VERSION 5.8 ;
BUSBITCHARS "[]" ;
DIVIDERCHAR "/" ;
UNITS
    DATABASE MICRONS 1000 ;
END UNITS

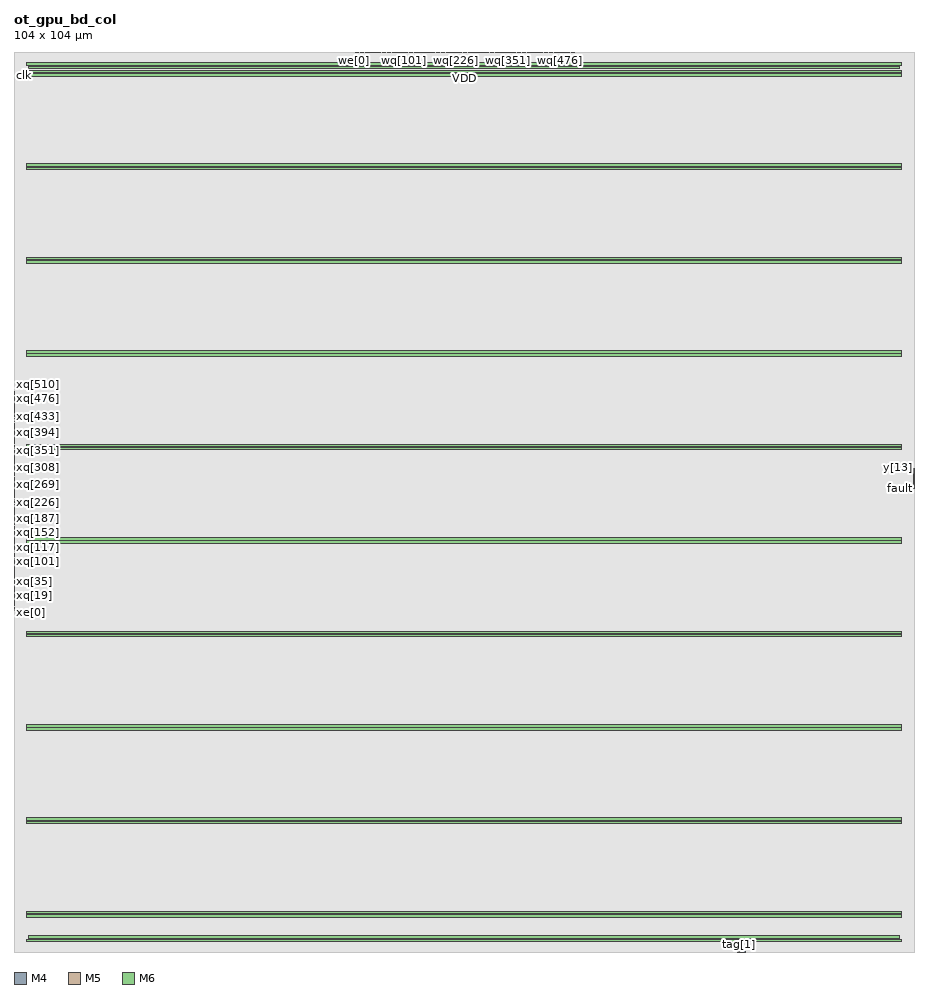
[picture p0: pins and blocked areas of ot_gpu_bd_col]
MACRO ot_gpu_bd_col
  FOREIGN ot_gpu_bd_col 0 0 ;
  CLASS BLOCK ;
  SIZE 104 BY 104 ;
  PIN clk
    DIRECTION INPUT ;
    USE SIGNAL ;
    PORT
      LAYER M4 ;
        RECT  0 101.232 0.084 101.256 ;
    END
  END clk
  PIN fault
    DIRECTION OUTPUT ;
    USE SIGNAL ;
    PORT
      LAYER M4 ;
        RECT  103.916 53.52 104 53.544 ;
    END
  END fault
  PIN first
    DIRECTION INPUT ;
    USE SIGNAL ;
    PORT
      LAYER M5 ;
        RECT  83.568 0 83.592 0.084 ;
    END
  END first
  PIN fp4
    DIRECTION INPUT ;
    USE SIGNAL ;
    PORT
      LAYER M5 ;
        RECT  83.616 0 83.64 0.084 ;
    END
  END fp4
  PIN last
    DIRECTION INPUT ;
    USE SIGNAL ;
    PORT
      LAYER M5 ;
        RECT  83.664 0 83.688 0.084 ;
    END
  END last
  PIN otag[0]
    DIRECTION OUTPUT ;
    USE SIGNAL ;
    PORT
      LAYER M4 ;
        RECT  103.916 53.568 104 53.592 ;
    END
  END otag[0]
  PIN otag[10]
    DIRECTION OUTPUT ;
    USE SIGNAL ;
    PORT
      LAYER M4 ;
        RECT  103.916 54.048 104 54.072 ;
    END
  END otag[10]
  PIN otag[11]
    DIRECTION OUTPUT ;
    USE SIGNAL ;
    PORT
      LAYER M4 ;
        RECT  103.916 54.096 104 54.12 ;
    END
  END otag[11]
  PIN otag[12]
    DIRECTION OUTPUT ;
    USE SIGNAL ;
    PORT
      LAYER M4 ;
        RECT  103.916 54.144 104 54.168 ;
    END
  END otag[12]
  PIN otag[13]
    DIRECTION OUTPUT ;
    USE SIGNAL ;
    PORT
      LAYER M4 ;
        RECT  103.916 54.192 104 54.216 ;
    END
  END otag[13]
  PIN otag[14]
    DIRECTION OUTPUT ;
    USE SIGNAL ;
    PORT
      LAYER M4 ;
        RECT  103.916 54.24 104 54.264 ;
    END
  END otag[14]
  PIN otag[15]
    DIRECTION OUTPUT ;
    USE SIGNAL ;
    PORT
      LAYER M4 ;
        RECT  103.916 54.288 104 54.312 ;
    END
  END otag[15]
  PIN otag[1]
    DIRECTION OUTPUT ;
    USE SIGNAL ;
    PORT
      LAYER M4 ;
        RECT  103.916 53.616 104 53.64 ;
    END
  END otag[1]
  PIN otag[2]
    DIRECTION OUTPUT ;
    USE SIGNAL ;
    PORT
      LAYER M4 ;
        RECT  103.916 53.664 104 53.688 ;
    END
  END otag[2]
  PIN otag[3]
    DIRECTION OUTPUT ;
    USE SIGNAL ;
    PORT
      LAYER M4 ;
        RECT  103.916 53.712 104 53.736 ;
    END
  END otag[3]
  PIN otag[4]
    DIRECTION OUTPUT ;
    USE SIGNAL ;
    PORT
      LAYER M4 ;
        RECT  103.916 53.76 104 53.784 ;
    END
  END otag[4]
  PIN otag[5]
    DIRECTION OUTPUT ;
    USE SIGNAL ;
    PORT
      LAYER M4 ;
        RECT  103.916 53.808 104 53.832 ;
    END
  END otag[5]
  PIN otag[6]
    DIRECTION OUTPUT ;
    USE SIGNAL ;
    PORT
      LAYER M4 ;
        RECT  103.916 53.856 104 53.88 ;
    END
  END otag[6]
  PIN otag[7]
    DIRECTION OUTPUT ;
    USE SIGNAL ;
    PORT
      LAYER M4 ;
        RECT  103.916 53.904 104 53.928 ;
    END
  END otag[7]
  PIN otag[8]
    DIRECTION OUTPUT ;
    USE SIGNAL ;
    PORT
      LAYER M4 ;
        RECT  103.916 53.952 104 53.976 ;
    END
  END otag[8]
  PIN otag[9]
    DIRECTION OUTPUT ;
    USE SIGNAL ;
    PORT
      LAYER M4 ;
        RECT  103.916 54 104 54.024 ;
    END
  END otag[9]
  PIN ov
    DIRECTION OUTPUT ;
    USE SIGNAL ;
    PORT
      LAYER M4 ;
        RECT  103.916 54.336 104 54.36 ;
    END
  END ov
  PIN rst_n
    DIRECTION INPUT ;
    USE SIGNAL ;
    PORT
      LAYER M5 ;
        RECT  83.712 0 83.736 0.084 ;
    END
  END rst_n
  PIN tag[0]
    DIRECTION INPUT ;
    USE SIGNAL ;
    PORT
      LAYER M5 ;
        RECT  83.76 0 83.784 0.084 ;
    END
  END tag[0]
  PIN tag[10]
    DIRECTION INPUT ;
    USE SIGNAL ;
    PORT
      LAYER M5 ;
        RECT  84.24 0 84.264 0.084 ;
    END
  END tag[10]
  PIN tag[11]
    DIRECTION INPUT ;
    USE SIGNAL ;
    PORT
      LAYER M5 ;
        RECT  84.288 0 84.312 0.084 ;
    END
  END tag[11]
  PIN tag[12]
    DIRECTION INPUT ;
    USE SIGNAL ;
    PORT
      LAYER M5 ;
        RECT  84.336 0 84.36 0.084 ;
    END
  END tag[12]
  PIN tag[13]
    DIRECTION INPUT ;
    USE SIGNAL ;
    PORT
      LAYER M5 ;
        RECT  84.384 0 84.408 0.084 ;
    END
  END tag[13]
  PIN tag[14]
    DIRECTION INPUT ;
    USE SIGNAL ;
    PORT
      LAYER M5 ;
        RECT  84.432 0 84.456 0.084 ;
    END
  END tag[14]
  PIN tag[15]
    DIRECTION INPUT ;
    USE SIGNAL ;
    PORT
      LAYER M5 ;
        RECT  84.48 0 84.504 0.084 ;
    END
  END tag[15]
  PIN tag[1]
    DIRECTION INPUT ;
    USE SIGNAL ;
    PORT
      LAYER M5 ;
        RECT  83.808 0 83.832 0.084 ;
    END
  END tag[1]
  PIN tag[2]
    DIRECTION INPUT ;
    USE SIGNAL ;
    PORT
      LAYER M5 ;
        RECT  83.856 0 83.88 0.084 ;
    END
  END tag[2]
  PIN tag[3]
    DIRECTION INPUT ;
    USE SIGNAL ;
    PORT
      LAYER M5 ;
        RECT  83.904 0 83.928 0.084 ;
    END
  END tag[3]
  PIN tag[4]
    DIRECTION INPUT ;
    USE SIGNAL ;
    PORT
      LAYER M5 ;
        RECT  83.952 0 83.976 0.084 ;
    END
  END tag[4]
  PIN tag[5]
    DIRECTION INPUT ;
    USE SIGNAL ;
    PORT
      LAYER M5 ;
        RECT  84 0 84.024 0.084 ;
    END
  END tag[5]
  PIN tag[6]
    DIRECTION INPUT ;
    USE SIGNAL ;
    PORT
      LAYER M5 ;
        RECT  84.048 0 84.072 0.084 ;
    END
  END tag[6]
  PIN tag[7]
    DIRECTION INPUT ;
    USE SIGNAL ;
    PORT
      LAYER M5 ;
        RECT  84.096 0 84.12 0.084 ;
    END
  END tag[7]
  PIN tag[8]
    DIRECTION INPUT ;
    USE SIGNAL ;
    PORT
      LAYER M5 ;
        RECT  84.144 0 84.168 0.084 ;
    END
  END tag[8]
  PIN tag[9]
    DIRECTION INPUT ;
    USE SIGNAL ;
    PORT
      LAYER M5 ;
        RECT  84.192 0 84.216 0.084 ;
    END
  END tag[9]
  PIN v
    DIRECTION INPUT ;
    USE SIGNAL ;
    PORT
      LAYER M5 ;
        RECT  84.528 0 84.552 0.084 ;
    END
  END v
  PIN we[0]
    DIRECTION INPUT ;
    USE SIGNAL ;
    PORT
      LAYER M5 ;
        RECT  39.264 103.916 39.288 104 ;
    END
  END we[0]
  PIN we[10]
    DIRECTION INPUT ;
    USE SIGNAL ;
    PORT
      LAYER M5 ;
        RECT  39.744 103.916 39.768 104 ;
    END
  END we[10]
  PIN we[11]
    DIRECTION INPUT ;
    USE SIGNAL ;
    PORT
      LAYER M5 ;
        RECT  39.792 103.916 39.816 104 ;
    END
  END we[11]
  PIN we[12]
    DIRECTION INPUT ;
    USE SIGNAL ;
    PORT
      LAYER M5 ;
        RECT  39.84 103.916 39.864 104 ;
    END
  END we[12]
  PIN we[13]
    DIRECTION INPUT ;
    USE SIGNAL ;
    PORT
      LAYER M5 ;
        RECT  39.888 103.916 39.912 104 ;
    END
  END we[13]
  PIN we[14]
    DIRECTION INPUT ;
    USE SIGNAL ;
    PORT
      LAYER M5 ;
        RECT  39.936 103.916 39.96 104 ;
    END
  END we[14]
  PIN we[15]
    DIRECTION INPUT ;
    USE SIGNAL ;
    PORT
      LAYER M5 ;
        RECT  39.984 103.916 40.008 104 ;
    END
  END we[15]
  PIN we[16]
    DIRECTION INPUT ;
    USE SIGNAL ;
    PORT
      LAYER M5 ;
        RECT  40.032 103.916 40.056 104 ;
    END
  END we[16]
  PIN we[17]
    DIRECTION INPUT ;
    USE SIGNAL ;
    PORT
      LAYER M5 ;
        RECT  40.08 103.916 40.104 104 ;
    END
  END we[17]
  PIN we[18]
    DIRECTION INPUT ;
    USE SIGNAL ;
    PORT
      LAYER M5 ;
        RECT  40.128 103.916 40.152 104 ;
    END
  END we[18]
  PIN we[19]
    DIRECTION INPUT ;
    USE SIGNAL ;
    PORT
      LAYER M5 ;
        RECT  40.176 103.916 40.2 104 ;
    END
  END we[19]
  PIN we[1]
    DIRECTION INPUT ;
    USE SIGNAL ;
    PORT
      LAYER M5 ;
        RECT  39.312 103.916 39.336 104 ;
    END
  END we[1]
  PIN we[2]
    DIRECTION INPUT ;
    USE SIGNAL ;
    PORT
      LAYER M5 ;
        RECT  39.36 103.916 39.384 104 ;
    END
  END we[2]
  PIN we[3]
    DIRECTION INPUT ;
    USE SIGNAL ;
    PORT
      LAYER M5 ;
        RECT  39.408 103.916 39.432 104 ;
    END
  END we[3]
  PIN we[4]
    DIRECTION INPUT ;
    USE SIGNAL ;
    PORT
      LAYER M5 ;
        RECT  39.456 103.916 39.48 104 ;
    END
  END we[4]
  PIN we[5]
    DIRECTION INPUT ;
    USE SIGNAL ;
    PORT
      LAYER M5 ;
        RECT  39.504 103.916 39.528 104 ;
    END
  END we[5]
  PIN we[6]
    DIRECTION INPUT ;
    USE SIGNAL ;
    PORT
      LAYER M5 ;
        RECT  39.552 103.916 39.576 104 ;
    END
  END we[6]
  PIN we[7]
    DIRECTION INPUT ;
    USE SIGNAL ;
    PORT
      LAYER M5 ;
        RECT  39.6 103.916 39.624 104 ;
    END
  END we[7]
  PIN we[8]
    DIRECTION INPUT ;
    USE SIGNAL ;
    PORT
      LAYER M5 ;
        RECT  39.648 103.916 39.672 104 ;
    END
  END we[8]
  PIN we[9]
    DIRECTION INPUT ;
    USE SIGNAL ;
    PORT
      LAYER M5 ;
        RECT  39.696 103.916 39.72 104 ;
    END
  END we[9]
  PIN wq[0]
    DIRECTION INPUT ;
    USE SIGNAL ;
    PORT
      LAYER M5 ;
        RECT  40.224 103.916 40.248 104 ;
    END
  END wq[0]
  PIN wq[100]
    DIRECTION INPUT ;
    USE SIGNAL ;
    PORT
      LAYER M5 ;
        RECT  45.024 103.916 45.048 104 ;
    END
  END wq[100]
  PIN wq[101]
    DIRECTION INPUT ;
    USE SIGNAL ;
    PORT
      LAYER M5 ;
        RECT  45.072 103.916 45.096 104 ;
    END
  END wq[101]
  PIN wq[102]
    DIRECTION INPUT ;
    USE SIGNAL ;
    PORT
      LAYER M5 ;
        RECT  45.12 103.916 45.144 104 ;
    END
  END wq[102]
  PIN wq[103]
    DIRECTION INPUT ;
    USE SIGNAL ;
    PORT
      LAYER M5 ;
        RECT  45.168 103.916 45.192 104 ;
    END
  END wq[103]
  PIN wq[104]
    DIRECTION INPUT ;
    USE SIGNAL ;
    PORT
      LAYER M5 ;
        RECT  45.216 103.916 45.24 104 ;
    END
  END wq[104]
  PIN wq[105]
    DIRECTION INPUT ;
    USE SIGNAL ;
    PORT
      LAYER M5 ;
        RECT  45.264 103.916 45.288 104 ;
    END
  END wq[105]
  PIN wq[106]
    DIRECTION INPUT ;
    USE SIGNAL ;
    PORT
      LAYER M5 ;
        RECT  45.312 103.916 45.336 104 ;
    END
  END wq[106]
  PIN wq[107]
    DIRECTION INPUT ;
    USE SIGNAL ;
    PORT
      LAYER M5 ;
        RECT  45.36 103.916 45.384 104 ;
    END
  END wq[107]
  PIN wq[108]
    DIRECTION INPUT ;
    USE SIGNAL ;
    PORT
      LAYER M5 ;
        RECT  45.408 103.916 45.432 104 ;
    END
  END wq[108]
  PIN wq[109]
    DIRECTION INPUT ;
    USE SIGNAL ;
    PORT
      LAYER M5 ;
        RECT  45.456 103.916 45.48 104 ;
    END
  END wq[109]
  PIN wq[10]
    DIRECTION INPUT ;
    USE SIGNAL ;
    PORT
      LAYER M5 ;
        RECT  40.704 103.916 40.728 104 ;
    END
  END wq[10]
  PIN wq[110]
    DIRECTION INPUT ;
    USE SIGNAL ;
    PORT
      LAYER M5 ;
        RECT  45.504 103.916 45.528 104 ;
    END
  END wq[110]
  PIN wq[111]
    DIRECTION INPUT ;
    USE SIGNAL ;
    PORT
      LAYER M5 ;
        RECT  45.552 103.916 45.576 104 ;
    END
  END wq[111]
  PIN wq[112]
    DIRECTION INPUT ;
    USE SIGNAL ;
    PORT
      LAYER M5 ;
        RECT  45.6 103.916 45.624 104 ;
    END
  END wq[112]
  PIN wq[113]
    DIRECTION INPUT ;
    USE SIGNAL ;
    PORT
      LAYER M5 ;
        RECT  45.648 103.916 45.672 104 ;
    END
  END wq[113]
  PIN wq[114]
    DIRECTION INPUT ;
    USE SIGNAL ;
    PORT
      LAYER M5 ;
        RECT  45.696 103.916 45.72 104 ;
    END
  END wq[114]
  PIN wq[115]
    DIRECTION INPUT ;
    USE SIGNAL ;
    PORT
      LAYER M5 ;
        RECT  45.744 103.916 45.768 104 ;
    END
  END wq[115]
  PIN wq[116]
    DIRECTION INPUT ;
    USE SIGNAL ;
    PORT
      LAYER M5 ;
        RECT  45.792 103.916 45.816 104 ;
    END
  END wq[116]
  PIN wq[117]
    DIRECTION INPUT ;
    USE SIGNAL ;
    PORT
      LAYER M5 ;
        RECT  45.84 103.916 45.864 104 ;
    END
  END wq[117]
  PIN wq[118]
    DIRECTION INPUT ;
    USE SIGNAL ;
    PORT
      LAYER M5 ;
        RECT  45.888 103.916 45.912 104 ;
    END
  END wq[118]
  PIN wq[119]
    DIRECTION INPUT ;
    USE SIGNAL ;
    PORT
      LAYER M5 ;
        RECT  45.936 103.916 45.96 104 ;
    END
  END wq[119]
  PIN wq[11]
    DIRECTION INPUT ;
    USE SIGNAL ;
    PORT
      LAYER M5 ;
        RECT  40.752 103.916 40.776 104 ;
    END
  END wq[11]
  PIN wq[120]
    DIRECTION INPUT ;
    USE SIGNAL ;
    PORT
      LAYER M5 ;
        RECT  45.984 103.916 46.008 104 ;
    END
  END wq[120]
  PIN wq[121]
    DIRECTION INPUT ;
    USE SIGNAL ;
    PORT
      LAYER M5 ;
        RECT  46.032 103.916 46.056 104 ;
    END
  END wq[121]
  PIN wq[122]
    DIRECTION INPUT ;
    USE SIGNAL ;
    PORT
      LAYER M5 ;
        RECT  46.08 103.916 46.104 104 ;
    END
  END wq[122]
  PIN wq[123]
    DIRECTION INPUT ;
    USE SIGNAL ;
    PORT
      LAYER M5 ;
        RECT  46.128 103.916 46.152 104 ;
    END
  END wq[123]
  PIN wq[124]
    DIRECTION INPUT ;
    USE SIGNAL ;
    PORT
      LAYER M5 ;
        RECT  46.176 103.916 46.2 104 ;
    END
  END wq[124]
  PIN wq[125]
    DIRECTION INPUT ;
    USE SIGNAL ;
    PORT
      LAYER M5 ;
        RECT  46.224 103.916 46.248 104 ;
    END
  END wq[125]
  PIN wq[126]
    DIRECTION INPUT ;
    USE SIGNAL ;
    PORT
      LAYER M5 ;
        RECT  46.272 103.916 46.296 104 ;
    END
  END wq[126]
  PIN wq[127]
    DIRECTION INPUT ;
    USE SIGNAL ;
    PORT
      LAYER M5 ;
        RECT  46.32 103.916 46.344 104 ;
    END
  END wq[127]
  PIN wq[128]
    DIRECTION INPUT ;
    USE SIGNAL ;
    PORT
      LAYER M5 ;
        RECT  46.368 103.916 46.392 104 ;
    END
  END wq[128]
  PIN wq[129]
    DIRECTION INPUT ;
    USE SIGNAL ;
    PORT
      LAYER M5 ;
        RECT  46.416 103.916 46.44 104 ;
    END
  END wq[129]
  PIN wq[12]
    DIRECTION INPUT ;
    USE SIGNAL ;
    PORT
      LAYER M5 ;
        RECT  40.8 103.916 40.824 104 ;
    END
  END wq[12]
  PIN wq[130]
    DIRECTION INPUT ;
    USE SIGNAL ;
    PORT
      LAYER M5 ;
        RECT  46.464 103.916 46.488 104 ;
    END
  END wq[130]
  PIN wq[131]
    DIRECTION INPUT ;
    USE SIGNAL ;
    PORT
      LAYER M5 ;
        RECT  46.512 103.916 46.536 104 ;
    END
  END wq[131]
  PIN wq[132]
    DIRECTION INPUT ;
    USE SIGNAL ;
    PORT
      LAYER M5 ;
        RECT  46.56 103.916 46.584 104 ;
    END
  END wq[132]
  PIN wq[133]
    DIRECTION INPUT ;
    USE SIGNAL ;
    PORT
      LAYER M5 ;
        RECT  46.608 103.916 46.632 104 ;
    END
  END wq[133]
  PIN wq[134]
    DIRECTION INPUT ;
    USE SIGNAL ;
    PORT
      LAYER M5 ;
        RECT  46.656 103.916 46.68 104 ;
    END
  END wq[134]
  PIN wq[135]
    DIRECTION INPUT ;
    USE SIGNAL ;
    PORT
      LAYER M5 ;
        RECT  46.704 103.916 46.728 104 ;
    END
  END wq[135]
  PIN wq[136]
    DIRECTION INPUT ;
    USE SIGNAL ;
    PORT
      LAYER M5 ;
        RECT  46.752 103.916 46.776 104 ;
    END
  END wq[136]
  PIN wq[137]
    DIRECTION INPUT ;
    USE SIGNAL ;
    PORT
      LAYER M5 ;
        RECT  46.8 103.916 46.824 104 ;
    END
  END wq[137]
  PIN wq[138]
    DIRECTION INPUT ;
    USE SIGNAL ;
    PORT
      LAYER M5 ;
        RECT  46.848 103.916 46.872 104 ;
    END
  END wq[138]
  PIN wq[139]
    DIRECTION INPUT ;
    USE SIGNAL ;
    PORT
      LAYER M5 ;
        RECT  46.896 103.916 46.92 104 ;
    END
  END wq[139]
  PIN wq[13]
    DIRECTION INPUT ;
    USE SIGNAL ;
    PORT
      LAYER M5 ;
        RECT  40.848 103.916 40.872 104 ;
    END
  END wq[13]
  PIN wq[140]
    DIRECTION INPUT ;
    USE SIGNAL ;
    PORT
      LAYER M5 ;
        RECT  46.944 103.916 46.968 104 ;
    END
  END wq[140]
  PIN wq[141]
    DIRECTION INPUT ;
    USE SIGNAL ;
    PORT
      LAYER M5 ;
        RECT  46.992 103.916 47.016 104 ;
    END
  END wq[141]
  PIN wq[142]
    DIRECTION INPUT ;
    USE SIGNAL ;
    PORT
      LAYER M5 ;
        RECT  47.04 103.916 47.064 104 ;
    END
  END wq[142]
  PIN wq[143]
    DIRECTION INPUT ;
    USE SIGNAL ;
    PORT
      LAYER M5 ;
        RECT  47.088 103.916 47.112 104 ;
    END
  END wq[143]
  PIN wq[144]
    DIRECTION INPUT ;
    USE SIGNAL ;
    PORT
      LAYER M5 ;
        RECT  47.136 103.916 47.16 104 ;
    END
  END wq[144]
  PIN wq[145]
    DIRECTION INPUT ;
    USE SIGNAL ;
    PORT
      LAYER M5 ;
        RECT  47.184 103.916 47.208 104 ;
    END
  END wq[145]
  PIN wq[146]
    DIRECTION INPUT ;
    USE SIGNAL ;
    PORT
      LAYER M5 ;
        RECT  47.232 103.916 47.256 104 ;
    END
  END wq[146]
  PIN wq[147]
    DIRECTION INPUT ;
    USE SIGNAL ;
    PORT
      LAYER M5 ;
        RECT  47.28 103.916 47.304 104 ;
    END
  END wq[147]
  PIN wq[148]
    DIRECTION INPUT ;
    USE SIGNAL ;
    PORT
      LAYER M5 ;
        RECT  47.328 103.916 47.352 104 ;
    END
  END wq[148]
  PIN wq[149]
    DIRECTION INPUT ;
    USE SIGNAL ;
    PORT
      LAYER M5 ;
        RECT  47.376 103.916 47.4 104 ;
    END
  END wq[149]
  PIN wq[14]
    DIRECTION INPUT ;
    USE SIGNAL ;
    PORT
      LAYER M5 ;
        RECT  40.896 103.916 40.92 104 ;
    END
  END wq[14]
  PIN wq[150]
    DIRECTION INPUT ;
    USE SIGNAL ;
    PORT
      LAYER M5 ;
        RECT  47.424 103.916 47.448 104 ;
    END
  END wq[150]
  PIN wq[151]
    DIRECTION INPUT ;
    USE SIGNAL ;
    PORT
      LAYER M5 ;
        RECT  47.472 103.916 47.496 104 ;
    END
  END wq[151]
  PIN wq[152]
    DIRECTION INPUT ;
    USE SIGNAL ;
    PORT
      LAYER M5 ;
        RECT  47.52 103.916 47.544 104 ;
    END
  END wq[152]
  PIN wq[153]
    DIRECTION INPUT ;
    USE SIGNAL ;
    PORT
      LAYER M5 ;
        RECT  47.568 103.916 47.592 104 ;
    END
  END wq[153]
  PIN wq[154]
    DIRECTION INPUT ;
    USE SIGNAL ;
    PORT
      LAYER M5 ;
        RECT  47.616 103.916 47.64 104 ;
    END
  END wq[154]
  PIN wq[155]
    DIRECTION INPUT ;
    USE SIGNAL ;
    PORT
      LAYER M5 ;
        RECT  47.664 103.916 47.688 104 ;
    END
  END wq[155]
  PIN wq[156]
    DIRECTION INPUT ;
    USE SIGNAL ;
    PORT
      LAYER M5 ;
        RECT  47.712 103.916 47.736 104 ;
    END
  END wq[156]
  PIN wq[157]
    DIRECTION INPUT ;
    USE SIGNAL ;
    PORT
      LAYER M5 ;
        RECT  47.76 103.916 47.784 104 ;
    END
  END wq[157]
  PIN wq[158]
    DIRECTION INPUT ;
    USE SIGNAL ;
    PORT
      LAYER M5 ;
        RECT  47.808 103.916 47.832 104 ;
    END
  END wq[158]
  PIN wq[159]
    DIRECTION INPUT ;
    USE SIGNAL ;
    PORT
      LAYER M5 ;
        RECT  47.856 103.916 47.88 104 ;
    END
  END wq[159]
  PIN wq[15]
    DIRECTION INPUT ;
    USE SIGNAL ;
    PORT
      LAYER M5 ;
        RECT  40.944 103.916 40.968 104 ;
    END
  END wq[15]
  PIN wq[160]
    DIRECTION INPUT ;
    USE SIGNAL ;
    PORT
      LAYER M5 ;
        RECT  47.904 103.916 47.928 104 ;
    END
  END wq[160]
  PIN wq[161]
    DIRECTION INPUT ;
    USE SIGNAL ;
    PORT
      LAYER M5 ;
        RECT  47.952 103.916 47.976 104 ;
    END
  END wq[161]
  PIN wq[162]
    DIRECTION INPUT ;
    USE SIGNAL ;
    PORT
      LAYER M5 ;
        RECT  48 103.916 48.024 104 ;
    END
  END wq[162]
  PIN wq[163]
    DIRECTION INPUT ;
    USE SIGNAL ;
    PORT
      LAYER M5 ;
        RECT  48.048 103.916 48.072 104 ;
    END
  END wq[163]
  PIN wq[164]
    DIRECTION INPUT ;
    USE SIGNAL ;
    PORT
      LAYER M5 ;
        RECT  48.096 103.916 48.12 104 ;
    END
  END wq[164]
  PIN wq[165]
    DIRECTION INPUT ;
    USE SIGNAL ;
    PORT
      LAYER M5 ;
        RECT  48.144 103.916 48.168 104 ;
    END
  END wq[165]
  PIN wq[166]
    DIRECTION INPUT ;
    USE SIGNAL ;
    PORT
      LAYER M5 ;
        RECT  48.192 103.916 48.216 104 ;
    END
  END wq[166]
  PIN wq[167]
    DIRECTION INPUT ;
    USE SIGNAL ;
    PORT
      LAYER M5 ;
        RECT  48.24 103.916 48.264 104 ;
    END
  END wq[167]
  PIN wq[168]
    DIRECTION INPUT ;
    USE SIGNAL ;
    PORT
      LAYER M5 ;
        RECT  48.288 103.916 48.312 104 ;
    END
  END wq[168]
  PIN wq[169]
    DIRECTION INPUT ;
    USE SIGNAL ;
    PORT
      LAYER M5 ;
        RECT  48.336 103.916 48.36 104 ;
    END
  END wq[169]
  PIN wq[16]
    DIRECTION INPUT ;
    USE SIGNAL ;
    PORT
      LAYER M5 ;
        RECT  40.992 103.916 41.016 104 ;
    END
  END wq[16]
  PIN wq[170]
    DIRECTION INPUT ;
    USE SIGNAL ;
    PORT
      LAYER M5 ;
        RECT  48.384 103.916 48.408 104 ;
    END
  END wq[170]
  PIN wq[171]
    DIRECTION INPUT ;
    USE SIGNAL ;
    PORT
      LAYER M5 ;
        RECT  48.432 103.916 48.456 104 ;
    END
  END wq[171]
  PIN wq[172]
    DIRECTION INPUT ;
    USE SIGNAL ;
    PORT
      LAYER M5 ;
        RECT  48.48 103.916 48.504 104 ;
    END
  END wq[172]
  PIN wq[173]
    DIRECTION INPUT ;
    USE SIGNAL ;
    PORT
      LAYER M5 ;
        RECT  48.528 103.916 48.552 104 ;
    END
  END wq[173]
  PIN wq[174]
    DIRECTION INPUT ;
    USE SIGNAL ;
    PORT
      LAYER M5 ;
        RECT  48.576 103.916 48.6 104 ;
    END
  END wq[174]
  PIN wq[175]
    DIRECTION INPUT ;
    USE SIGNAL ;
    PORT
      LAYER M5 ;
        RECT  48.624 103.916 48.648 104 ;
    END
  END wq[175]
  PIN wq[176]
    DIRECTION INPUT ;
    USE SIGNAL ;
    PORT
      LAYER M5 ;
        RECT  48.672 103.916 48.696 104 ;
    END
  END wq[176]
  PIN wq[177]
    DIRECTION INPUT ;
    USE SIGNAL ;
    PORT
      LAYER M5 ;
        RECT  48.72 103.916 48.744 104 ;
    END
  END wq[177]
  PIN wq[178]
    DIRECTION INPUT ;
    USE SIGNAL ;
    PORT
      LAYER M5 ;
        RECT  48.768 103.916 48.792 104 ;
    END
  END wq[178]
  PIN wq[179]
    DIRECTION INPUT ;
    USE SIGNAL ;
    PORT
      LAYER M5 ;
        RECT  48.816 103.916 48.84 104 ;
    END
  END wq[179]
  PIN wq[17]
    DIRECTION INPUT ;
    USE SIGNAL ;
    PORT
      LAYER M5 ;
        RECT  41.04 103.916 41.064 104 ;
    END
  END wq[17]
  PIN wq[180]
    DIRECTION INPUT ;
    USE SIGNAL ;
    PORT
      LAYER M5 ;
        RECT  48.864 103.916 48.888 104 ;
    END
  END wq[180]
  PIN wq[181]
    DIRECTION INPUT ;
    USE SIGNAL ;
    PORT
      LAYER M5 ;
        RECT  48.912 103.916 48.936 104 ;
    END
  END wq[181]
  PIN wq[182]
    DIRECTION INPUT ;
    USE SIGNAL ;
    PORT
      LAYER M5 ;
        RECT  48.96 103.916 48.984 104 ;
    END
  END wq[182]
  PIN wq[183]
    DIRECTION INPUT ;
    USE SIGNAL ;
    PORT
      LAYER M5 ;
        RECT  49.008 103.916 49.032 104 ;
    END
  END wq[183]
  PIN wq[184]
    DIRECTION INPUT ;
    USE SIGNAL ;
    PORT
      LAYER M5 ;
        RECT  49.056 103.916 49.08 104 ;
    END
  END wq[184]
  PIN wq[185]
    DIRECTION INPUT ;
    USE SIGNAL ;
    PORT
      LAYER M5 ;
        RECT  49.104 103.916 49.128 104 ;
    END
  END wq[185]
  PIN wq[186]
    DIRECTION INPUT ;
    USE SIGNAL ;
    PORT
      LAYER M5 ;
        RECT  49.152 103.916 49.176 104 ;
    END
  END wq[186]
  PIN wq[187]
    DIRECTION INPUT ;
    USE SIGNAL ;
    PORT
      LAYER M5 ;
        RECT  49.2 103.916 49.224 104 ;
    END
  END wq[187]
  PIN wq[188]
    DIRECTION INPUT ;
    USE SIGNAL ;
    PORT
      LAYER M5 ;
        RECT  49.248 103.916 49.272 104 ;
    END
  END wq[188]
  PIN wq[189]
    DIRECTION INPUT ;
    USE SIGNAL ;
    PORT
      LAYER M5 ;
        RECT  49.296 103.916 49.32 104 ;
    END
  END wq[189]
  PIN wq[18]
    DIRECTION INPUT ;
    USE SIGNAL ;
    PORT
      LAYER M5 ;
        RECT  41.088 103.916 41.112 104 ;
    END
  END wq[18]
  PIN wq[190]
    DIRECTION INPUT ;
    USE SIGNAL ;
    PORT
      LAYER M5 ;
        RECT  49.344 103.916 49.368 104 ;
    END
  END wq[190]
  PIN wq[191]
    DIRECTION INPUT ;
    USE SIGNAL ;
    PORT
      LAYER M5 ;
        RECT  49.392 103.916 49.416 104 ;
    END
  END wq[191]
  PIN wq[192]
    DIRECTION INPUT ;
    USE SIGNAL ;
    PORT
      LAYER M5 ;
        RECT  49.44 103.916 49.464 104 ;
    END
  END wq[192]
  PIN wq[193]
    DIRECTION INPUT ;
    USE SIGNAL ;
    PORT
      LAYER M5 ;
        RECT  49.488 103.916 49.512 104 ;
    END
  END wq[193]
  PIN wq[194]
    DIRECTION INPUT ;
    USE SIGNAL ;
    PORT
      LAYER M5 ;
        RECT  49.536 103.916 49.56 104 ;
    END
  END wq[194]
  PIN wq[195]
    DIRECTION INPUT ;
    USE SIGNAL ;
    PORT
      LAYER M5 ;
        RECT  49.584 103.916 49.608 104 ;
    END
  END wq[195]
  PIN wq[196]
    DIRECTION INPUT ;
    USE SIGNAL ;
    PORT
      LAYER M5 ;
        RECT  49.632 103.916 49.656 104 ;
    END
  END wq[196]
  PIN wq[197]
    DIRECTION INPUT ;
    USE SIGNAL ;
    PORT
      LAYER M5 ;
        RECT  49.68 103.916 49.704 104 ;
    END
  END wq[197]
  PIN wq[198]
    DIRECTION INPUT ;
    USE SIGNAL ;
    PORT
      LAYER M5 ;
        RECT  49.728 103.916 49.752 104 ;
    END
  END wq[198]
  PIN wq[199]
    DIRECTION INPUT ;
    USE SIGNAL ;
    PORT
      LAYER M5 ;
        RECT  49.776 103.916 49.8 104 ;
    END
  END wq[199]
  PIN wq[19]
    DIRECTION INPUT ;
    USE SIGNAL ;
    PORT
      LAYER M5 ;
        RECT  41.136 103.916 41.16 104 ;
    END
  END wq[19]
  PIN wq[1]
    DIRECTION INPUT ;
    USE SIGNAL ;
    PORT
      LAYER M5 ;
        RECT  40.272 103.916 40.296 104 ;
    END
  END wq[1]
  PIN wq[200]
    DIRECTION INPUT ;
    USE SIGNAL ;
    PORT
      LAYER M5 ;
        RECT  49.824 103.916 49.848 104 ;
    END
  END wq[200]
  PIN wq[201]
    DIRECTION INPUT ;
    USE SIGNAL ;
    PORT
      LAYER M5 ;
        RECT  49.872 103.916 49.896 104 ;
    END
  END wq[201]
  PIN wq[202]
    DIRECTION INPUT ;
    USE SIGNAL ;
    PORT
      LAYER M5 ;
        RECT  49.92 103.916 49.944 104 ;
    END
  END wq[202]
  PIN wq[203]
    DIRECTION INPUT ;
    USE SIGNAL ;
    PORT
      LAYER M5 ;
        RECT  49.968 103.916 49.992 104 ;
    END
  END wq[203]
  PIN wq[204]
    DIRECTION INPUT ;
    USE SIGNAL ;
    PORT
      LAYER M5 ;
        RECT  50.016 103.916 50.04 104 ;
    END
  END wq[204]
  PIN wq[205]
    DIRECTION INPUT ;
    USE SIGNAL ;
    PORT
      LAYER M5 ;
        RECT  50.064 103.916 50.088 104 ;
    END
  END wq[205]
  PIN wq[206]
    DIRECTION INPUT ;
    USE SIGNAL ;
    PORT
      LAYER M5 ;
        RECT  50.112 103.916 50.136 104 ;
    END
  END wq[206]
  PIN wq[207]
    DIRECTION INPUT ;
    USE SIGNAL ;
    PORT
      LAYER M5 ;
        RECT  50.16 103.916 50.184 104 ;
    END
  END wq[207]
  PIN wq[208]
    DIRECTION INPUT ;
    USE SIGNAL ;
    PORT
      LAYER M5 ;
        RECT  50.208 103.916 50.232 104 ;
    END
  END wq[208]
  PIN wq[209]
    DIRECTION INPUT ;
    USE SIGNAL ;
    PORT
      LAYER M5 ;
        RECT  50.256 103.916 50.28 104 ;
    END
  END wq[209]
  PIN wq[20]
    DIRECTION INPUT ;
    USE SIGNAL ;
    PORT
      LAYER M5 ;
        RECT  41.184 103.916 41.208 104 ;
    END
  END wq[20]
  PIN wq[210]
    DIRECTION INPUT ;
    USE SIGNAL ;
    PORT
      LAYER M5 ;
        RECT  50.304 103.916 50.328 104 ;
    END
  END wq[210]
  PIN wq[211]
    DIRECTION INPUT ;
    USE SIGNAL ;
    PORT
      LAYER M5 ;
        RECT  50.352 103.916 50.376 104 ;
    END
  END wq[211]
  PIN wq[212]
    DIRECTION INPUT ;
    USE SIGNAL ;
    PORT
      LAYER M5 ;
        RECT  50.4 103.916 50.424 104 ;
    END
  END wq[212]
  PIN wq[213]
    DIRECTION INPUT ;
    USE SIGNAL ;
    PORT
      LAYER M5 ;
        RECT  50.448 103.916 50.472 104 ;
    END
  END wq[213]
  PIN wq[214]
    DIRECTION INPUT ;
    USE SIGNAL ;
    PORT
      LAYER M5 ;
        RECT  50.496 103.916 50.52 104 ;
    END
  END wq[214]
  PIN wq[215]
    DIRECTION INPUT ;
    USE SIGNAL ;
    PORT
      LAYER M5 ;
        RECT  50.544 103.916 50.568 104 ;
    END
  END wq[215]
  PIN wq[216]
    DIRECTION INPUT ;
    USE SIGNAL ;
    PORT
      LAYER M5 ;
        RECT  50.592 103.916 50.616 104 ;
    END
  END wq[216]
  PIN wq[217]
    DIRECTION INPUT ;
    USE SIGNAL ;
    PORT
      LAYER M5 ;
        RECT  50.64 103.916 50.664 104 ;
    END
  END wq[217]
  PIN wq[218]
    DIRECTION INPUT ;
    USE SIGNAL ;
    PORT
      LAYER M5 ;
        RECT  50.688 103.916 50.712 104 ;
    END
  END wq[218]
  PIN wq[219]
    DIRECTION INPUT ;
    USE SIGNAL ;
    PORT
      LAYER M5 ;
        RECT  50.736 103.916 50.76 104 ;
    END
  END wq[219]
  PIN wq[21]
    DIRECTION INPUT ;
    USE SIGNAL ;
    PORT
      LAYER M5 ;
        RECT  41.232 103.916 41.256 104 ;
    END
  END wq[21]
  PIN wq[220]
    DIRECTION INPUT ;
    USE SIGNAL ;
    PORT
      LAYER M5 ;
        RECT  50.784 103.916 50.808 104 ;
    END
  END wq[220]
  PIN wq[221]
    DIRECTION INPUT ;
    USE SIGNAL ;
    PORT
      LAYER M5 ;
        RECT  50.832 103.916 50.856 104 ;
    END
  END wq[221]
  PIN wq[222]
    DIRECTION INPUT ;
    USE SIGNAL ;
    PORT
      LAYER M5 ;
        RECT  50.88 103.916 50.904 104 ;
    END
  END wq[222]
  PIN wq[223]
    DIRECTION INPUT ;
    USE SIGNAL ;
    PORT
      LAYER M5 ;
        RECT  50.928 103.916 50.952 104 ;
    END
  END wq[223]
  PIN wq[224]
    DIRECTION INPUT ;
    USE SIGNAL ;
    PORT
      LAYER M5 ;
        RECT  50.976 103.916 51 104 ;
    END
  END wq[224]
  PIN wq[225]
    DIRECTION INPUT ;
    USE SIGNAL ;
    PORT
      LAYER M5 ;
        RECT  51.024 103.916 51.048 104 ;
    END
  END wq[225]
  PIN wq[226]
    DIRECTION INPUT ;
    USE SIGNAL ;
    PORT
      LAYER M5 ;
        RECT  51.072 103.916 51.096 104 ;
    END
  END wq[226]
  PIN wq[227]
    DIRECTION INPUT ;
    USE SIGNAL ;
    PORT
      LAYER M5 ;
        RECT  51.12 103.916 51.144 104 ;
    END
  END wq[227]
  PIN wq[228]
    DIRECTION INPUT ;
    USE SIGNAL ;
    PORT
      LAYER M5 ;
        RECT  51.168 103.916 51.192 104 ;
    END
  END wq[228]
  PIN wq[229]
    DIRECTION INPUT ;
    USE SIGNAL ;
    PORT
      LAYER M5 ;
        RECT  51.216 103.916 51.24 104 ;
    END
  END wq[229]
  PIN wq[22]
    DIRECTION INPUT ;
    USE SIGNAL ;
    PORT
      LAYER M5 ;
        RECT  41.28 103.916 41.304 104 ;
    END
  END wq[22]
  PIN wq[230]
    DIRECTION INPUT ;
    USE SIGNAL ;
    PORT
      LAYER M5 ;
        RECT  51.264 103.916 51.288 104 ;
    END
  END wq[230]
  PIN wq[231]
    DIRECTION INPUT ;
    USE SIGNAL ;
    PORT
      LAYER M5 ;
        RECT  51.312 103.916 51.336 104 ;
    END
  END wq[231]
  PIN wq[232]
    DIRECTION INPUT ;
    USE SIGNAL ;
    PORT
      LAYER M5 ;
        RECT  51.36 103.916 51.384 104 ;
    END
  END wq[232]
  PIN wq[233]
    DIRECTION INPUT ;
    USE SIGNAL ;
    PORT
      LAYER M5 ;
        RECT  51.408 103.916 51.432 104 ;
    END
  END wq[233]
  PIN wq[234]
    DIRECTION INPUT ;
    USE SIGNAL ;
    PORT
      LAYER M5 ;
        RECT  51.456 103.916 51.48 104 ;
    END
  END wq[234]
  PIN wq[235]
    DIRECTION INPUT ;
    USE SIGNAL ;
    PORT
      LAYER M5 ;
        RECT  51.504 103.916 51.528 104 ;
    END
  END wq[235]
  PIN wq[236]
    DIRECTION INPUT ;
    USE SIGNAL ;
    PORT
      LAYER M5 ;
        RECT  51.552 103.916 51.576 104 ;
    END
  END wq[236]
  PIN wq[237]
    DIRECTION INPUT ;
    USE SIGNAL ;
    PORT
      LAYER M5 ;
        RECT  51.6 103.916 51.624 104 ;
    END
  END wq[237]
  PIN wq[238]
    DIRECTION INPUT ;
    USE SIGNAL ;
    PORT
      LAYER M5 ;
        RECT  51.648 103.916 51.672 104 ;
    END
  END wq[238]
  PIN wq[239]
    DIRECTION INPUT ;
    USE SIGNAL ;
    PORT
      LAYER M5 ;
        RECT  51.696 103.916 51.72 104 ;
    END
  END wq[239]
  PIN wq[23]
    DIRECTION INPUT ;
    USE SIGNAL ;
    PORT
      LAYER M5 ;
        RECT  41.328 103.916 41.352 104 ;
    END
  END wq[23]
  PIN wq[240]
    DIRECTION INPUT ;
    USE SIGNAL ;
    PORT
      LAYER M5 ;
        RECT  51.744 103.916 51.768 104 ;
    END
  END wq[240]
  PIN wq[241]
    DIRECTION INPUT ;
    USE SIGNAL ;
    PORT
      LAYER M5 ;
        RECT  51.792 103.916 51.816 104 ;
    END
  END wq[241]
  PIN wq[242]
    DIRECTION INPUT ;
    USE SIGNAL ;
    PORT
      LAYER M5 ;
        RECT  51.84 103.916 51.864 104 ;
    END
  END wq[242]
  PIN wq[243]
    DIRECTION INPUT ;
    USE SIGNAL ;
    PORT
      LAYER M5 ;
        RECT  51.888 103.916 51.912 104 ;
    END
  END wq[243]
  PIN wq[244]
    DIRECTION INPUT ;
    USE SIGNAL ;
    PORT
      LAYER M5 ;
        RECT  51.936 103.916 51.96 104 ;
    END
  END wq[244]
  PIN wq[245]
    DIRECTION INPUT ;
    USE SIGNAL ;
    PORT
      LAYER M5 ;
        RECT  51.984 103.916 52.008 104 ;
    END
  END wq[245]
  PIN wq[246]
    DIRECTION INPUT ;
    USE SIGNAL ;
    PORT
      LAYER M5 ;
        RECT  52.032 103.916 52.056 104 ;
    END
  END wq[246]
  PIN wq[247]
    DIRECTION INPUT ;
    USE SIGNAL ;
    PORT
      LAYER M5 ;
        RECT  52.08 103.916 52.104 104 ;
    END
  END wq[247]
  PIN wq[248]
    DIRECTION INPUT ;
    USE SIGNAL ;
    PORT
      LAYER M5 ;
        RECT  52.128 103.916 52.152 104 ;
    END
  END wq[248]
  PIN wq[249]
    DIRECTION INPUT ;
    USE SIGNAL ;
    PORT
      LAYER M5 ;
        RECT  52.176 103.916 52.2 104 ;
    END
  END wq[249]
  PIN wq[24]
    DIRECTION INPUT ;
    USE SIGNAL ;
    PORT
      LAYER M5 ;
        RECT  41.376 103.916 41.4 104 ;
    END
  END wq[24]
  PIN wq[250]
    DIRECTION INPUT ;
    USE SIGNAL ;
    PORT
      LAYER M5 ;
        RECT  52.224 103.916 52.248 104 ;
    END
  END wq[250]
  PIN wq[251]
    DIRECTION INPUT ;
    USE SIGNAL ;
    PORT
      LAYER M5 ;
        RECT  52.272 103.916 52.296 104 ;
    END
  END wq[251]
  PIN wq[252]
    DIRECTION INPUT ;
    USE SIGNAL ;
    PORT
      LAYER M5 ;
        RECT  52.32 103.916 52.344 104 ;
    END
  END wq[252]
  PIN wq[253]
    DIRECTION INPUT ;
    USE SIGNAL ;
    PORT
      LAYER M5 ;
        RECT  52.368 103.916 52.392 104 ;
    END
  END wq[253]
  PIN wq[254]
    DIRECTION INPUT ;
    USE SIGNAL ;
    PORT
      LAYER M5 ;
        RECT  52.416 103.916 52.44 104 ;
    END
  END wq[254]
  PIN wq[255]
    DIRECTION INPUT ;
    USE SIGNAL ;
    PORT
      LAYER M5 ;
        RECT  52.464 103.916 52.488 104 ;
    END
  END wq[255]
  PIN wq[256]
    DIRECTION INPUT ;
    USE SIGNAL ;
    PORT
      LAYER M5 ;
        RECT  52.512 103.916 52.536 104 ;
    END
  END wq[256]
  PIN wq[257]
    DIRECTION INPUT ;
    USE SIGNAL ;
    PORT
      LAYER M5 ;
        RECT  52.56 103.916 52.584 104 ;
    END
  END wq[257]
  PIN wq[258]
    DIRECTION INPUT ;
    USE SIGNAL ;
    PORT
      LAYER M5 ;
        RECT  52.608 103.916 52.632 104 ;
    END
  END wq[258]
  PIN wq[259]
    DIRECTION INPUT ;
    USE SIGNAL ;
    PORT
      LAYER M5 ;
        RECT  52.656 103.916 52.68 104 ;
    END
  END wq[259]
  PIN wq[25]
    DIRECTION INPUT ;
    USE SIGNAL ;
    PORT
      LAYER M5 ;
        RECT  41.424 103.916 41.448 104 ;
    END
  END wq[25]
  PIN wq[260]
    DIRECTION INPUT ;
    USE SIGNAL ;
    PORT
      LAYER M5 ;
        RECT  52.704 103.916 52.728 104 ;
    END
  END wq[260]
  PIN wq[261]
    DIRECTION INPUT ;
    USE SIGNAL ;
    PORT
      LAYER M5 ;
        RECT  52.752 103.916 52.776 104 ;
    END
  END wq[261]
  PIN wq[262]
    DIRECTION INPUT ;
    USE SIGNAL ;
    PORT
      LAYER M5 ;
        RECT  52.8 103.916 52.824 104 ;
    END
  END wq[262]
  PIN wq[263]
    DIRECTION INPUT ;
    USE SIGNAL ;
    PORT
      LAYER M5 ;
        RECT  52.848 103.916 52.872 104 ;
    END
  END wq[263]
  PIN wq[264]
    DIRECTION INPUT ;
    USE SIGNAL ;
    PORT
      LAYER M5 ;
        RECT  52.896 103.916 52.92 104 ;
    END
  END wq[264]
  PIN wq[265]
    DIRECTION INPUT ;
    USE SIGNAL ;
    PORT
      LAYER M5 ;
        RECT  52.944 103.916 52.968 104 ;
    END
  END wq[265]
  PIN wq[266]
    DIRECTION INPUT ;
    USE SIGNAL ;
    PORT
      LAYER M5 ;
        RECT  52.992 103.916 53.016 104 ;
    END
  END wq[266]
  PIN wq[267]
    DIRECTION INPUT ;
    USE SIGNAL ;
    PORT
      LAYER M5 ;
        RECT  53.04 103.916 53.064 104 ;
    END
  END wq[267]
  PIN wq[268]
    DIRECTION INPUT ;
    USE SIGNAL ;
    PORT
      LAYER M5 ;
        RECT  53.088 103.916 53.112 104 ;
    END
  END wq[268]
  PIN wq[269]
    DIRECTION INPUT ;
    USE SIGNAL ;
    PORT
      LAYER M5 ;
        RECT  53.136 103.916 53.16 104 ;
    END
  END wq[269]
  PIN wq[26]
    DIRECTION INPUT ;
    USE SIGNAL ;
    PORT
      LAYER M5 ;
        RECT  41.472 103.916 41.496 104 ;
    END
  END wq[26]
  PIN wq[270]
    DIRECTION INPUT ;
    USE SIGNAL ;
    PORT
      LAYER M5 ;
        RECT  53.184 103.916 53.208 104 ;
    END
  END wq[270]
  PIN wq[271]
    DIRECTION INPUT ;
    USE SIGNAL ;
    PORT
      LAYER M5 ;
        RECT  53.232 103.916 53.256 104 ;
    END
  END wq[271]
  PIN wq[272]
    DIRECTION INPUT ;
    USE SIGNAL ;
    PORT
      LAYER M5 ;
        RECT  53.28 103.916 53.304 104 ;
    END
  END wq[272]
  PIN wq[273]
    DIRECTION INPUT ;
    USE SIGNAL ;
    PORT
      LAYER M5 ;
        RECT  53.328 103.916 53.352 104 ;
    END
  END wq[273]
  PIN wq[274]
    DIRECTION INPUT ;
    USE SIGNAL ;
    PORT
      LAYER M5 ;
        RECT  53.376 103.916 53.4 104 ;
    END
  END wq[274]
  PIN wq[275]
    DIRECTION INPUT ;
    USE SIGNAL ;
    PORT
      LAYER M5 ;
        RECT  53.424 103.916 53.448 104 ;
    END
  END wq[275]
  PIN wq[276]
    DIRECTION INPUT ;
    USE SIGNAL ;
    PORT
      LAYER M5 ;
        RECT  53.472 103.916 53.496 104 ;
    END
  END wq[276]
  PIN wq[277]
    DIRECTION INPUT ;
    USE SIGNAL ;
    PORT
      LAYER M5 ;
        RECT  53.52 103.916 53.544 104 ;
    END
  END wq[277]
  PIN wq[278]
    DIRECTION INPUT ;
    USE SIGNAL ;
    PORT
      LAYER M5 ;
        RECT  53.568 103.916 53.592 104 ;
    END
  END wq[278]
  PIN wq[279]
    DIRECTION INPUT ;
    USE SIGNAL ;
    PORT
      LAYER M5 ;
        RECT  53.616 103.916 53.64 104 ;
    END
  END wq[279]
  PIN wq[27]
    DIRECTION INPUT ;
    USE SIGNAL ;
    PORT
      LAYER M5 ;
        RECT  41.52 103.916 41.544 104 ;
    END
  END wq[27]
  PIN wq[280]
    DIRECTION INPUT ;
    USE SIGNAL ;
    PORT
      LAYER M5 ;
        RECT  53.664 103.916 53.688 104 ;
    END
  END wq[280]
  PIN wq[281]
    DIRECTION INPUT ;
    USE SIGNAL ;
    PORT
      LAYER M5 ;
        RECT  53.712 103.916 53.736 104 ;
    END
  END wq[281]
  PIN wq[282]
    DIRECTION INPUT ;
    USE SIGNAL ;
    PORT
      LAYER M5 ;
        RECT  53.76 103.916 53.784 104 ;
    END
  END wq[282]
  PIN wq[283]
    DIRECTION INPUT ;
    USE SIGNAL ;
    PORT
      LAYER M5 ;
        RECT  53.808 103.916 53.832 104 ;
    END
  END wq[283]
  PIN wq[284]
    DIRECTION INPUT ;
    USE SIGNAL ;
    PORT
      LAYER M5 ;
        RECT  53.856 103.916 53.88 104 ;
    END
  END wq[284]
  PIN wq[285]
    DIRECTION INPUT ;
    USE SIGNAL ;
    PORT
      LAYER M5 ;
        RECT  53.904 103.916 53.928 104 ;
    END
  END wq[285]
  PIN wq[286]
    DIRECTION INPUT ;
    USE SIGNAL ;
    PORT
      LAYER M5 ;
        RECT  53.952 103.916 53.976 104 ;
    END
  END wq[286]
  PIN wq[287]
    DIRECTION INPUT ;
    USE SIGNAL ;
    PORT
      LAYER M5 ;
        RECT  54 103.916 54.024 104 ;
    END
  END wq[287]
  PIN wq[288]
    DIRECTION INPUT ;
    USE SIGNAL ;
    PORT
      LAYER M5 ;
        RECT  54.048 103.916 54.072 104 ;
    END
  END wq[288]
  PIN wq[289]
    DIRECTION INPUT ;
    USE SIGNAL ;
    PORT
      LAYER M5 ;
        RECT  54.096 103.916 54.12 104 ;
    END
  END wq[289]
  PIN wq[28]
    DIRECTION INPUT ;
    USE SIGNAL ;
    PORT
      LAYER M5 ;
        RECT  41.568 103.916 41.592 104 ;
    END
  END wq[28]
  PIN wq[290]
    DIRECTION INPUT ;
    USE SIGNAL ;
    PORT
      LAYER M5 ;
        RECT  54.144 103.916 54.168 104 ;
    END
  END wq[290]
  PIN wq[291]
    DIRECTION INPUT ;
    USE SIGNAL ;
    PORT
      LAYER M5 ;
        RECT  54.192 103.916 54.216 104 ;
    END
  END wq[291]
  PIN wq[292]
    DIRECTION INPUT ;
    USE SIGNAL ;
    PORT
      LAYER M5 ;
        RECT  54.24 103.916 54.264 104 ;
    END
  END wq[292]
  PIN wq[293]
    DIRECTION INPUT ;
    USE SIGNAL ;
    PORT
      LAYER M5 ;
        RECT  54.288 103.916 54.312 104 ;
    END
  END wq[293]
  PIN wq[294]
    DIRECTION INPUT ;
    USE SIGNAL ;
    PORT
      LAYER M5 ;
        RECT  54.336 103.916 54.36 104 ;
    END
  END wq[294]
  PIN wq[295]
    DIRECTION INPUT ;
    USE SIGNAL ;
    PORT
      LAYER M5 ;
        RECT  54.384 103.916 54.408 104 ;
    END
  END wq[295]
  PIN wq[296]
    DIRECTION INPUT ;
    USE SIGNAL ;
    PORT
      LAYER M5 ;
        RECT  54.432 103.916 54.456 104 ;
    END
  END wq[296]
  PIN wq[297]
    DIRECTION INPUT ;
    USE SIGNAL ;
    PORT
      LAYER M5 ;
        RECT  54.48 103.916 54.504 104 ;
    END
  END wq[297]
  PIN wq[298]
    DIRECTION INPUT ;
    USE SIGNAL ;
    PORT
      LAYER M5 ;
        RECT  54.528 103.916 54.552 104 ;
    END
  END wq[298]
  PIN wq[299]
    DIRECTION INPUT ;
    USE SIGNAL ;
    PORT
      LAYER M5 ;
        RECT  54.576 103.916 54.6 104 ;
    END
  END wq[299]
  PIN wq[29]
    DIRECTION INPUT ;
    USE SIGNAL ;
    PORT
      LAYER M5 ;
        RECT  41.616 103.916 41.64 104 ;
    END
  END wq[29]
  PIN wq[2]
    DIRECTION INPUT ;
    USE SIGNAL ;
    PORT
      LAYER M5 ;
        RECT  40.32 103.916 40.344 104 ;
    END
  END wq[2]
  PIN wq[300]
    DIRECTION INPUT ;
    USE SIGNAL ;
    PORT
      LAYER M5 ;
        RECT  54.624 103.916 54.648 104 ;
    END
  END wq[300]
  PIN wq[301]
    DIRECTION INPUT ;
    USE SIGNAL ;
    PORT
      LAYER M5 ;
        RECT  54.672 103.916 54.696 104 ;
    END
  END wq[301]
  PIN wq[302]
    DIRECTION INPUT ;
    USE SIGNAL ;
    PORT
      LAYER M5 ;
        RECT  54.72 103.916 54.744 104 ;
    END
  END wq[302]
  PIN wq[303]
    DIRECTION INPUT ;
    USE SIGNAL ;
    PORT
      LAYER M5 ;
        RECT  54.768 103.916 54.792 104 ;
    END
  END wq[303]
  PIN wq[304]
    DIRECTION INPUT ;
    USE SIGNAL ;
    PORT
      LAYER M5 ;
        RECT  54.816 103.916 54.84 104 ;
    END
  END wq[304]
  PIN wq[305]
    DIRECTION INPUT ;
    USE SIGNAL ;
    PORT
      LAYER M5 ;
        RECT  54.864 103.916 54.888 104 ;
    END
  END wq[305]
  PIN wq[306]
    DIRECTION INPUT ;
    USE SIGNAL ;
    PORT
      LAYER M5 ;
        RECT  54.912 103.916 54.936 104 ;
    END
  END wq[306]
  PIN wq[307]
    DIRECTION INPUT ;
    USE SIGNAL ;
    PORT
      LAYER M5 ;
        RECT  54.96 103.916 54.984 104 ;
    END
  END wq[307]
  PIN wq[308]
    DIRECTION INPUT ;
    USE SIGNAL ;
    PORT
      LAYER M5 ;
        RECT  55.008 103.916 55.032 104 ;
    END
  END wq[308]
  PIN wq[309]
    DIRECTION INPUT ;
    USE SIGNAL ;
    PORT
      LAYER M5 ;
        RECT  55.056 103.916 55.08 104 ;
    END
  END wq[309]
  PIN wq[30]
    DIRECTION INPUT ;
    USE SIGNAL ;
    PORT
      LAYER M5 ;
        RECT  41.664 103.916 41.688 104 ;
    END
  END wq[30]
  PIN wq[310]
    DIRECTION INPUT ;
    USE SIGNAL ;
    PORT
      LAYER M5 ;
        RECT  55.104 103.916 55.128 104 ;
    END
  END wq[310]
  PIN wq[311]
    DIRECTION INPUT ;
    USE SIGNAL ;
    PORT
      LAYER M5 ;
        RECT  55.152 103.916 55.176 104 ;
    END
  END wq[311]
  PIN wq[312]
    DIRECTION INPUT ;
    USE SIGNAL ;
    PORT
      LAYER M5 ;
        RECT  55.2 103.916 55.224 104 ;
    END
  END wq[312]
  PIN wq[313]
    DIRECTION INPUT ;
    USE SIGNAL ;
    PORT
      LAYER M5 ;
        RECT  55.248 103.916 55.272 104 ;
    END
  END wq[313]
  PIN wq[314]
    DIRECTION INPUT ;
    USE SIGNAL ;
    PORT
      LAYER M5 ;
        RECT  55.296 103.916 55.32 104 ;
    END
  END wq[314]
  PIN wq[315]
    DIRECTION INPUT ;
    USE SIGNAL ;
    PORT
      LAYER M5 ;
        RECT  55.344 103.916 55.368 104 ;
    END
  END wq[315]
  PIN wq[316]
    DIRECTION INPUT ;
    USE SIGNAL ;
    PORT
      LAYER M5 ;
        RECT  55.392 103.916 55.416 104 ;
    END
  END wq[316]
  PIN wq[317]
    DIRECTION INPUT ;
    USE SIGNAL ;
    PORT
      LAYER M5 ;
        RECT  55.44 103.916 55.464 104 ;
    END
  END wq[317]
  PIN wq[318]
    DIRECTION INPUT ;
    USE SIGNAL ;
    PORT
      LAYER M5 ;
        RECT  55.488 103.916 55.512 104 ;
    END
  END wq[318]
  PIN wq[319]
    DIRECTION INPUT ;
    USE SIGNAL ;
    PORT
      LAYER M5 ;
        RECT  55.536 103.916 55.56 104 ;
    END
  END wq[319]
  PIN wq[31]
    DIRECTION INPUT ;
    USE SIGNAL ;
    PORT
      LAYER M5 ;
        RECT  41.712 103.916 41.736 104 ;
    END
  END wq[31]
  PIN wq[320]
    DIRECTION INPUT ;
    USE SIGNAL ;
    PORT
      LAYER M5 ;
        RECT  55.584 103.916 55.608 104 ;
    END
  END wq[320]
  PIN wq[321]
    DIRECTION INPUT ;
    USE SIGNAL ;
    PORT
      LAYER M5 ;
        RECT  55.632 103.916 55.656 104 ;
    END
  END wq[321]
  PIN wq[322]
    DIRECTION INPUT ;
    USE SIGNAL ;
    PORT
      LAYER M5 ;
        RECT  55.68 103.916 55.704 104 ;
    END
  END wq[322]
  PIN wq[323]
    DIRECTION INPUT ;
    USE SIGNAL ;
    PORT
      LAYER M5 ;
        RECT  55.728 103.916 55.752 104 ;
    END
  END wq[323]
  PIN wq[324]
    DIRECTION INPUT ;
    USE SIGNAL ;
    PORT
      LAYER M5 ;
        RECT  55.776 103.916 55.8 104 ;
    END
  END wq[324]
  PIN wq[325]
    DIRECTION INPUT ;
    USE SIGNAL ;
    PORT
      LAYER M5 ;
        RECT  55.824 103.916 55.848 104 ;
    END
  END wq[325]
  PIN wq[326]
    DIRECTION INPUT ;
    USE SIGNAL ;
    PORT
      LAYER M5 ;
        RECT  55.872 103.916 55.896 104 ;
    END
  END wq[326]
  PIN wq[327]
    DIRECTION INPUT ;
    USE SIGNAL ;
    PORT
      LAYER M5 ;
        RECT  55.92 103.916 55.944 104 ;
    END
  END wq[327]
  PIN wq[328]
    DIRECTION INPUT ;
    USE SIGNAL ;
    PORT
      LAYER M5 ;
        RECT  55.968 103.916 55.992 104 ;
    END
  END wq[328]
  PIN wq[329]
    DIRECTION INPUT ;
    USE SIGNAL ;
    PORT
      LAYER M5 ;
        RECT  56.016 103.916 56.04 104 ;
    END
  END wq[329]
  PIN wq[32]
    DIRECTION INPUT ;
    USE SIGNAL ;
    PORT
      LAYER M5 ;
        RECT  41.76 103.916 41.784 104 ;
    END
  END wq[32]
  PIN wq[330]
    DIRECTION INPUT ;
    USE SIGNAL ;
    PORT
      LAYER M5 ;
        RECT  56.064 103.916 56.088 104 ;
    END
  END wq[330]
  PIN wq[331]
    DIRECTION INPUT ;
    USE SIGNAL ;
    PORT
      LAYER M5 ;
        RECT  56.112 103.916 56.136 104 ;
    END
  END wq[331]
  PIN wq[332]
    DIRECTION INPUT ;
    USE SIGNAL ;
    PORT
      LAYER M5 ;
        RECT  56.16 103.916 56.184 104 ;
    END
  END wq[332]
  PIN wq[333]
    DIRECTION INPUT ;
    USE SIGNAL ;
    PORT
      LAYER M5 ;
        RECT  56.208 103.916 56.232 104 ;
    END
  END wq[333]
  PIN wq[334]
    DIRECTION INPUT ;
    USE SIGNAL ;
    PORT
      LAYER M5 ;
        RECT  56.256 103.916 56.28 104 ;
    END
  END wq[334]
  PIN wq[335]
    DIRECTION INPUT ;
    USE SIGNAL ;
    PORT
      LAYER M5 ;
        RECT  56.304 103.916 56.328 104 ;
    END
  END wq[335]
  PIN wq[336]
    DIRECTION INPUT ;
    USE SIGNAL ;
    PORT
      LAYER M5 ;
        RECT  56.352 103.916 56.376 104 ;
    END
  END wq[336]
  PIN wq[337]
    DIRECTION INPUT ;
    USE SIGNAL ;
    PORT
      LAYER M5 ;
        RECT  56.4 103.916 56.424 104 ;
    END
  END wq[337]
  PIN wq[338]
    DIRECTION INPUT ;
    USE SIGNAL ;
    PORT
      LAYER M5 ;
        RECT  56.448 103.916 56.472 104 ;
    END
  END wq[338]
  PIN wq[339]
    DIRECTION INPUT ;
    USE SIGNAL ;
    PORT
      LAYER M5 ;
        RECT  56.496 103.916 56.52 104 ;
    END
  END wq[339]
  PIN wq[33]
    DIRECTION INPUT ;
    USE SIGNAL ;
    PORT
      LAYER M5 ;
        RECT  41.808 103.916 41.832 104 ;
    END
  END wq[33]
  PIN wq[340]
    DIRECTION INPUT ;
    USE SIGNAL ;
    PORT
      LAYER M5 ;
        RECT  56.544 103.916 56.568 104 ;
    END
  END wq[340]
  PIN wq[341]
    DIRECTION INPUT ;
    USE SIGNAL ;
    PORT
      LAYER M5 ;
        RECT  56.592 103.916 56.616 104 ;
    END
  END wq[341]
  PIN wq[342]
    DIRECTION INPUT ;
    USE SIGNAL ;
    PORT
      LAYER M5 ;
        RECT  56.64 103.916 56.664 104 ;
    END
  END wq[342]
  PIN wq[343]
    DIRECTION INPUT ;
    USE SIGNAL ;
    PORT
      LAYER M5 ;
        RECT  56.688 103.916 56.712 104 ;
    END
  END wq[343]
  PIN wq[344]
    DIRECTION INPUT ;
    USE SIGNAL ;
    PORT
      LAYER M5 ;
        RECT  56.736 103.916 56.76 104 ;
    END
  END wq[344]
  PIN wq[345]
    DIRECTION INPUT ;
    USE SIGNAL ;
    PORT
      LAYER M5 ;
        RECT  56.784 103.916 56.808 104 ;
    END
  END wq[345]
  PIN wq[346]
    DIRECTION INPUT ;
    USE SIGNAL ;
    PORT
      LAYER M5 ;
        RECT  56.832 103.916 56.856 104 ;
    END
  END wq[346]
  PIN wq[347]
    DIRECTION INPUT ;
    USE SIGNAL ;
    PORT
      LAYER M5 ;
        RECT  56.88 103.916 56.904 104 ;
    END
  END wq[347]
  PIN wq[348]
    DIRECTION INPUT ;
    USE SIGNAL ;
    PORT
      LAYER M5 ;
        RECT  56.928 103.916 56.952 104 ;
    END
  END wq[348]
  PIN wq[349]
    DIRECTION INPUT ;
    USE SIGNAL ;
    PORT
      LAYER M5 ;
        RECT  56.976 103.916 57 104 ;
    END
  END wq[349]
  PIN wq[34]
    DIRECTION INPUT ;
    USE SIGNAL ;
    PORT
      LAYER M5 ;
        RECT  41.856 103.916 41.88 104 ;
    END
  END wq[34]
  PIN wq[350]
    DIRECTION INPUT ;
    USE SIGNAL ;
    PORT
      LAYER M5 ;
        RECT  57.024 103.916 57.048 104 ;
    END
  END wq[350]
  PIN wq[351]
    DIRECTION INPUT ;
    USE SIGNAL ;
    PORT
      LAYER M5 ;
        RECT  57.072 103.916 57.096 104 ;
    END
  END wq[351]
  PIN wq[352]
    DIRECTION INPUT ;
    USE SIGNAL ;
    PORT
      LAYER M5 ;
        RECT  57.12 103.916 57.144 104 ;
    END
  END wq[352]
  PIN wq[353]
    DIRECTION INPUT ;
    USE SIGNAL ;
    PORT
      LAYER M5 ;
        RECT  57.168 103.916 57.192 104 ;
    END
  END wq[353]
  PIN wq[354]
    DIRECTION INPUT ;
    USE SIGNAL ;
    PORT
      LAYER M5 ;
        RECT  57.216 103.916 57.24 104 ;
    END
  END wq[354]
  PIN wq[355]
    DIRECTION INPUT ;
    USE SIGNAL ;
    PORT
      LAYER M5 ;
        RECT  57.264 103.916 57.288 104 ;
    END
  END wq[355]
  PIN wq[356]
    DIRECTION INPUT ;
    USE SIGNAL ;
    PORT
      LAYER M5 ;
        RECT  57.312 103.916 57.336 104 ;
    END
  END wq[356]
  PIN wq[357]
    DIRECTION INPUT ;
    USE SIGNAL ;
    PORT
      LAYER M5 ;
        RECT  57.36 103.916 57.384 104 ;
    END
  END wq[357]
  PIN wq[358]
    DIRECTION INPUT ;
    USE SIGNAL ;
    PORT
      LAYER M5 ;
        RECT  57.408 103.916 57.432 104 ;
    END
  END wq[358]
  PIN wq[359]
    DIRECTION INPUT ;
    USE SIGNAL ;
    PORT
      LAYER M5 ;
        RECT  57.456 103.916 57.48 104 ;
    END
  END wq[359]
  PIN wq[35]
    DIRECTION INPUT ;
    USE SIGNAL ;
    PORT
      LAYER M5 ;
        RECT  41.904 103.916 41.928 104 ;
    END
  END wq[35]
  PIN wq[360]
    DIRECTION INPUT ;
    USE SIGNAL ;
    PORT
      LAYER M5 ;
        RECT  57.504 103.916 57.528 104 ;
    END
  END wq[360]
  PIN wq[361]
    DIRECTION INPUT ;
    USE SIGNAL ;
    PORT
      LAYER M5 ;
        RECT  57.552 103.916 57.576 104 ;
    END
  END wq[361]
  PIN wq[362]
    DIRECTION INPUT ;
    USE SIGNAL ;
    PORT
      LAYER M5 ;
        RECT  57.6 103.916 57.624 104 ;
    END
  END wq[362]
  PIN wq[363]
    DIRECTION INPUT ;
    USE SIGNAL ;
    PORT
      LAYER M5 ;
        RECT  57.648 103.916 57.672 104 ;
    END
  END wq[363]
  PIN wq[364]
    DIRECTION INPUT ;
    USE SIGNAL ;
    PORT
      LAYER M5 ;
        RECT  57.696 103.916 57.72 104 ;
    END
  END wq[364]
  PIN wq[365]
    DIRECTION INPUT ;
    USE SIGNAL ;
    PORT
      LAYER M5 ;
        RECT  57.744 103.916 57.768 104 ;
    END
  END wq[365]
  PIN wq[366]
    DIRECTION INPUT ;
    USE SIGNAL ;
    PORT
      LAYER M5 ;
        RECT  57.792 103.916 57.816 104 ;
    END
  END wq[366]
  PIN wq[367]
    DIRECTION INPUT ;
    USE SIGNAL ;
    PORT
      LAYER M5 ;
        RECT  57.84 103.916 57.864 104 ;
    END
  END wq[367]
  PIN wq[368]
    DIRECTION INPUT ;
    USE SIGNAL ;
    PORT
      LAYER M5 ;
        RECT  57.888 103.916 57.912 104 ;
    END
  END wq[368]
  PIN wq[369]
    DIRECTION INPUT ;
    USE SIGNAL ;
    PORT
      LAYER M5 ;
        RECT  57.936 103.916 57.96 104 ;
    END
  END wq[369]
  PIN wq[36]
    DIRECTION INPUT ;
    USE SIGNAL ;
    PORT
      LAYER M5 ;
        RECT  41.952 103.916 41.976 104 ;
    END
  END wq[36]
  PIN wq[370]
    DIRECTION INPUT ;
    USE SIGNAL ;
    PORT
      LAYER M5 ;
        RECT  57.984 103.916 58.008 104 ;
    END
  END wq[370]
  PIN wq[371]
    DIRECTION INPUT ;
    USE SIGNAL ;
    PORT
      LAYER M5 ;
        RECT  58.032 103.916 58.056 104 ;
    END
  END wq[371]
  PIN wq[372]
    DIRECTION INPUT ;
    USE SIGNAL ;
    PORT
      LAYER M5 ;
        RECT  58.08 103.916 58.104 104 ;
    END
  END wq[372]
  PIN wq[373]
    DIRECTION INPUT ;
    USE SIGNAL ;
    PORT
      LAYER M5 ;
        RECT  58.128 103.916 58.152 104 ;
    END
  END wq[373]
  PIN wq[374]
    DIRECTION INPUT ;
    USE SIGNAL ;
    PORT
      LAYER M5 ;
        RECT  58.176 103.916 58.2 104 ;
    END
  END wq[374]
  PIN wq[375]
    DIRECTION INPUT ;
    USE SIGNAL ;
    PORT
      LAYER M5 ;
        RECT  58.224 103.916 58.248 104 ;
    END
  END wq[375]
  PIN wq[376]
    DIRECTION INPUT ;
    USE SIGNAL ;
    PORT
      LAYER M5 ;
        RECT  58.272 103.916 58.296 104 ;
    END
  END wq[376]
  PIN wq[377]
    DIRECTION INPUT ;
    USE SIGNAL ;
    PORT
      LAYER M5 ;
        RECT  58.32 103.916 58.344 104 ;
    END
  END wq[377]
  PIN wq[378]
    DIRECTION INPUT ;
    USE SIGNAL ;
    PORT
      LAYER M5 ;
        RECT  58.368 103.916 58.392 104 ;
    END
  END wq[378]
  PIN wq[379]
    DIRECTION INPUT ;
    USE SIGNAL ;
    PORT
      LAYER M5 ;
        RECT  58.416 103.916 58.44 104 ;
    END
  END wq[379]
  PIN wq[37]
    DIRECTION INPUT ;
    USE SIGNAL ;
    PORT
      LAYER M5 ;
        RECT  42 103.916 42.024 104 ;
    END
  END wq[37]
  PIN wq[380]
    DIRECTION INPUT ;
    USE SIGNAL ;
    PORT
      LAYER M5 ;
        RECT  58.464 103.916 58.488 104 ;
    END
  END wq[380]
  PIN wq[381]
    DIRECTION INPUT ;
    USE SIGNAL ;
    PORT
      LAYER M5 ;
        RECT  58.512 103.916 58.536 104 ;
    END
  END wq[381]
  PIN wq[382]
    DIRECTION INPUT ;
    USE SIGNAL ;
    PORT
      LAYER M5 ;
        RECT  58.56 103.916 58.584 104 ;
    END
  END wq[382]
  PIN wq[383]
    DIRECTION INPUT ;
    USE SIGNAL ;
    PORT
      LAYER M5 ;
        RECT  58.608 103.916 58.632 104 ;
    END
  END wq[383]
  PIN wq[384]
    DIRECTION INPUT ;
    USE SIGNAL ;
    PORT
      LAYER M5 ;
        RECT  58.656 103.916 58.68 104 ;
    END
  END wq[384]
  PIN wq[385]
    DIRECTION INPUT ;
    USE SIGNAL ;
    PORT
      LAYER M5 ;
        RECT  58.704 103.916 58.728 104 ;
    END
  END wq[385]
  PIN wq[386]
    DIRECTION INPUT ;
    USE SIGNAL ;
    PORT
      LAYER M5 ;
        RECT  58.752 103.916 58.776 104 ;
    END
  END wq[386]
  PIN wq[387]
    DIRECTION INPUT ;
    USE SIGNAL ;
    PORT
      LAYER M5 ;
        RECT  58.8 103.916 58.824 104 ;
    END
  END wq[387]
  PIN wq[388]
    DIRECTION INPUT ;
    USE SIGNAL ;
    PORT
      LAYER M5 ;
        RECT  58.848 103.916 58.872 104 ;
    END
  END wq[388]
  PIN wq[389]
    DIRECTION INPUT ;
    USE SIGNAL ;
    PORT
      LAYER M5 ;
        RECT  58.896 103.916 58.92 104 ;
    END
  END wq[389]
  PIN wq[38]
    DIRECTION INPUT ;
    USE SIGNAL ;
    PORT
      LAYER M5 ;
        RECT  42.048 103.916 42.072 104 ;
    END
  END wq[38]
  PIN wq[390]
    DIRECTION INPUT ;
    USE SIGNAL ;
    PORT
      LAYER M5 ;
        RECT  58.944 103.916 58.968 104 ;
    END
  END wq[390]
  PIN wq[391]
    DIRECTION INPUT ;
    USE SIGNAL ;
    PORT
      LAYER M5 ;
        RECT  58.992 103.916 59.016 104 ;
    END
  END wq[391]
  PIN wq[392]
    DIRECTION INPUT ;
    USE SIGNAL ;
    PORT
      LAYER M5 ;
        RECT  59.04 103.916 59.064 104 ;
    END
  END wq[392]
  PIN wq[393]
    DIRECTION INPUT ;
    USE SIGNAL ;
    PORT
      LAYER M5 ;
        RECT  59.088 103.916 59.112 104 ;
    END
  END wq[393]
  PIN wq[394]
    DIRECTION INPUT ;
    USE SIGNAL ;
    PORT
      LAYER M5 ;
        RECT  59.136 103.916 59.16 104 ;
    END
  END wq[394]
  PIN wq[395]
    DIRECTION INPUT ;
    USE SIGNAL ;
    PORT
      LAYER M5 ;
        RECT  59.184 103.916 59.208 104 ;
    END
  END wq[395]
  PIN wq[396]
    DIRECTION INPUT ;
    USE SIGNAL ;
    PORT
      LAYER M5 ;
        RECT  59.232 103.916 59.256 104 ;
    END
  END wq[396]
  PIN wq[397]
    DIRECTION INPUT ;
    USE SIGNAL ;
    PORT
      LAYER M5 ;
        RECT  59.28 103.916 59.304 104 ;
    END
  END wq[397]
  PIN wq[398]
    DIRECTION INPUT ;
    USE SIGNAL ;
    PORT
      LAYER M5 ;
        RECT  59.328 103.916 59.352 104 ;
    END
  END wq[398]
  PIN wq[399]
    DIRECTION INPUT ;
    USE SIGNAL ;
    PORT
      LAYER M5 ;
        RECT  59.376 103.916 59.4 104 ;
    END
  END wq[399]
  PIN wq[39]
    DIRECTION INPUT ;
    USE SIGNAL ;
    PORT
      LAYER M5 ;
        RECT  42.096 103.916 42.12 104 ;
    END
  END wq[39]
  PIN wq[3]
    DIRECTION INPUT ;
    USE SIGNAL ;
    PORT
      LAYER M5 ;
        RECT  40.368 103.916 40.392 104 ;
    END
  END wq[3]
  PIN wq[400]
    DIRECTION INPUT ;
    USE SIGNAL ;
    PORT
      LAYER M5 ;
        RECT  59.424 103.916 59.448 104 ;
    END
  END wq[400]
  PIN wq[401]
    DIRECTION INPUT ;
    USE SIGNAL ;
    PORT
      LAYER M5 ;
        RECT  59.472 103.916 59.496 104 ;
    END
  END wq[401]
  PIN wq[402]
    DIRECTION INPUT ;
    USE SIGNAL ;
    PORT
      LAYER M5 ;
        RECT  59.52 103.916 59.544 104 ;
    END
  END wq[402]
  PIN wq[403]
    DIRECTION INPUT ;
    USE SIGNAL ;
    PORT
      LAYER M5 ;
        RECT  59.568 103.916 59.592 104 ;
    END
  END wq[403]
  PIN wq[404]
    DIRECTION INPUT ;
    USE SIGNAL ;
    PORT
      LAYER M5 ;
        RECT  59.616 103.916 59.64 104 ;
    END
  END wq[404]
  PIN wq[405]
    DIRECTION INPUT ;
    USE SIGNAL ;
    PORT
      LAYER M5 ;
        RECT  59.664 103.916 59.688 104 ;
    END
  END wq[405]
  PIN wq[406]
    DIRECTION INPUT ;
    USE SIGNAL ;
    PORT
      LAYER M5 ;
        RECT  59.712 103.916 59.736 104 ;
    END
  END wq[406]
  PIN wq[407]
    DIRECTION INPUT ;
    USE SIGNAL ;
    PORT
      LAYER M5 ;
        RECT  59.76 103.916 59.784 104 ;
    END
  END wq[407]
  PIN wq[408]
    DIRECTION INPUT ;
    USE SIGNAL ;
    PORT
      LAYER M5 ;
        RECT  59.808 103.916 59.832 104 ;
    END
  END wq[408]
  PIN wq[409]
    DIRECTION INPUT ;
    USE SIGNAL ;
    PORT
      LAYER M5 ;
        RECT  59.856 103.916 59.88 104 ;
    END
  END wq[409]
  PIN wq[40]
    DIRECTION INPUT ;
    USE SIGNAL ;
    PORT
      LAYER M5 ;
        RECT  42.144 103.916 42.168 104 ;
    END
  END wq[40]
  PIN wq[410]
    DIRECTION INPUT ;
    USE SIGNAL ;
    PORT
      LAYER M5 ;
        RECT  59.904 103.916 59.928 104 ;
    END
  END wq[410]
  PIN wq[411]
    DIRECTION INPUT ;
    USE SIGNAL ;
    PORT
      LAYER M5 ;
        RECT  59.952 103.916 59.976 104 ;
    END
  END wq[411]
  PIN wq[412]
    DIRECTION INPUT ;
    USE SIGNAL ;
    PORT
      LAYER M5 ;
        RECT  60 103.916 60.024 104 ;
    END
  END wq[412]
  PIN wq[413]
    DIRECTION INPUT ;
    USE SIGNAL ;
    PORT
      LAYER M5 ;
        RECT  60.048 103.916 60.072 104 ;
    END
  END wq[413]
  PIN wq[414]
    DIRECTION INPUT ;
    USE SIGNAL ;
    PORT
      LAYER M5 ;
        RECT  60.096 103.916 60.12 104 ;
    END
  END wq[414]
  PIN wq[415]
    DIRECTION INPUT ;
    USE SIGNAL ;
    PORT
      LAYER M5 ;
        RECT  60.144 103.916 60.168 104 ;
    END
  END wq[415]
  PIN wq[416]
    DIRECTION INPUT ;
    USE SIGNAL ;
    PORT
      LAYER M5 ;
        RECT  60.192 103.916 60.216 104 ;
    END
  END wq[416]
  PIN wq[417]
    DIRECTION INPUT ;
    USE SIGNAL ;
    PORT
      LAYER M5 ;
        RECT  60.24 103.916 60.264 104 ;
    END
  END wq[417]
  PIN wq[418]
    DIRECTION INPUT ;
    USE SIGNAL ;
    PORT
      LAYER M5 ;
        RECT  60.288 103.916 60.312 104 ;
    END
  END wq[418]
  PIN wq[419]
    DIRECTION INPUT ;
    USE SIGNAL ;
    PORT
      LAYER M5 ;
        RECT  60.336 103.916 60.36 104 ;
    END
  END wq[419]
  PIN wq[41]
    DIRECTION INPUT ;
    USE SIGNAL ;
    PORT
      LAYER M5 ;
        RECT  42.192 103.916 42.216 104 ;
    END
  END wq[41]
  PIN wq[420]
    DIRECTION INPUT ;
    USE SIGNAL ;
    PORT
      LAYER M5 ;
        RECT  60.384 103.916 60.408 104 ;
    END
  END wq[420]
  PIN wq[421]
    DIRECTION INPUT ;
    USE SIGNAL ;
    PORT
      LAYER M5 ;
        RECT  60.432 103.916 60.456 104 ;
    END
  END wq[421]
  PIN wq[422]
    DIRECTION INPUT ;
    USE SIGNAL ;
    PORT
      LAYER M5 ;
        RECT  60.48 103.916 60.504 104 ;
    END
  END wq[422]
  PIN wq[423]
    DIRECTION INPUT ;
    USE SIGNAL ;
    PORT
      LAYER M5 ;
        RECT  60.528 103.916 60.552 104 ;
    END
  END wq[423]
  PIN wq[424]
    DIRECTION INPUT ;
    USE SIGNAL ;
    PORT
      LAYER M5 ;
        RECT  60.576 103.916 60.6 104 ;
    END
  END wq[424]
  PIN wq[425]
    DIRECTION INPUT ;
    USE SIGNAL ;
    PORT
      LAYER M5 ;
        RECT  60.624 103.916 60.648 104 ;
    END
  END wq[425]
  PIN wq[426]
    DIRECTION INPUT ;
    USE SIGNAL ;
    PORT
      LAYER M5 ;
        RECT  60.672 103.916 60.696 104 ;
    END
  END wq[426]
  PIN wq[427]
    DIRECTION INPUT ;
    USE SIGNAL ;
    PORT
      LAYER M5 ;
        RECT  60.72 103.916 60.744 104 ;
    END
  END wq[427]
  PIN wq[428]
    DIRECTION INPUT ;
    USE SIGNAL ;
    PORT
      LAYER M5 ;
        RECT  60.768 103.916 60.792 104 ;
    END
  END wq[428]
  PIN wq[429]
    DIRECTION INPUT ;
    USE SIGNAL ;
    PORT
      LAYER M5 ;
        RECT  60.816 103.916 60.84 104 ;
    END
  END wq[429]
  PIN wq[42]
    DIRECTION INPUT ;
    USE SIGNAL ;
    PORT
      LAYER M5 ;
        RECT  42.24 103.916 42.264 104 ;
    END
  END wq[42]
  PIN wq[430]
    DIRECTION INPUT ;
    USE SIGNAL ;
    PORT
      LAYER M5 ;
        RECT  60.864 103.916 60.888 104 ;
    END
  END wq[430]
  PIN wq[431]
    DIRECTION INPUT ;
    USE SIGNAL ;
    PORT
      LAYER M5 ;
        RECT  60.912 103.916 60.936 104 ;
    END
  END wq[431]
  PIN wq[432]
    DIRECTION INPUT ;
    USE SIGNAL ;
    PORT
      LAYER M5 ;
        RECT  60.96 103.916 60.984 104 ;
    END
  END wq[432]
  PIN wq[433]
    DIRECTION INPUT ;
    USE SIGNAL ;
    PORT
      LAYER M5 ;
        RECT  61.008 103.916 61.032 104 ;
    END
  END wq[433]
  PIN wq[434]
    DIRECTION INPUT ;
    USE SIGNAL ;
    PORT
      LAYER M5 ;
        RECT  61.056 103.916 61.08 104 ;
    END
  END wq[434]
  PIN wq[435]
    DIRECTION INPUT ;
    USE SIGNAL ;
    PORT
      LAYER M5 ;
        RECT  61.104 103.916 61.128 104 ;
    END
  END wq[435]
  PIN wq[436]
    DIRECTION INPUT ;
    USE SIGNAL ;
    PORT
      LAYER M5 ;
        RECT  61.152 103.916 61.176 104 ;
    END
  END wq[436]
  PIN wq[437]
    DIRECTION INPUT ;
    USE SIGNAL ;
    PORT
      LAYER M5 ;
        RECT  61.2 103.916 61.224 104 ;
    END
  END wq[437]
  PIN wq[438]
    DIRECTION INPUT ;
    USE SIGNAL ;
    PORT
      LAYER M5 ;
        RECT  61.248 103.916 61.272 104 ;
    END
  END wq[438]
  PIN wq[439]
    DIRECTION INPUT ;
    USE SIGNAL ;
    PORT
      LAYER M5 ;
        RECT  61.296 103.916 61.32 104 ;
    END
  END wq[439]
  PIN wq[43]
    DIRECTION INPUT ;
    USE SIGNAL ;
    PORT
      LAYER M5 ;
        RECT  42.288 103.916 42.312 104 ;
    END
  END wq[43]
  PIN wq[440]
    DIRECTION INPUT ;
    USE SIGNAL ;
    PORT
      LAYER M5 ;
        RECT  61.344 103.916 61.368 104 ;
    END
  END wq[440]
  PIN wq[441]
    DIRECTION INPUT ;
    USE SIGNAL ;
    PORT
      LAYER M5 ;
        RECT  61.392 103.916 61.416 104 ;
    END
  END wq[441]
  PIN wq[442]
    DIRECTION INPUT ;
    USE SIGNAL ;
    PORT
      LAYER M5 ;
        RECT  61.44 103.916 61.464 104 ;
    END
  END wq[442]
  PIN wq[443]
    DIRECTION INPUT ;
    USE SIGNAL ;
    PORT
      LAYER M5 ;
        RECT  61.488 103.916 61.512 104 ;
    END
  END wq[443]
  PIN wq[444]
    DIRECTION INPUT ;
    USE SIGNAL ;
    PORT
      LAYER M5 ;
        RECT  61.536 103.916 61.56 104 ;
    END
  END wq[444]
  PIN wq[445]
    DIRECTION INPUT ;
    USE SIGNAL ;
    PORT
      LAYER M5 ;
        RECT  61.584 103.916 61.608 104 ;
    END
  END wq[445]
  PIN wq[446]
    DIRECTION INPUT ;
    USE SIGNAL ;
    PORT
      LAYER M5 ;
        RECT  61.632 103.916 61.656 104 ;
    END
  END wq[446]
  PIN wq[447]
    DIRECTION INPUT ;
    USE SIGNAL ;
    PORT
      LAYER M5 ;
        RECT  61.68 103.916 61.704 104 ;
    END
  END wq[447]
  PIN wq[448]
    DIRECTION INPUT ;
    USE SIGNAL ;
    PORT
      LAYER M5 ;
        RECT  61.728 103.916 61.752 104 ;
    END
  END wq[448]
  PIN wq[449]
    DIRECTION INPUT ;
    USE SIGNAL ;
    PORT
      LAYER M5 ;
        RECT  61.776 103.916 61.8 104 ;
    END
  END wq[449]
  PIN wq[44]
    DIRECTION INPUT ;
    USE SIGNAL ;
    PORT
      LAYER M5 ;
        RECT  42.336 103.916 42.36 104 ;
    END
  END wq[44]
  PIN wq[450]
    DIRECTION INPUT ;
    USE SIGNAL ;
    PORT
      LAYER M5 ;
        RECT  61.824 103.916 61.848 104 ;
    END
  END wq[450]
  PIN wq[451]
    DIRECTION INPUT ;
    USE SIGNAL ;
    PORT
      LAYER M5 ;
        RECT  61.872 103.916 61.896 104 ;
    END
  END wq[451]
  PIN wq[452]
    DIRECTION INPUT ;
    USE SIGNAL ;
    PORT
      LAYER M5 ;
        RECT  61.92 103.916 61.944 104 ;
    END
  END wq[452]
  PIN wq[453]
    DIRECTION INPUT ;
    USE SIGNAL ;
    PORT
      LAYER M5 ;
        RECT  61.968 103.916 61.992 104 ;
    END
  END wq[453]
  PIN wq[454]
    DIRECTION INPUT ;
    USE SIGNAL ;
    PORT
      LAYER M5 ;
        RECT  62.016 103.916 62.04 104 ;
    END
  END wq[454]
  PIN wq[455]
    DIRECTION INPUT ;
    USE SIGNAL ;
    PORT
      LAYER M5 ;
        RECT  62.064 103.916 62.088 104 ;
    END
  END wq[455]
  PIN wq[456]
    DIRECTION INPUT ;
    USE SIGNAL ;
    PORT
      LAYER M5 ;
        RECT  62.112 103.916 62.136 104 ;
    END
  END wq[456]
  PIN wq[457]
    DIRECTION INPUT ;
    USE SIGNAL ;
    PORT
      LAYER M5 ;
        RECT  62.16 103.916 62.184 104 ;
    END
  END wq[457]
  PIN wq[458]
    DIRECTION INPUT ;
    USE SIGNAL ;
    PORT
      LAYER M5 ;
        RECT  62.208 103.916 62.232 104 ;
    END
  END wq[458]
  PIN wq[459]
    DIRECTION INPUT ;
    USE SIGNAL ;
    PORT
      LAYER M5 ;
        RECT  62.256 103.916 62.28 104 ;
    END
  END wq[459]
  PIN wq[45]
    DIRECTION INPUT ;
    USE SIGNAL ;
    PORT
      LAYER M5 ;
        RECT  42.384 103.916 42.408 104 ;
    END
  END wq[45]
  PIN wq[460]
    DIRECTION INPUT ;
    USE SIGNAL ;
    PORT
      LAYER M5 ;
        RECT  62.304 103.916 62.328 104 ;
    END
  END wq[460]
  PIN wq[461]
    DIRECTION INPUT ;
    USE SIGNAL ;
    PORT
      LAYER M5 ;
        RECT  62.352 103.916 62.376 104 ;
    END
  END wq[461]
  PIN wq[462]
    DIRECTION INPUT ;
    USE SIGNAL ;
    PORT
      LAYER M5 ;
        RECT  62.4 103.916 62.424 104 ;
    END
  END wq[462]
  PIN wq[463]
    DIRECTION INPUT ;
    USE SIGNAL ;
    PORT
      LAYER M5 ;
        RECT  62.448 103.916 62.472 104 ;
    END
  END wq[463]
  PIN wq[464]
    DIRECTION INPUT ;
    USE SIGNAL ;
    PORT
      LAYER M5 ;
        RECT  62.496 103.916 62.52 104 ;
    END
  END wq[464]
  PIN wq[465]
    DIRECTION INPUT ;
    USE SIGNAL ;
    PORT
      LAYER M5 ;
        RECT  62.544 103.916 62.568 104 ;
    END
  END wq[465]
  PIN wq[466]
    DIRECTION INPUT ;
    USE SIGNAL ;
    PORT
      LAYER M5 ;
        RECT  62.592 103.916 62.616 104 ;
    END
  END wq[466]
  PIN wq[467]
    DIRECTION INPUT ;
    USE SIGNAL ;
    PORT
      LAYER M5 ;
        RECT  62.64 103.916 62.664 104 ;
    END
  END wq[467]
  PIN wq[468]
    DIRECTION INPUT ;
    USE SIGNAL ;
    PORT
      LAYER M5 ;
        RECT  62.688 103.916 62.712 104 ;
    END
  END wq[468]
  PIN wq[469]
    DIRECTION INPUT ;
    USE SIGNAL ;
    PORT
      LAYER M5 ;
        RECT  62.736 103.916 62.76 104 ;
    END
  END wq[469]
  PIN wq[46]
    DIRECTION INPUT ;
    USE SIGNAL ;
    PORT
      LAYER M5 ;
        RECT  42.432 103.916 42.456 104 ;
    END
  END wq[46]
  PIN wq[470]
    DIRECTION INPUT ;
    USE SIGNAL ;
    PORT
      LAYER M5 ;
        RECT  62.784 103.916 62.808 104 ;
    END
  END wq[470]
  PIN wq[471]
    DIRECTION INPUT ;
    USE SIGNAL ;
    PORT
      LAYER M5 ;
        RECT  62.832 103.916 62.856 104 ;
    END
  END wq[471]
  PIN wq[472]
    DIRECTION INPUT ;
    USE SIGNAL ;
    PORT
      LAYER M5 ;
        RECT  62.88 103.916 62.904 104 ;
    END
  END wq[472]
  PIN wq[473]
    DIRECTION INPUT ;
    USE SIGNAL ;
    PORT
      LAYER M5 ;
        RECT  62.928 103.916 62.952 104 ;
    END
  END wq[473]
  PIN wq[474]
    DIRECTION INPUT ;
    USE SIGNAL ;
    PORT
      LAYER M5 ;
        RECT  62.976 103.916 63 104 ;
    END
  END wq[474]
  PIN wq[475]
    DIRECTION INPUT ;
    USE SIGNAL ;
    PORT
      LAYER M5 ;
        RECT  63.024 103.916 63.048 104 ;
    END
  END wq[475]
  PIN wq[476]
    DIRECTION INPUT ;
    USE SIGNAL ;
    PORT
      LAYER M5 ;
        RECT  63.072 103.916 63.096 104 ;
    END
  END wq[476]
  PIN wq[477]
    DIRECTION INPUT ;
    USE SIGNAL ;
    PORT
      LAYER M5 ;
        RECT  63.12 103.916 63.144 104 ;
    END
  END wq[477]
  PIN wq[478]
    DIRECTION INPUT ;
    USE SIGNAL ;
    PORT
      LAYER M5 ;
        RECT  63.168 103.916 63.192 104 ;
    END
  END wq[478]
  PIN wq[479]
    DIRECTION INPUT ;
    USE SIGNAL ;
    PORT
      LAYER M5 ;
        RECT  63.216 103.916 63.24 104 ;
    END
  END wq[479]
  PIN wq[47]
    DIRECTION INPUT ;
    USE SIGNAL ;
    PORT
      LAYER M5 ;
        RECT  42.48 103.916 42.504 104 ;
    END
  END wq[47]
  PIN wq[480]
    DIRECTION INPUT ;
    USE SIGNAL ;
    PORT
      LAYER M5 ;
        RECT  63.264 103.916 63.288 104 ;
    END
  END wq[480]
  PIN wq[481]
    DIRECTION INPUT ;
    USE SIGNAL ;
    PORT
      LAYER M5 ;
        RECT  63.312 103.916 63.336 104 ;
    END
  END wq[481]
  PIN wq[482]
    DIRECTION INPUT ;
    USE SIGNAL ;
    PORT
      LAYER M5 ;
        RECT  63.36 103.916 63.384 104 ;
    END
  END wq[482]
  PIN wq[483]
    DIRECTION INPUT ;
    USE SIGNAL ;
    PORT
      LAYER M5 ;
        RECT  63.408 103.916 63.432 104 ;
    END
  END wq[483]
  PIN wq[484]
    DIRECTION INPUT ;
    USE SIGNAL ;
    PORT
      LAYER M5 ;
        RECT  63.456 103.916 63.48 104 ;
    END
  END wq[484]
  PIN wq[485]
    DIRECTION INPUT ;
    USE SIGNAL ;
    PORT
      LAYER M5 ;
        RECT  63.504 103.916 63.528 104 ;
    END
  END wq[485]
  PIN wq[486]
    DIRECTION INPUT ;
    USE SIGNAL ;
    PORT
      LAYER M5 ;
        RECT  63.552 103.916 63.576 104 ;
    END
  END wq[486]
  PIN wq[487]
    DIRECTION INPUT ;
    USE SIGNAL ;
    PORT
      LAYER M5 ;
        RECT  63.6 103.916 63.624 104 ;
    END
  END wq[487]
  PIN wq[488]
    DIRECTION INPUT ;
    USE SIGNAL ;
    PORT
      LAYER M5 ;
        RECT  63.648 103.916 63.672 104 ;
    END
  END wq[488]
  PIN wq[489]
    DIRECTION INPUT ;
    USE SIGNAL ;
    PORT
      LAYER M5 ;
        RECT  63.696 103.916 63.72 104 ;
    END
  END wq[489]
  PIN wq[48]
    DIRECTION INPUT ;
    USE SIGNAL ;
    PORT
      LAYER M5 ;
        RECT  42.528 103.916 42.552 104 ;
    END
  END wq[48]
  PIN wq[490]
    DIRECTION INPUT ;
    USE SIGNAL ;
    PORT
      LAYER M5 ;
        RECT  63.744 103.916 63.768 104 ;
    END
  END wq[490]
  PIN wq[491]
    DIRECTION INPUT ;
    USE SIGNAL ;
    PORT
      LAYER M5 ;
        RECT  63.792 103.916 63.816 104 ;
    END
  END wq[491]
  PIN wq[492]
    DIRECTION INPUT ;
    USE SIGNAL ;
    PORT
      LAYER M5 ;
        RECT  63.84 103.916 63.864 104 ;
    END
  END wq[492]
  PIN wq[493]
    DIRECTION INPUT ;
    USE SIGNAL ;
    PORT
      LAYER M5 ;
        RECT  63.888 103.916 63.912 104 ;
    END
  END wq[493]
  PIN wq[494]
    DIRECTION INPUT ;
    USE SIGNAL ;
    PORT
      LAYER M5 ;
        RECT  63.936 103.916 63.96 104 ;
    END
  END wq[494]
  PIN wq[495]
    DIRECTION INPUT ;
    USE SIGNAL ;
    PORT
      LAYER M5 ;
        RECT  63.984 103.916 64.008 104 ;
    END
  END wq[495]
  PIN wq[496]
    DIRECTION INPUT ;
    USE SIGNAL ;
    PORT
      LAYER M5 ;
        RECT  64.032 103.916 64.056 104 ;
    END
  END wq[496]
  PIN wq[497]
    DIRECTION INPUT ;
    USE SIGNAL ;
    PORT
      LAYER M5 ;
        RECT  64.08 103.916 64.104 104 ;
    END
  END wq[497]
  PIN wq[498]
    DIRECTION INPUT ;
    USE SIGNAL ;
    PORT
      LAYER M5 ;
        RECT  64.128 103.916 64.152 104 ;
    END
  END wq[498]
  PIN wq[499]
    DIRECTION INPUT ;
    USE SIGNAL ;
    PORT
      LAYER M5 ;
        RECT  64.176 103.916 64.2 104 ;
    END
  END wq[499]
  PIN wq[49]
    DIRECTION INPUT ;
    USE SIGNAL ;
    PORT
      LAYER M5 ;
        RECT  42.576 103.916 42.6 104 ;
    END
  END wq[49]
  PIN wq[4]
    DIRECTION INPUT ;
    USE SIGNAL ;
    PORT
      LAYER M5 ;
        RECT  40.416 103.916 40.44 104 ;
    END
  END wq[4]
  PIN wq[500]
    DIRECTION INPUT ;
    USE SIGNAL ;
    PORT
      LAYER M5 ;
        RECT  64.224 103.916 64.248 104 ;
    END
  END wq[500]
  PIN wq[501]
    DIRECTION INPUT ;
    USE SIGNAL ;
    PORT
      LAYER M5 ;
        RECT  64.272 103.916 64.296 104 ;
    END
  END wq[501]
  PIN wq[502]
    DIRECTION INPUT ;
    USE SIGNAL ;
    PORT
      LAYER M5 ;
        RECT  64.32 103.916 64.344 104 ;
    END
  END wq[502]
  PIN wq[503]
    DIRECTION INPUT ;
    USE SIGNAL ;
    PORT
      LAYER M5 ;
        RECT  64.368 103.916 64.392 104 ;
    END
  END wq[503]
  PIN wq[504]
    DIRECTION INPUT ;
    USE SIGNAL ;
    PORT
      LAYER M5 ;
        RECT  64.416 103.916 64.44 104 ;
    END
  END wq[504]
  PIN wq[505]
    DIRECTION INPUT ;
    USE SIGNAL ;
    PORT
      LAYER M5 ;
        RECT  64.464 103.916 64.488 104 ;
    END
  END wq[505]
  PIN wq[506]
    DIRECTION INPUT ;
    USE SIGNAL ;
    PORT
      LAYER M5 ;
        RECT  64.512 103.916 64.536 104 ;
    END
  END wq[506]
  PIN wq[507]
    DIRECTION INPUT ;
    USE SIGNAL ;
    PORT
      LAYER M5 ;
        RECT  64.56 103.916 64.584 104 ;
    END
  END wq[507]
  PIN wq[508]
    DIRECTION INPUT ;
    USE SIGNAL ;
    PORT
      LAYER M5 ;
        RECT  64.608 103.916 64.632 104 ;
    END
  END wq[508]
  PIN wq[509]
    DIRECTION INPUT ;
    USE SIGNAL ;
    PORT
      LAYER M5 ;
        RECT  64.656 103.916 64.68 104 ;
    END
  END wq[509]
  PIN wq[50]
    DIRECTION INPUT ;
    USE SIGNAL ;
    PORT
      LAYER M5 ;
        RECT  42.624 103.916 42.648 104 ;
    END
  END wq[50]
  PIN wq[510]
    DIRECTION INPUT ;
    USE SIGNAL ;
    PORT
      LAYER M5 ;
        RECT  64.704 103.916 64.728 104 ;
    END
  END wq[510]
  PIN wq[511]
    DIRECTION INPUT ;
    USE SIGNAL ;
    PORT
      LAYER M5 ;
        RECT  64.752 103.916 64.776 104 ;
    END
  END wq[511]
  PIN wq[51]
    DIRECTION INPUT ;
    USE SIGNAL ;
    PORT
      LAYER M5 ;
        RECT  42.672 103.916 42.696 104 ;
    END
  END wq[51]
  PIN wq[52]
    DIRECTION INPUT ;
    USE SIGNAL ;
    PORT
      LAYER M5 ;
        RECT  42.72 103.916 42.744 104 ;
    END
  END wq[52]
  PIN wq[53]
    DIRECTION INPUT ;
    USE SIGNAL ;
    PORT
      LAYER M5 ;
        RECT  42.768 103.916 42.792 104 ;
    END
  END wq[53]
  PIN wq[54]
    DIRECTION INPUT ;
    USE SIGNAL ;
    PORT
      LAYER M5 ;
        RECT  42.816 103.916 42.84 104 ;
    END
  END wq[54]
  PIN wq[55]
    DIRECTION INPUT ;
    USE SIGNAL ;
    PORT
      LAYER M5 ;
        RECT  42.864 103.916 42.888 104 ;
    END
  END wq[55]
  PIN wq[56]
    DIRECTION INPUT ;
    USE SIGNAL ;
    PORT
      LAYER M5 ;
        RECT  42.912 103.916 42.936 104 ;
    END
  END wq[56]
  PIN wq[57]
    DIRECTION INPUT ;
    USE SIGNAL ;
    PORT
      LAYER M5 ;
        RECT  42.96 103.916 42.984 104 ;
    END
  END wq[57]
  PIN wq[58]
    DIRECTION INPUT ;
    USE SIGNAL ;
    PORT
      LAYER M5 ;
        RECT  43.008 103.916 43.032 104 ;
    END
  END wq[58]
  PIN wq[59]
    DIRECTION INPUT ;
    USE SIGNAL ;
    PORT
      LAYER M5 ;
        RECT  43.056 103.916 43.08 104 ;
    END
  END wq[59]
  PIN wq[5]
    DIRECTION INPUT ;
    USE SIGNAL ;
    PORT
      LAYER M5 ;
        RECT  40.464 103.916 40.488 104 ;
    END
  END wq[5]
  PIN wq[60]
    DIRECTION INPUT ;
    USE SIGNAL ;
    PORT
      LAYER M5 ;
        RECT  43.104 103.916 43.128 104 ;
    END
  END wq[60]
  PIN wq[61]
    DIRECTION INPUT ;
    USE SIGNAL ;
    PORT
      LAYER M5 ;
        RECT  43.152 103.916 43.176 104 ;
    END
  END wq[61]
  PIN wq[62]
    DIRECTION INPUT ;
    USE SIGNAL ;
    PORT
      LAYER M5 ;
        RECT  43.2 103.916 43.224 104 ;
    END
  END wq[62]
  PIN wq[63]
    DIRECTION INPUT ;
    USE SIGNAL ;
    PORT
      LAYER M5 ;
        RECT  43.248 103.916 43.272 104 ;
    END
  END wq[63]
  PIN wq[64]
    DIRECTION INPUT ;
    USE SIGNAL ;
    PORT
      LAYER M5 ;
        RECT  43.296 103.916 43.32 104 ;
    END
  END wq[64]
  PIN wq[65]
    DIRECTION INPUT ;
    USE SIGNAL ;
    PORT
      LAYER M5 ;
        RECT  43.344 103.916 43.368 104 ;
    END
  END wq[65]
  PIN wq[66]
    DIRECTION INPUT ;
    USE SIGNAL ;
    PORT
      LAYER M5 ;
        RECT  43.392 103.916 43.416 104 ;
    END
  END wq[66]
  PIN wq[67]
    DIRECTION INPUT ;
    USE SIGNAL ;
    PORT
      LAYER M5 ;
        RECT  43.44 103.916 43.464 104 ;
    END
  END wq[67]
  PIN wq[68]
    DIRECTION INPUT ;
    USE SIGNAL ;
    PORT
      LAYER M5 ;
        RECT  43.488 103.916 43.512 104 ;
    END
  END wq[68]
  PIN wq[69]
    DIRECTION INPUT ;
    USE SIGNAL ;
    PORT
      LAYER M5 ;
        RECT  43.536 103.916 43.56 104 ;
    END
  END wq[69]
  PIN wq[6]
    DIRECTION INPUT ;
    USE SIGNAL ;
    PORT
      LAYER M5 ;
        RECT  40.512 103.916 40.536 104 ;
    END
  END wq[6]
  PIN wq[70]
    DIRECTION INPUT ;
    USE SIGNAL ;
    PORT
      LAYER M5 ;
        RECT  43.584 103.916 43.608 104 ;
    END
  END wq[70]
  PIN wq[71]
    DIRECTION INPUT ;
    USE SIGNAL ;
    PORT
      LAYER M5 ;
        RECT  43.632 103.916 43.656 104 ;
    END
  END wq[71]
  PIN wq[72]
    DIRECTION INPUT ;
    USE SIGNAL ;
    PORT
      LAYER M5 ;
        RECT  43.68 103.916 43.704 104 ;
    END
  END wq[72]
  PIN wq[73]
    DIRECTION INPUT ;
    USE SIGNAL ;
    PORT
      LAYER M5 ;
        RECT  43.728 103.916 43.752 104 ;
    END
  END wq[73]
  PIN wq[74]
    DIRECTION INPUT ;
    USE SIGNAL ;
    PORT
      LAYER M5 ;
        RECT  43.776 103.916 43.8 104 ;
    END
  END wq[74]
  PIN wq[75]
    DIRECTION INPUT ;
    USE SIGNAL ;
    PORT
      LAYER M5 ;
        RECT  43.824 103.916 43.848 104 ;
    END
  END wq[75]
  PIN wq[76]
    DIRECTION INPUT ;
    USE SIGNAL ;
    PORT
      LAYER M5 ;
        RECT  43.872 103.916 43.896 104 ;
    END
  END wq[76]
  PIN wq[77]
    DIRECTION INPUT ;
    USE SIGNAL ;
    PORT
      LAYER M5 ;
        RECT  43.92 103.916 43.944 104 ;
    END
  END wq[77]
  PIN wq[78]
    DIRECTION INPUT ;
    USE SIGNAL ;
    PORT
      LAYER M5 ;
        RECT  43.968 103.916 43.992 104 ;
    END
  END wq[78]
  PIN wq[79]
    DIRECTION INPUT ;
    USE SIGNAL ;
    PORT
      LAYER M5 ;
        RECT  44.016 103.916 44.04 104 ;
    END
  END wq[79]
  PIN wq[7]
    DIRECTION INPUT ;
    USE SIGNAL ;
    PORT
      LAYER M5 ;
        RECT  40.56 103.916 40.584 104 ;
    END
  END wq[7]
  PIN wq[80]
    DIRECTION INPUT ;
    USE SIGNAL ;
    PORT
      LAYER M5 ;
        RECT  44.064 103.916 44.088 104 ;
    END
  END wq[80]
  PIN wq[81]
    DIRECTION INPUT ;
    USE SIGNAL ;
    PORT
      LAYER M5 ;
        RECT  44.112 103.916 44.136 104 ;
    END
  END wq[81]
  PIN wq[82]
    DIRECTION INPUT ;
    USE SIGNAL ;
    PORT
      LAYER M5 ;
        RECT  44.16 103.916 44.184 104 ;
    END
  END wq[82]
  PIN wq[83]
    DIRECTION INPUT ;
    USE SIGNAL ;
    PORT
      LAYER M5 ;
        RECT  44.208 103.916 44.232 104 ;
    END
  END wq[83]
  PIN wq[84]
    DIRECTION INPUT ;
    USE SIGNAL ;
    PORT
      LAYER M5 ;
        RECT  44.256 103.916 44.28 104 ;
    END
  END wq[84]
  PIN wq[85]
    DIRECTION INPUT ;
    USE SIGNAL ;
    PORT
      LAYER M5 ;
        RECT  44.304 103.916 44.328 104 ;
    END
  END wq[85]
  PIN wq[86]
    DIRECTION INPUT ;
    USE SIGNAL ;
    PORT
      LAYER M5 ;
        RECT  44.352 103.916 44.376 104 ;
    END
  END wq[86]
  PIN wq[87]
    DIRECTION INPUT ;
    USE SIGNAL ;
    PORT
      LAYER M5 ;
        RECT  44.4 103.916 44.424 104 ;
    END
  END wq[87]
  PIN wq[88]
    DIRECTION INPUT ;
    USE SIGNAL ;
    PORT
      LAYER M5 ;
        RECT  44.448 103.916 44.472 104 ;
    END
  END wq[88]
  PIN wq[89]
    DIRECTION INPUT ;
    USE SIGNAL ;
    PORT
      LAYER M5 ;
        RECT  44.496 103.916 44.52 104 ;
    END
  END wq[89]
  PIN wq[8]
    DIRECTION INPUT ;
    USE SIGNAL ;
    PORT
      LAYER M5 ;
        RECT  40.608 103.916 40.632 104 ;
    END
  END wq[8]
  PIN wq[90]
    DIRECTION INPUT ;
    USE SIGNAL ;
    PORT
      LAYER M5 ;
        RECT  44.544 103.916 44.568 104 ;
    END
  END wq[90]
  PIN wq[91]
    DIRECTION INPUT ;
    USE SIGNAL ;
    PORT
      LAYER M5 ;
        RECT  44.592 103.916 44.616 104 ;
    END
  END wq[91]
  PIN wq[92]
    DIRECTION INPUT ;
    USE SIGNAL ;
    PORT
      LAYER M5 ;
        RECT  44.64 103.916 44.664 104 ;
    END
  END wq[92]
  PIN wq[93]
    DIRECTION INPUT ;
    USE SIGNAL ;
    PORT
      LAYER M5 ;
        RECT  44.688 103.916 44.712 104 ;
    END
  END wq[93]
  PIN wq[94]
    DIRECTION INPUT ;
    USE SIGNAL ;
    PORT
      LAYER M5 ;
        RECT  44.736 103.916 44.76 104 ;
    END
  END wq[94]
  PIN wq[95]
    DIRECTION INPUT ;
    USE SIGNAL ;
    PORT
      LAYER M5 ;
        RECT  44.784 103.916 44.808 104 ;
    END
  END wq[95]
  PIN wq[96]
    DIRECTION INPUT ;
    USE SIGNAL ;
    PORT
      LAYER M5 ;
        RECT  44.832 103.916 44.856 104 ;
    END
  END wq[96]
  PIN wq[97]
    DIRECTION INPUT ;
    USE SIGNAL ;
    PORT
      LAYER M5 ;
        RECT  44.88 103.916 44.904 104 ;
    END
  END wq[97]
  PIN wq[98]
    DIRECTION INPUT ;
    USE SIGNAL ;
    PORT
      LAYER M5 ;
        RECT  44.928 103.916 44.952 104 ;
    END
  END wq[98]
  PIN wq[99]
    DIRECTION INPUT ;
    USE SIGNAL ;
    PORT
      LAYER M5 ;
        RECT  44.976 103.916 45 104 ;
    END
  END wq[99]
  PIN wq[9]
    DIRECTION INPUT ;
    USE SIGNAL ;
    PORT
      LAYER M5 ;
        RECT  40.656 103.916 40.68 104 ;
    END
  END wq[9]
  PIN xe[0]
    DIRECTION INPUT ;
    USE SIGNAL ;
    PORT
      LAYER M4 ;
        RECT  0 39.264 0.084 39.288 ;
    END
  END xe[0]
  PIN xe[10]
    DIRECTION INPUT ;
    USE SIGNAL ;
    PORT
      LAYER M4 ;
        RECT  0 39.744 0.084 39.768 ;
    END
  END xe[10]
  PIN xe[11]
    DIRECTION INPUT ;
    USE SIGNAL ;
    PORT
      LAYER M4 ;
        RECT  0 39.792 0.084 39.816 ;
    END
  END xe[11]
  PIN xe[12]
    DIRECTION INPUT ;
    USE SIGNAL ;
    PORT
      LAYER M4 ;
        RECT  0 39.84 0.084 39.864 ;
    END
  END xe[12]
  PIN xe[13]
    DIRECTION INPUT ;
    USE SIGNAL ;
    PORT
      LAYER M4 ;
        RECT  0 39.888 0.084 39.912 ;
    END
  END xe[13]
  PIN xe[14]
    DIRECTION INPUT ;
    USE SIGNAL ;
    PORT
      LAYER M4 ;
        RECT  0 39.936 0.084 39.96 ;
    END
  END xe[14]
  PIN xe[15]
    DIRECTION INPUT ;
    USE SIGNAL ;
    PORT
      LAYER M4 ;
        RECT  0 39.984 0.084 40.008 ;
    END
  END xe[15]
  PIN xe[16]
    DIRECTION INPUT ;
    USE SIGNAL ;
    PORT
      LAYER M4 ;
        RECT  0 40.032 0.084 40.056 ;
    END
  END xe[16]
  PIN xe[17]
    DIRECTION INPUT ;
    USE SIGNAL ;
    PORT
      LAYER M4 ;
        RECT  0 40.08 0.084 40.104 ;
    END
  END xe[17]
  PIN xe[18]
    DIRECTION INPUT ;
    USE SIGNAL ;
    PORT
      LAYER M4 ;
        RECT  0 40.128 0.084 40.152 ;
    END
  END xe[18]
  PIN xe[19]
    DIRECTION INPUT ;
    USE SIGNAL ;
    PORT
      LAYER M4 ;
        RECT  0 40.176 0.084 40.2 ;
    END
  END xe[19]
  PIN xe[1]
    DIRECTION INPUT ;
    USE SIGNAL ;
    PORT
      LAYER M4 ;
        RECT  0 39.312 0.084 39.336 ;
    END
  END xe[1]
  PIN xe[2]
    DIRECTION INPUT ;
    USE SIGNAL ;
    PORT
      LAYER M4 ;
        RECT  0 39.36 0.084 39.384 ;
    END
  END xe[2]
  PIN xe[3]
    DIRECTION INPUT ;
    USE SIGNAL ;
    PORT
      LAYER M4 ;
        RECT  0 39.408 0.084 39.432 ;
    END
  END xe[3]
  PIN xe[4]
    DIRECTION INPUT ;
    USE SIGNAL ;
    PORT
      LAYER M4 ;
        RECT  0 39.456 0.084 39.48 ;
    END
  END xe[4]
  PIN xe[5]
    DIRECTION INPUT ;
    USE SIGNAL ;
    PORT
      LAYER M4 ;
        RECT  0 39.504 0.084 39.528 ;
    END
  END xe[5]
  PIN xe[6]
    DIRECTION INPUT ;
    USE SIGNAL ;
    PORT
      LAYER M4 ;
        RECT  0 39.552 0.084 39.576 ;
    END
  END xe[6]
  PIN xe[7]
    DIRECTION INPUT ;
    USE SIGNAL ;
    PORT
      LAYER M4 ;
        RECT  0 39.6 0.084 39.624 ;
    END
  END xe[7]
  PIN xe[8]
    DIRECTION INPUT ;
    USE SIGNAL ;
    PORT
      LAYER M4 ;
        RECT  0 39.648 0.084 39.672 ;
    END
  END xe[8]
  PIN xe[9]
    DIRECTION INPUT ;
    USE SIGNAL ;
    PORT
      LAYER M4 ;
        RECT  0 39.696 0.084 39.72 ;
    END
  END xe[9]
  PIN xq[0]
    DIRECTION INPUT ;
    USE SIGNAL ;
    PORT
      LAYER M4 ;
        RECT  0 40.224 0.084 40.248 ;
    END
  END xq[0]
  PIN xq[100]
    DIRECTION INPUT ;
    USE SIGNAL ;
    PORT
      LAYER M4 ;
        RECT  0 45.024 0.084 45.048 ;
    END
  END xq[100]
  PIN xq[101]
    DIRECTION INPUT ;
    USE SIGNAL ;
    PORT
      LAYER M4 ;
        RECT  0 45.072 0.084 45.096 ;
    END
  END xq[101]
  PIN xq[102]
    DIRECTION INPUT ;
    USE SIGNAL ;
    PORT
      LAYER M4 ;
        RECT  0 45.12 0.084 45.144 ;
    END
  END xq[102]
  PIN xq[103]
    DIRECTION INPUT ;
    USE SIGNAL ;
    PORT
      LAYER M4 ;
        RECT  0 45.168 0.084 45.192 ;
    END
  END xq[103]
  PIN xq[104]
    DIRECTION INPUT ;
    USE SIGNAL ;
    PORT
      LAYER M4 ;
        RECT  0 45.216 0.084 45.24 ;
    END
  END xq[104]
  PIN xq[105]
    DIRECTION INPUT ;
    USE SIGNAL ;
    PORT
      LAYER M4 ;
        RECT  0 45.264 0.084 45.288 ;
    END
  END xq[105]
  PIN xq[106]
    DIRECTION INPUT ;
    USE SIGNAL ;
    PORT
      LAYER M4 ;
        RECT  0 45.312 0.084 45.336 ;
    END
  END xq[106]
  PIN xq[107]
    DIRECTION INPUT ;
    USE SIGNAL ;
    PORT
      LAYER M4 ;
        RECT  0 45.36 0.084 45.384 ;
    END
  END xq[107]
  PIN xq[108]
    DIRECTION INPUT ;
    USE SIGNAL ;
    PORT
      LAYER M4 ;
        RECT  0 45.408 0.084 45.432 ;
    END
  END xq[108]
  PIN xq[109]
    DIRECTION INPUT ;
    USE SIGNAL ;
    PORT
      LAYER M4 ;
        RECT  0 45.456 0.084 45.48 ;
    END
  END xq[109]
  PIN xq[10]
    DIRECTION INPUT ;
    USE SIGNAL ;
    PORT
      LAYER M4 ;
        RECT  0 40.704 0.084 40.728 ;
    END
  END xq[10]
  PIN xq[110]
    DIRECTION INPUT ;
    USE SIGNAL ;
    PORT
      LAYER M4 ;
        RECT  0 45.504 0.084 45.528 ;
    END
  END xq[110]
  PIN xq[111]
    DIRECTION INPUT ;
    USE SIGNAL ;
    PORT
      LAYER M4 ;
        RECT  0 45.552 0.084 45.576 ;
    END
  END xq[111]
  PIN xq[112]
    DIRECTION INPUT ;
    USE SIGNAL ;
    PORT
      LAYER M4 ;
        RECT  0 45.6 0.084 45.624 ;
    END
  END xq[112]
  PIN xq[113]
    DIRECTION INPUT ;
    USE SIGNAL ;
    PORT
      LAYER M4 ;
        RECT  0 45.648 0.084 45.672 ;
    END
  END xq[113]
  PIN xq[114]
    DIRECTION INPUT ;
    USE SIGNAL ;
    PORT
      LAYER M4 ;
        RECT  0 45.696 0.084 45.72 ;
    END
  END xq[114]
  PIN xq[115]
    DIRECTION INPUT ;
    USE SIGNAL ;
    PORT
      LAYER M4 ;
        RECT  0 45.744 0.084 45.768 ;
    END
  END xq[115]
  PIN xq[116]
    DIRECTION INPUT ;
    USE SIGNAL ;
    PORT
      LAYER M4 ;
        RECT  0 45.792 0.084 45.816 ;
    END
  END xq[116]
  PIN xq[117]
    DIRECTION INPUT ;
    USE SIGNAL ;
    PORT
      LAYER M4 ;
        RECT  0 45.84 0.084 45.864 ;
    END
  END xq[117]
  PIN xq[118]
    DIRECTION INPUT ;
    USE SIGNAL ;
    PORT
      LAYER M4 ;
        RECT  0 45.888 0.084 45.912 ;
    END
  END xq[118]
  PIN xq[119]
    DIRECTION INPUT ;
    USE SIGNAL ;
    PORT
      LAYER M4 ;
        RECT  0 45.936 0.084 45.96 ;
    END
  END xq[119]
  PIN xq[11]
    DIRECTION INPUT ;
    USE SIGNAL ;
    PORT
      LAYER M4 ;
        RECT  0 40.752 0.084 40.776 ;
    END
  END xq[11]
  PIN xq[120]
    DIRECTION INPUT ;
    USE SIGNAL ;
    PORT
      LAYER M4 ;
        RECT  0 45.984 0.084 46.008 ;
    END
  END xq[120]
  PIN xq[121]
    DIRECTION INPUT ;
    USE SIGNAL ;
    PORT
      LAYER M4 ;
        RECT  0 46.032 0.084 46.056 ;
    END
  END xq[121]
  PIN xq[122]
    DIRECTION INPUT ;
    USE SIGNAL ;
    PORT
      LAYER M4 ;
        RECT  0 46.08 0.084 46.104 ;
    END
  END xq[122]
  PIN xq[123]
    DIRECTION INPUT ;
    USE SIGNAL ;
    PORT
      LAYER M4 ;
        RECT  0 46.128 0.084 46.152 ;
    END
  END xq[123]
  PIN xq[124]
    DIRECTION INPUT ;
    USE SIGNAL ;
    PORT
      LAYER M4 ;
        RECT  0 46.176 0.084 46.2 ;
    END
  END xq[124]
  PIN xq[125]
    DIRECTION INPUT ;
    USE SIGNAL ;
    PORT
      LAYER M4 ;
        RECT  0 46.224 0.084 46.248 ;
    END
  END xq[125]
  PIN xq[126]
    DIRECTION INPUT ;
    USE SIGNAL ;
    PORT
      LAYER M4 ;
        RECT  0 46.272 0.084 46.296 ;
    END
  END xq[126]
  PIN xq[127]
    DIRECTION INPUT ;
    USE SIGNAL ;
    PORT
      LAYER M4 ;
        RECT  0 46.32 0.084 46.344 ;
    END
  END xq[127]
  PIN xq[128]
    DIRECTION INPUT ;
    USE SIGNAL ;
    PORT
      LAYER M4 ;
        RECT  0 46.368 0.084 46.392 ;
    END
  END xq[128]
  PIN xq[129]
    DIRECTION INPUT ;
    USE SIGNAL ;
    PORT
      LAYER M4 ;
        RECT  0 46.416 0.084 46.44 ;
    END
  END xq[129]
  PIN xq[12]
    DIRECTION INPUT ;
    USE SIGNAL ;
    PORT
      LAYER M4 ;
        RECT  0 40.8 0.084 40.824 ;
    END
  END xq[12]
  PIN xq[130]
    DIRECTION INPUT ;
    USE SIGNAL ;
    PORT
      LAYER M4 ;
        RECT  0 46.464 0.084 46.488 ;
    END
  END xq[130]
  PIN xq[131]
    DIRECTION INPUT ;
    USE SIGNAL ;
    PORT
      LAYER M4 ;
        RECT  0 46.512 0.084 46.536 ;
    END
  END xq[131]
  PIN xq[132]
    DIRECTION INPUT ;
    USE SIGNAL ;
    PORT
      LAYER M4 ;
        RECT  0 46.56 0.084 46.584 ;
    END
  END xq[132]
  PIN xq[133]
    DIRECTION INPUT ;
    USE SIGNAL ;
    PORT
      LAYER M4 ;
        RECT  0 46.608 0.084 46.632 ;
    END
  END xq[133]
  PIN xq[134]
    DIRECTION INPUT ;
    USE SIGNAL ;
    PORT
      LAYER M4 ;
        RECT  0 46.656 0.084 46.68 ;
    END
  END xq[134]
  PIN xq[135]
    DIRECTION INPUT ;
    USE SIGNAL ;
    PORT
      LAYER M4 ;
        RECT  0 46.704 0.084 46.728 ;
    END
  END xq[135]
  PIN xq[136]
    DIRECTION INPUT ;
    USE SIGNAL ;
    PORT
      LAYER M4 ;
        RECT  0 46.752 0.084 46.776 ;
    END
  END xq[136]
  PIN xq[137]
    DIRECTION INPUT ;
    USE SIGNAL ;
    PORT
      LAYER M4 ;
        RECT  0 46.8 0.084 46.824 ;
    END
  END xq[137]
  PIN xq[138]
    DIRECTION INPUT ;
    USE SIGNAL ;
    PORT
      LAYER M4 ;
        RECT  0 46.848 0.084 46.872 ;
    END
  END xq[138]
  PIN xq[139]
    DIRECTION INPUT ;
    USE SIGNAL ;
    PORT
      LAYER M4 ;
        RECT  0 46.896 0.084 46.92 ;
    END
  END xq[139]
  PIN xq[13]
    DIRECTION INPUT ;
    USE SIGNAL ;
    PORT
      LAYER M4 ;
        RECT  0 40.848 0.084 40.872 ;
    END
  END xq[13]
  PIN xq[140]
    DIRECTION INPUT ;
    USE SIGNAL ;
    PORT
      LAYER M4 ;
        RECT  0 46.944 0.084 46.968 ;
    END
  END xq[140]
  PIN xq[141]
    DIRECTION INPUT ;
    USE SIGNAL ;
    PORT
      LAYER M4 ;
        RECT  0 46.992 0.084 47.016 ;
    END
  END xq[141]
  PIN xq[142]
    DIRECTION INPUT ;
    USE SIGNAL ;
    PORT
      LAYER M4 ;
        RECT  0 47.04 0.084 47.064 ;
    END
  END xq[142]
  PIN xq[143]
    DIRECTION INPUT ;
    USE SIGNAL ;
    PORT
      LAYER M4 ;
        RECT  0 47.088 0.084 47.112 ;
    END
  END xq[143]
  PIN xq[144]
    DIRECTION INPUT ;
    USE SIGNAL ;
    PORT
      LAYER M4 ;
        RECT  0 47.136 0.084 47.16 ;
    END
  END xq[144]
  PIN xq[145]
    DIRECTION INPUT ;
    USE SIGNAL ;
    PORT
      LAYER M4 ;
        RECT  0 47.184 0.084 47.208 ;
    END
  END xq[145]
  PIN xq[146]
    DIRECTION INPUT ;
    USE SIGNAL ;
    PORT
      LAYER M4 ;
        RECT  0 47.232 0.084 47.256 ;
    END
  END xq[146]
  PIN xq[147]
    DIRECTION INPUT ;
    USE SIGNAL ;
    PORT
      LAYER M4 ;
        RECT  0 47.28 0.084 47.304 ;
    END
  END xq[147]
  PIN xq[148]
    DIRECTION INPUT ;
    USE SIGNAL ;
    PORT
      LAYER M4 ;
        RECT  0 47.328 0.084 47.352 ;
    END
  END xq[148]
  PIN xq[149]
    DIRECTION INPUT ;
    USE SIGNAL ;
    PORT
      LAYER M4 ;
        RECT  0 47.376 0.084 47.4 ;
    END
  END xq[149]
  PIN xq[14]
    DIRECTION INPUT ;
    USE SIGNAL ;
    PORT
      LAYER M4 ;
        RECT  0 40.896 0.084 40.92 ;
    END
  END xq[14]
  PIN xq[150]
    DIRECTION INPUT ;
    USE SIGNAL ;
    PORT
      LAYER M4 ;
        RECT  0 47.424 0.084 47.448 ;
    END
  END xq[150]
  PIN xq[151]
    DIRECTION INPUT ;
    USE SIGNAL ;
    PORT
      LAYER M4 ;
        RECT  0 47.472 0.084 47.496 ;
    END
  END xq[151]
  PIN xq[152]
    DIRECTION INPUT ;
    USE SIGNAL ;
    PORT
      LAYER M4 ;
        RECT  0 47.52 0.084 47.544 ;
    END
  END xq[152]
  PIN xq[153]
    DIRECTION INPUT ;
    USE SIGNAL ;
    PORT
      LAYER M4 ;
        RECT  0 47.568 0.084 47.592 ;
    END
  END xq[153]
  PIN xq[154]
    DIRECTION INPUT ;
    USE SIGNAL ;
    PORT
      LAYER M4 ;
        RECT  0 47.616 0.084 47.64 ;
    END
  END xq[154]
  PIN xq[155]
    DIRECTION INPUT ;
    USE SIGNAL ;
    PORT
      LAYER M4 ;
        RECT  0 47.664 0.084 47.688 ;
    END
  END xq[155]
  PIN xq[156]
    DIRECTION INPUT ;
    USE SIGNAL ;
    PORT
      LAYER M4 ;
        RECT  0 47.712 0.084 47.736 ;
    END
  END xq[156]
  PIN xq[157]
    DIRECTION INPUT ;
    USE SIGNAL ;
    PORT
      LAYER M4 ;
        RECT  0 47.76 0.084 47.784 ;
    END
  END xq[157]
  PIN xq[158]
    DIRECTION INPUT ;
    USE SIGNAL ;
    PORT
      LAYER M4 ;
        RECT  0 47.808 0.084 47.832 ;
    END
  END xq[158]
  PIN xq[159]
    DIRECTION INPUT ;
    USE SIGNAL ;
    PORT
      LAYER M4 ;
        RECT  0 47.856 0.084 47.88 ;
    END
  END xq[159]
  PIN xq[15]
    DIRECTION INPUT ;
    USE SIGNAL ;
    PORT
      LAYER M4 ;
        RECT  0 40.944 0.084 40.968 ;
    END
  END xq[15]
  PIN xq[160]
    DIRECTION INPUT ;
    USE SIGNAL ;
    PORT
      LAYER M4 ;
        RECT  0 47.904 0.084 47.928 ;
    END
  END xq[160]
  PIN xq[161]
    DIRECTION INPUT ;
    USE SIGNAL ;
    PORT
      LAYER M4 ;
        RECT  0 47.952 0.084 47.976 ;
    END
  END xq[161]
  PIN xq[162]
    DIRECTION INPUT ;
    USE SIGNAL ;
    PORT
      LAYER M4 ;
        RECT  0 48 0.084 48.024 ;
    END
  END xq[162]
  PIN xq[163]
    DIRECTION INPUT ;
    USE SIGNAL ;
    PORT
      LAYER M4 ;
        RECT  0 48.048 0.084 48.072 ;
    END
  END xq[163]
  PIN xq[164]
    DIRECTION INPUT ;
    USE SIGNAL ;
    PORT
      LAYER M4 ;
        RECT  0 48.096 0.084 48.12 ;
    END
  END xq[164]
  PIN xq[165]
    DIRECTION INPUT ;
    USE SIGNAL ;
    PORT
      LAYER M4 ;
        RECT  0 48.144 0.084 48.168 ;
    END
  END xq[165]
  PIN xq[166]
    DIRECTION INPUT ;
    USE SIGNAL ;
    PORT
      LAYER M4 ;
        RECT  0 48.192 0.084 48.216 ;
    END
  END xq[166]
  PIN xq[167]
    DIRECTION INPUT ;
    USE SIGNAL ;
    PORT
      LAYER M4 ;
        RECT  0 48.24 0.084 48.264 ;
    END
  END xq[167]
  PIN xq[168]
    DIRECTION INPUT ;
    USE SIGNAL ;
    PORT
      LAYER M4 ;
        RECT  0 48.288 0.084 48.312 ;
    END
  END xq[168]
  PIN xq[169]
    DIRECTION INPUT ;
    USE SIGNAL ;
    PORT
      LAYER M4 ;
        RECT  0 48.336 0.084 48.36 ;
    END
  END xq[169]
  PIN xq[16]
    DIRECTION INPUT ;
    USE SIGNAL ;
    PORT
      LAYER M4 ;
        RECT  0 40.992 0.084 41.016 ;
    END
  END xq[16]
  PIN xq[170]
    DIRECTION INPUT ;
    USE SIGNAL ;
    PORT
      LAYER M4 ;
        RECT  0 48.384 0.084 48.408 ;
    END
  END xq[170]
  PIN xq[171]
    DIRECTION INPUT ;
    USE SIGNAL ;
    PORT
      LAYER M4 ;
        RECT  0 48.432 0.084 48.456 ;
    END
  END xq[171]
  PIN xq[172]
    DIRECTION INPUT ;
    USE SIGNAL ;
    PORT
      LAYER M4 ;
        RECT  0 48.48 0.084 48.504 ;
    END
  END xq[172]
  PIN xq[173]
    DIRECTION INPUT ;
    USE SIGNAL ;
    PORT
      LAYER M4 ;
        RECT  0 48.528 0.084 48.552 ;
    END
  END xq[173]
  PIN xq[174]
    DIRECTION INPUT ;
    USE SIGNAL ;
    PORT
      LAYER M4 ;
        RECT  0 48.576 0.084 48.6 ;
    END
  END xq[174]
  PIN xq[175]
    DIRECTION INPUT ;
    USE SIGNAL ;
    PORT
      LAYER M4 ;
        RECT  0 48.624 0.084 48.648 ;
    END
  END xq[175]
  PIN xq[176]
    DIRECTION INPUT ;
    USE SIGNAL ;
    PORT
      LAYER M4 ;
        RECT  0 48.672 0.084 48.696 ;
    END
  END xq[176]
  PIN xq[177]
    DIRECTION INPUT ;
    USE SIGNAL ;
    PORT
      LAYER M4 ;
        RECT  0 48.72 0.084 48.744 ;
    END
  END xq[177]
  PIN xq[178]
    DIRECTION INPUT ;
    USE SIGNAL ;
    PORT
      LAYER M4 ;
        RECT  0 48.768 0.084 48.792 ;
    END
  END xq[178]
  PIN xq[179]
    DIRECTION INPUT ;
    USE SIGNAL ;
    PORT
      LAYER M4 ;
        RECT  0 48.816 0.084 48.84 ;
    END
  END xq[179]
  PIN xq[17]
    DIRECTION INPUT ;
    USE SIGNAL ;
    PORT
      LAYER M4 ;
        RECT  0 41.04 0.084 41.064 ;
    END
  END xq[17]
  PIN xq[180]
    DIRECTION INPUT ;
    USE SIGNAL ;
    PORT
      LAYER M4 ;
        RECT  0 48.864 0.084 48.888 ;
    END
  END xq[180]
  PIN xq[181]
    DIRECTION INPUT ;
    USE SIGNAL ;
    PORT
      LAYER M4 ;
        RECT  0 48.912 0.084 48.936 ;
    END
  END xq[181]
  PIN xq[182]
    DIRECTION INPUT ;
    USE SIGNAL ;
    PORT
      LAYER M4 ;
        RECT  0 48.96 0.084 48.984 ;
    END
  END xq[182]
  PIN xq[183]
    DIRECTION INPUT ;
    USE SIGNAL ;
    PORT
      LAYER M4 ;
        RECT  0 49.008 0.084 49.032 ;
    END
  END xq[183]
  PIN xq[184]
    DIRECTION INPUT ;
    USE SIGNAL ;
    PORT
      LAYER M4 ;
        RECT  0 49.056 0.084 49.08 ;
    END
  END xq[184]
  PIN xq[185]
    DIRECTION INPUT ;
    USE SIGNAL ;
    PORT
      LAYER M4 ;
        RECT  0 49.104 0.084 49.128 ;
    END
  END xq[185]
  PIN xq[186]
    DIRECTION INPUT ;
    USE SIGNAL ;
    PORT
      LAYER M4 ;
        RECT  0 49.152 0.084 49.176 ;
    END
  END xq[186]
  PIN xq[187]
    DIRECTION INPUT ;
    USE SIGNAL ;
    PORT
      LAYER M4 ;
        RECT  0 49.2 0.084 49.224 ;
    END
  END xq[187]
  PIN xq[188]
    DIRECTION INPUT ;
    USE SIGNAL ;
    PORT
      LAYER M4 ;
        RECT  0 49.248 0.084 49.272 ;
    END
  END xq[188]
  PIN xq[189]
    DIRECTION INPUT ;
    USE SIGNAL ;
    PORT
      LAYER M4 ;
        RECT  0 49.296 0.084 49.32 ;
    END
  END xq[189]
  PIN xq[18]
    DIRECTION INPUT ;
    USE SIGNAL ;
    PORT
      LAYER M4 ;
        RECT  0 41.088 0.084 41.112 ;
    END
  END xq[18]
  PIN xq[190]
    DIRECTION INPUT ;
    USE SIGNAL ;
    PORT
      LAYER M4 ;
        RECT  0 49.344 0.084 49.368 ;
    END
  END xq[190]
  PIN xq[191]
    DIRECTION INPUT ;
    USE SIGNAL ;
    PORT
      LAYER M4 ;
        RECT  0 49.392 0.084 49.416 ;
    END
  END xq[191]
  PIN xq[192]
    DIRECTION INPUT ;
    USE SIGNAL ;
    PORT
      LAYER M4 ;
        RECT  0 49.44 0.084 49.464 ;
    END
  END xq[192]
  PIN xq[193]
    DIRECTION INPUT ;
    USE SIGNAL ;
    PORT
      LAYER M4 ;
        RECT  0 49.488 0.084 49.512 ;
    END
  END xq[193]
  PIN xq[194]
    DIRECTION INPUT ;
    USE SIGNAL ;
    PORT
      LAYER M4 ;
        RECT  0 49.536 0.084 49.56 ;
    END
  END xq[194]
  PIN xq[195]
    DIRECTION INPUT ;
    USE SIGNAL ;
    PORT
      LAYER M4 ;
        RECT  0 49.584 0.084 49.608 ;
    END
  END xq[195]
  PIN xq[196]
    DIRECTION INPUT ;
    USE SIGNAL ;
    PORT
      LAYER M4 ;
        RECT  0 49.632 0.084 49.656 ;
    END
  END xq[196]
  PIN xq[197]
    DIRECTION INPUT ;
    USE SIGNAL ;
    PORT
      LAYER M4 ;
        RECT  0 49.68 0.084 49.704 ;
    END
  END xq[197]
  PIN xq[198]
    DIRECTION INPUT ;
    USE SIGNAL ;
    PORT
      LAYER M4 ;
        RECT  0 49.728 0.084 49.752 ;
    END
  END xq[198]
  PIN xq[199]
    DIRECTION INPUT ;
    USE SIGNAL ;
    PORT
      LAYER M4 ;
        RECT  0 49.776 0.084 49.8 ;
    END
  END xq[199]
  PIN xq[19]
    DIRECTION INPUT ;
    USE SIGNAL ;
    PORT
      LAYER M4 ;
        RECT  0 41.136 0.084 41.16 ;
    END
  END xq[19]
  PIN xq[1]
    DIRECTION INPUT ;
    USE SIGNAL ;
    PORT
      LAYER M4 ;
        RECT  0 40.272 0.084 40.296 ;
    END
  END xq[1]
  PIN xq[200]
    DIRECTION INPUT ;
    USE SIGNAL ;
    PORT
      LAYER M4 ;
        RECT  0 49.824 0.084 49.848 ;
    END
  END xq[200]
  PIN xq[201]
    DIRECTION INPUT ;
    USE SIGNAL ;
    PORT
      LAYER M4 ;
        RECT  0 49.872 0.084 49.896 ;
    END
  END xq[201]
  PIN xq[202]
    DIRECTION INPUT ;
    USE SIGNAL ;
    PORT
      LAYER M4 ;
        RECT  0 49.92 0.084 49.944 ;
    END
  END xq[202]
  PIN xq[203]
    DIRECTION INPUT ;
    USE SIGNAL ;
    PORT
      LAYER M4 ;
        RECT  0 49.968 0.084 49.992 ;
    END
  END xq[203]
  PIN xq[204]
    DIRECTION INPUT ;
    USE SIGNAL ;
    PORT
      LAYER M4 ;
        RECT  0 50.016 0.084 50.04 ;
    END
  END xq[204]
  PIN xq[205]
    DIRECTION INPUT ;
    USE SIGNAL ;
    PORT
      LAYER M4 ;
        RECT  0 50.064 0.084 50.088 ;
    END
  END xq[205]
  PIN xq[206]
    DIRECTION INPUT ;
    USE SIGNAL ;
    PORT
      LAYER M4 ;
        RECT  0 50.112 0.084 50.136 ;
    END
  END xq[206]
  PIN xq[207]
    DIRECTION INPUT ;
    USE SIGNAL ;
    PORT
      LAYER M4 ;
        RECT  0 50.16 0.084 50.184 ;
    END
  END xq[207]
  PIN xq[208]
    DIRECTION INPUT ;
    USE SIGNAL ;
    PORT
      LAYER M4 ;
        RECT  0 50.208 0.084 50.232 ;
    END
  END xq[208]
  PIN xq[209]
    DIRECTION INPUT ;
    USE SIGNAL ;
    PORT
      LAYER M4 ;
        RECT  0 50.256 0.084 50.28 ;
    END
  END xq[209]
  PIN xq[20]
    DIRECTION INPUT ;
    USE SIGNAL ;
    PORT
      LAYER M4 ;
        RECT  0 41.184 0.084 41.208 ;
    END
  END xq[20]
  PIN xq[210]
    DIRECTION INPUT ;
    USE SIGNAL ;
    PORT
      LAYER M4 ;
        RECT  0 50.304 0.084 50.328 ;
    END
  END xq[210]
  PIN xq[211]
    DIRECTION INPUT ;
    USE SIGNAL ;
    PORT
      LAYER M4 ;
        RECT  0 50.352 0.084 50.376 ;
    END
  END xq[211]
  PIN xq[212]
    DIRECTION INPUT ;
    USE SIGNAL ;
    PORT
      LAYER M4 ;
        RECT  0 50.4 0.084 50.424 ;
    END
  END xq[212]
  PIN xq[213]
    DIRECTION INPUT ;
    USE SIGNAL ;
    PORT
      LAYER M4 ;
        RECT  0 50.448 0.084 50.472 ;
    END
  END xq[213]
  PIN xq[214]
    DIRECTION INPUT ;
    USE SIGNAL ;
    PORT
      LAYER M4 ;
        RECT  0 50.496 0.084 50.52 ;
    END
  END xq[214]
  PIN xq[215]
    DIRECTION INPUT ;
    USE SIGNAL ;
    PORT
      LAYER M4 ;
        RECT  0 50.544 0.084 50.568 ;
    END
  END xq[215]
  PIN xq[216]
    DIRECTION INPUT ;
    USE SIGNAL ;
    PORT
      LAYER M4 ;
        RECT  0 50.592 0.084 50.616 ;
    END
  END xq[216]
  PIN xq[217]
    DIRECTION INPUT ;
    USE SIGNAL ;
    PORT
      LAYER M4 ;
        RECT  0 50.64 0.084 50.664 ;
    END
  END xq[217]
  PIN xq[218]
    DIRECTION INPUT ;
    USE SIGNAL ;
    PORT
      LAYER M4 ;
        RECT  0 50.688 0.084 50.712 ;
    END
  END xq[218]
  PIN xq[219]
    DIRECTION INPUT ;
    USE SIGNAL ;
    PORT
      LAYER M4 ;
        RECT  0 50.736 0.084 50.76 ;
    END
  END xq[219]
  PIN xq[21]
    DIRECTION INPUT ;
    USE SIGNAL ;
    PORT
      LAYER M4 ;
        RECT  0 41.232 0.084 41.256 ;
    END
  END xq[21]
  PIN xq[220]
    DIRECTION INPUT ;
    USE SIGNAL ;
    PORT
      LAYER M4 ;
        RECT  0 50.784 0.084 50.808 ;
    END
  END xq[220]
  PIN xq[221]
    DIRECTION INPUT ;
    USE SIGNAL ;
    PORT
      LAYER M4 ;
        RECT  0 50.832 0.084 50.856 ;
    END
  END xq[221]
  PIN xq[222]
    DIRECTION INPUT ;
    USE SIGNAL ;
    PORT
      LAYER M4 ;
        RECT  0 50.88 0.084 50.904 ;
    END
  END xq[222]
  PIN xq[223]
    DIRECTION INPUT ;
    USE SIGNAL ;
    PORT
      LAYER M4 ;
        RECT  0 50.928 0.084 50.952 ;
    END
  END xq[223]
  PIN xq[224]
    DIRECTION INPUT ;
    USE SIGNAL ;
    PORT
      LAYER M4 ;
        RECT  0 50.976 0.084 51 ;
    END
  END xq[224]
  PIN xq[225]
    DIRECTION INPUT ;
    USE SIGNAL ;
    PORT
      LAYER M4 ;
        RECT  0 51.024 0.084 51.048 ;
    END
  END xq[225]
  PIN xq[226]
    DIRECTION INPUT ;
    USE SIGNAL ;
    PORT
      LAYER M4 ;
        RECT  0 51.072 0.084 51.096 ;
    END
  END xq[226]
  PIN xq[227]
    DIRECTION INPUT ;
    USE SIGNAL ;
    PORT
      LAYER M4 ;
        RECT  0 51.12 0.084 51.144 ;
    END
  END xq[227]
  PIN xq[228]
    DIRECTION INPUT ;
    USE SIGNAL ;
    PORT
      LAYER M4 ;
        RECT  0 51.168 0.084 51.192 ;
    END
  END xq[228]
  PIN xq[229]
    DIRECTION INPUT ;
    USE SIGNAL ;
    PORT
      LAYER M4 ;
        RECT  0 51.216 0.084 51.24 ;
    END
  END xq[229]
  PIN xq[22]
    DIRECTION INPUT ;
    USE SIGNAL ;
    PORT
      LAYER M4 ;
        RECT  0 41.28 0.084 41.304 ;
    END
  END xq[22]
  PIN xq[230]
    DIRECTION INPUT ;
    USE SIGNAL ;
    PORT
      LAYER M4 ;
        RECT  0 51.264 0.084 51.288 ;
    END
  END xq[230]
  PIN xq[231]
    DIRECTION INPUT ;
    USE SIGNAL ;
    PORT
      LAYER M4 ;
        RECT  0 51.312 0.084 51.336 ;
    END
  END xq[231]
  PIN xq[232]
    DIRECTION INPUT ;
    USE SIGNAL ;
    PORT
      LAYER M4 ;
        RECT  0 51.36 0.084 51.384 ;
    END
  END xq[232]
  PIN xq[233]
    DIRECTION INPUT ;
    USE SIGNAL ;
    PORT
      LAYER M4 ;
        RECT  0 51.408 0.084 51.432 ;
    END
  END xq[233]
  PIN xq[234]
    DIRECTION INPUT ;
    USE SIGNAL ;
    PORT
      LAYER M4 ;
        RECT  0 51.456 0.084 51.48 ;
    END
  END xq[234]
  PIN xq[235]
    DIRECTION INPUT ;
    USE SIGNAL ;
    PORT
      LAYER M4 ;
        RECT  0 51.504 0.084 51.528 ;
    END
  END xq[235]
  PIN xq[236]
    DIRECTION INPUT ;
    USE SIGNAL ;
    PORT
      LAYER M4 ;
        RECT  0 51.552 0.084 51.576 ;
    END
  END xq[236]
  PIN xq[237]
    DIRECTION INPUT ;
    USE SIGNAL ;
    PORT
      LAYER M4 ;
        RECT  0 51.6 0.084 51.624 ;
    END
  END xq[237]
  PIN xq[238]
    DIRECTION INPUT ;
    USE SIGNAL ;
    PORT
      LAYER M4 ;
        RECT  0 51.648 0.084 51.672 ;
    END
  END xq[238]
  PIN xq[239]
    DIRECTION INPUT ;
    USE SIGNAL ;
    PORT
      LAYER M4 ;
        RECT  0 51.696 0.084 51.72 ;
    END
  END xq[239]
  PIN xq[23]
    DIRECTION INPUT ;
    USE SIGNAL ;
    PORT
      LAYER M4 ;
        RECT  0 41.328 0.084 41.352 ;
    END
  END xq[23]
  PIN xq[240]
    DIRECTION INPUT ;
    USE SIGNAL ;
    PORT
      LAYER M4 ;
        RECT  0 51.744 0.084 51.768 ;
    END
  END xq[240]
  PIN xq[241]
    DIRECTION INPUT ;
    USE SIGNAL ;
    PORT
      LAYER M4 ;
        RECT  0 51.792 0.084 51.816 ;
    END
  END xq[241]
  PIN xq[242]
    DIRECTION INPUT ;
    USE SIGNAL ;
    PORT
      LAYER M4 ;
        RECT  0 51.84 0.084 51.864 ;
    END
  END xq[242]
  PIN xq[243]
    DIRECTION INPUT ;
    USE SIGNAL ;
    PORT
      LAYER M4 ;
        RECT  0 51.888 0.084 51.912 ;
    END
  END xq[243]
  PIN xq[244]
    DIRECTION INPUT ;
    USE SIGNAL ;
    PORT
      LAYER M4 ;
        RECT  0 51.936 0.084 51.96 ;
    END
  END xq[244]
  PIN xq[245]
    DIRECTION INPUT ;
    USE SIGNAL ;
    PORT
      LAYER M4 ;
        RECT  0 51.984 0.084 52.008 ;
    END
  END xq[245]
  PIN xq[246]
    DIRECTION INPUT ;
    USE SIGNAL ;
    PORT
      LAYER M4 ;
        RECT  0 52.032 0.084 52.056 ;
    END
  END xq[246]
  PIN xq[247]
    DIRECTION INPUT ;
    USE SIGNAL ;
    PORT
      LAYER M4 ;
        RECT  0 52.08 0.084 52.104 ;
    END
  END xq[247]
  PIN xq[248]
    DIRECTION INPUT ;
    USE SIGNAL ;
    PORT
      LAYER M4 ;
        RECT  0 52.128 0.084 52.152 ;
    END
  END xq[248]
  PIN xq[249]
    DIRECTION INPUT ;
    USE SIGNAL ;
    PORT
      LAYER M4 ;
        RECT  0 52.176 0.084 52.2 ;
    END
  END xq[249]
  PIN xq[24]
    DIRECTION INPUT ;
    USE SIGNAL ;
    PORT
      LAYER M4 ;
        RECT  0 41.376 0.084 41.4 ;
    END
  END xq[24]
  PIN xq[250]
    DIRECTION INPUT ;
    USE SIGNAL ;
    PORT
      LAYER M4 ;
        RECT  0 52.224 0.084 52.248 ;
    END
  END xq[250]
  PIN xq[251]
    DIRECTION INPUT ;
    USE SIGNAL ;
    PORT
      LAYER M4 ;
        RECT  0 52.272 0.084 52.296 ;
    END
  END xq[251]
  PIN xq[252]
    DIRECTION INPUT ;
    USE SIGNAL ;
    PORT
      LAYER M4 ;
        RECT  0 52.32 0.084 52.344 ;
    END
  END xq[252]
  PIN xq[253]
    DIRECTION INPUT ;
    USE SIGNAL ;
    PORT
      LAYER M4 ;
        RECT  0 52.368 0.084 52.392 ;
    END
  END xq[253]
  PIN xq[254]
    DIRECTION INPUT ;
    USE SIGNAL ;
    PORT
      LAYER M4 ;
        RECT  0 52.416 0.084 52.44 ;
    END
  END xq[254]
  PIN xq[255]
    DIRECTION INPUT ;
    USE SIGNAL ;
    PORT
      LAYER M4 ;
        RECT  0 52.464 0.084 52.488 ;
    END
  END xq[255]
  PIN xq[256]
    DIRECTION INPUT ;
    USE SIGNAL ;
    PORT
      LAYER M4 ;
        RECT  0 52.512 0.084 52.536 ;
    END
  END xq[256]
  PIN xq[257]
    DIRECTION INPUT ;
    USE SIGNAL ;
    PORT
      LAYER M4 ;
        RECT  0 52.56 0.084 52.584 ;
    END
  END xq[257]
  PIN xq[258]
    DIRECTION INPUT ;
    USE SIGNAL ;
    PORT
      LAYER M4 ;
        RECT  0 52.608 0.084 52.632 ;
    END
  END xq[258]
  PIN xq[259]
    DIRECTION INPUT ;
    USE SIGNAL ;
    PORT
      LAYER M4 ;
        RECT  0 52.656 0.084 52.68 ;
    END
  END xq[259]
  PIN xq[25]
    DIRECTION INPUT ;
    USE SIGNAL ;
    PORT
      LAYER M4 ;
        RECT  0 41.424 0.084 41.448 ;
    END
  END xq[25]
  PIN xq[260]
    DIRECTION INPUT ;
    USE SIGNAL ;
    PORT
      LAYER M4 ;
        RECT  0 52.704 0.084 52.728 ;
    END
  END xq[260]
  PIN xq[261]
    DIRECTION INPUT ;
    USE SIGNAL ;
    PORT
      LAYER M4 ;
        RECT  0 52.752 0.084 52.776 ;
    END
  END xq[261]
  PIN xq[262]
    DIRECTION INPUT ;
    USE SIGNAL ;
    PORT
      LAYER M4 ;
        RECT  0 52.8 0.084 52.824 ;
    END
  END xq[262]
  PIN xq[263]
    DIRECTION INPUT ;
    USE SIGNAL ;
    PORT
      LAYER M4 ;
        RECT  0 52.848 0.084 52.872 ;
    END
  END xq[263]
  PIN xq[264]
    DIRECTION INPUT ;
    USE SIGNAL ;
    PORT
      LAYER M4 ;
        RECT  0 52.896 0.084 52.92 ;
    END
  END xq[264]
  PIN xq[265]
    DIRECTION INPUT ;
    USE SIGNAL ;
    PORT
      LAYER M4 ;
        RECT  0 52.944 0.084 52.968 ;
    END
  END xq[265]
  PIN xq[266]
    DIRECTION INPUT ;
    USE SIGNAL ;
    PORT
      LAYER M4 ;
        RECT  0 52.992 0.084 53.016 ;
    END
  END xq[266]
  PIN xq[267]
    DIRECTION INPUT ;
    USE SIGNAL ;
    PORT
      LAYER M4 ;
        RECT  0 53.04 0.084 53.064 ;
    END
  END xq[267]
  PIN xq[268]
    DIRECTION INPUT ;
    USE SIGNAL ;
    PORT
      LAYER M4 ;
        RECT  0 53.088 0.084 53.112 ;
    END
  END xq[268]
  PIN xq[269]
    DIRECTION INPUT ;
    USE SIGNAL ;
    PORT
      LAYER M4 ;
        RECT  0 53.136 0.084 53.16 ;
    END
  END xq[269]
  PIN xq[26]
    DIRECTION INPUT ;
    USE SIGNAL ;
    PORT
      LAYER M4 ;
        RECT  0 41.472 0.084 41.496 ;
    END
  END xq[26]
  PIN xq[270]
    DIRECTION INPUT ;
    USE SIGNAL ;
    PORT
      LAYER M4 ;
        RECT  0 53.184 0.084 53.208 ;
    END
  END xq[270]
  PIN xq[271]
    DIRECTION INPUT ;
    USE SIGNAL ;
    PORT
      LAYER M4 ;
        RECT  0 53.232 0.084 53.256 ;
    END
  END xq[271]
  PIN xq[272]
    DIRECTION INPUT ;
    USE SIGNAL ;
    PORT
      LAYER M4 ;
        RECT  0 53.28 0.084 53.304 ;
    END
  END xq[272]
  PIN xq[273]
    DIRECTION INPUT ;
    USE SIGNAL ;
    PORT
      LAYER M4 ;
        RECT  0 53.328 0.084 53.352 ;
    END
  END xq[273]
  PIN xq[274]
    DIRECTION INPUT ;
    USE SIGNAL ;
    PORT
      LAYER M4 ;
        RECT  0 53.376 0.084 53.4 ;
    END
  END xq[274]
  PIN xq[275]
    DIRECTION INPUT ;
    USE SIGNAL ;
    PORT
      LAYER M4 ;
        RECT  0 53.424 0.084 53.448 ;
    END
  END xq[275]
  PIN xq[276]
    DIRECTION INPUT ;
    USE SIGNAL ;
    PORT
      LAYER M4 ;
        RECT  0 53.472 0.084 53.496 ;
    END
  END xq[276]
  PIN xq[277]
    DIRECTION INPUT ;
    USE SIGNAL ;
    PORT
      LAYER M4 ;
        RECT  0 53.52 0.084 53.544 ;
    END
  END xq[277]
  PIN xq[278]
    DIRECTION INPUT ;
    USE SIGNAL ;
    PORT
      LAYER M4 ;
        RECT  0 53.568 0.084 53.592 ;
    END
  END xq[278]
  PIN xq[279]
    DIRECTION INPUT ;
    USE SIGNAL ;
    PORT
      LAYER M4 ;
        RECT  0 53.616 0.084 53.64 ;
    END
  END xq[279]
  PIN xq[27]
    DIRECTION INPUT ;
    USE SIGNAL ;
    PORT
      LAYER M4 ;
        RECT  0 41.52 0.084 41.544 ;
    END
  END xq[27]
  PIN xq[280]
    DIRECTION INPUT ;
    USE SIGNAL ;
    PORT
      LAYER M4 ;
        RECT  0 53.664 0.084 53.688 ;
    END
  END xq[280]
  PIN xq[281]
    DIRECTION INPUT ;
    USE SIGNAL ;
    PORT
      LAYER M4 ;
        RECT  0 53.712 0.084 53.736 ;
    END
  END xq[281]
  PIN xq[282]
    DIRECTION INPUT ;
    USE SIGNAL ;
    PORT
      LAYER M4 ;
        RECT  0 53.76 0.084 53.784 ;
    END
  END xq[282]
  PIN xq[283]
    DIRECTION INPUT ;
    USE SIGNAL ;
    PORT
      LAYER M4 ;
        RECT  0 53.808 0.084 53.832 ;
    END
  END xq[283]
  PIN xq[284]
    DIRECTION INPUT ;
    USE SIGNAL ;
    PORT
      LAYER M4 ;
        RECT  0 53.856 0.084 53.88 ;
    END
  END xq[284]
  PIN xq[285]
    DIRECTION INPUT ;
    USE SIGNAL ;
    PORT
      LAYER M4 ;
        RECT  0 53.904 0.084 53.928 ;
    END
  END xq[285]
  PIN xq[286]
    DIRECTION INPUT ;
    USE SIGNAL ;
    PORT
      LAYER M4 ;
        RECT  0 53.952 0.084 53.976 ;
    END
  END xq[286]
  PIN xq[287]
    DIRECTION INPUT ;
    USE SIGNAL ;
    PORT
      LAYER M4 ;
        RECT  0 54 0.084 54.024 ;
    END
  END xq[287]
  PIN xq[288]
    DIRECTION INPUT ;
    USE SIGNAL ;
    PORT
      LAYER M4 ;
        RECT  0 54.048 0.084 54.072 ;
    END
  END xq[288]
  PIN xq[289]
    DIRECTION INPUT ;
    USE SIGNAL ;
    PORT
      LAYER M4 ;
        RECT  0 54.096 0.084 54.12 ;
    END
  END xq[289]
  PIN xq[28]
    DIRECTION INPUT ;
    USE SIGNAL ;
    PORT
      LAYER M4 ;
        RECT  0 41.568 0.084 41.592 ;
    END
  END xq[28]
  PIN xq[290]
    DIRECTION INPUT ;
    USE SIGNAL ;
    PORT
      LAYER M4 ;
        RECT  0 54.144 0.084 54.168 ;
    END
  END xq[290]
  PIN xq[291]
    DIRECTION INPUT ;
    USE SIGNAL ;
    PORT
      LAYER M4 ;
        RECT  0 54.192 0.084 54.216 ;
    END
  END xq[291]
  PIN xq[292]
    DIRECTION INPUT ;
    USE SIGNAL ;
    PORT
      LAYER M4 ;
        RECT  0 54.24 0.084 54.264 ;
    END
  END xq[292]
  PIN xq[293]
    DIRECTION INPUT ;
    USE SIGNAL ;
    PORT
      LAYER M4 ;
        RECT  0 54.288 0.084 54.312 ;
    END
  END xq[293]
  PIN xq[294]
    DIRECTION INPUT ;
    USE SIGNAL ;
    PORT
      LAYER M4 ;
        RECT  0 54.336 0.084 54.36 ;
    END
  END xq[294]
  PIN xq[295]
    DIRECTION INPUT ;
    USE SIGNAL ;
    PORT
      LAYER M4 ;
        RECT  0 54.384 0.084 54.408 ;
    END
  END xq[295]
  PIN xq[296]
    DIRECTION INPUT ;
    USE SIGNAL ;
    PORT
      LAYER M4 ;
        RECT  0 54.432 0.084 54.456 ;
    END
  END xq[296]
  PIN xq[297]
    DIRECTION INPUT ;
    USE SIGNAL ;
    PORT
      LAYER M4 ;
        RECT  0 54.48 0.084 54.504 ;
    END
  END xq[297]
  PIN xq[298]
    DIRECTION INPUT ;
    USE SIGNAL ;
    PORT
      LAYER M4 ;
        RECT  0 54.528 0.084 54.552 ;
    END
  END xq[298]
  PIN xq[299]
    DIRECTION INPUT ;
    USE SIGNAL ;
    PORT
      LAYER M4 ;
        RECT  0 54.576 0.084 54.6 ;
    END
  END xq[299]
  PIN xq[29]
    DIRECTION INPUT ;
    USE SIGNAL ;
    PORT
      LAYER M4 ;
        RECT  0 41.616 0.084 41.64 ;
    END
  END xq[29]
  PIN xq[2]
    DIRECTION INPUT ;
    USE SIGNAL ;
    PORT
      LAYER M4 ;
        RECT  0 40.32 0.084 40.344 ;
    END
  END xq[2]
  PIN xq[300]
    DIRECTION INPUT ;
    USE SIGNAL ;
    PORT
      LAYER M4 ;
        RECT  0 54.624 0.084 54.648 ;
    END
  END xq[300]
  PIN xq[301]
    DIRECTION INPUT ;
    USE SIGNAL ;
    PORT
      LAYER M4 ;
        RECT  0 54.672 0.084 54.696 ;
    END
  END xq[301]
  PIN xq[302]
    DIRECTION INPUT ;
    USE SIGNAL ;
    PORT
      LAYER M4 ;
        RECT  0 54.72 0.084 54.744 ;
    END
  END xq[302]
  PIN xq[303]
    DIRECTION INPUT ;
    USE SIGNAL ;
    PORT
      LAYER M4 ;
        RECT  0 54.768 0.084 54.792 ;
    END
  END xq[303]
  PIN xq[304]
    DIRECTION INPUT ;
    USE SIGNAL ;
    PORT
      LAYER M4 ;
        RECT  0 54.816 0.084 54.84 ;
    END
  END xq[304]
  PIN xq[305]
    DIRECTION INPUT ;
    USE SIGNAL ;
    PORT
      LAYER M4 ;
        RECT  0 54.864 0.084 54.888 ;
    END
  END xq[305]
  PIN xq[306]
    DIRECTION INPUT ;
    USE SIGNAL ;
    PORT
      LAYER M4 ;
        RECT  0 54.912 0.084 54.936 ;
    END
  END xq[306]
  PIN xq[307]
    DIRECTION INPUT ;
    USE SIGNAL ;
    PORT
      LAYER M4 ;
        RECT  0 54.96 0.084 54.984 ;
    END
  END xq[307]
  PIN xq[308]
    DIRECTION INPUT ;
    USE SIGNAL ;
    PORT
      LAYER M4 ;
        RECT  0 55.008 0.084 55.032 ;
    END
  END xq[308]
  PIN xq[309]
    DIRECTION INPUT ;
    USE SIGNAL ;
    PORT
      LAYER M4 ;
        RECT  0 55.056 0.084 55.08 ;
    END
  END xq[309]
  PIN xq[30]
    DIRECTION INPUT ;
    USE SIGNAL ;
    PORT
      LAYER M4 ;
        RECT  0 41.664 0.084 41.688 ;
    END
  END xq[30]
  PIN xq[310]
    DIRECTION INPUT ;
    USE SIGNAL ;
    PORT
      LAYER M4 ;
        RECT  0 55.104 0.084 55.128 ;
    END
  END xq[310]
  PIN xq[311]
    DIRECTION INPUT ;
    USE SIGNAL ;
    PORT
      LAYER M4 ;
        RECT  0 55.152 0.084 55.176 ;
    END
  END xq[311]
  PIN xq[312]
    DIRECTION INPUT ;
    USE SIGNAL ;
    PORT
      LAYER M4 ;
        RECT  0 55.2 0.084 55.224 ;
    END
  END xq[312]
  PIN xq[313]
    DIRECTION INPUT ;
    USE SIGNAL ;
    PORT
      LAYER M4 ;
        RECT  0 55.248 0.084 55.272 ;
    END
  END xq[313]
  PIN xq[314]
    DIRECTION INPUT ;
    USE SIGNAL ;
    PORT
      LAYER M4 ;
        RECT  0 55.296 0.084 55.32 ;
    END
  END xq[314]
  PIN xq[315]
    DIRECTION INPUT ;
    USE SIGNAL ;
    PORT
      LAYER M4 ;
        RECT  0 55.344 0.084 55.368 ;
    END
  END xq[315]
  PIN xq[316]
    DIRECTION INPUT ;
    USE SIGNAL ;
    PORT
      LAYER M4 ;
        RECT  0 55.392 0.084 55.416 ;
    END
  END xq[316]
  PIN xq[317]
    DIRECTION INPUT ;
    USE SIGNAL ;
    PORT
      LAYER M4 ;
        RECT  0 55.44 0.084 55.464 ;
    END
  END xq[317]
  PIN xq[318]
    DIRECTION INPUT ;
    USE SIGNAL ;
    PORT
      LAYER M4 ;
        RECT  0 55.488 0.084 55.512 ;
    END
  END xq[318]
  PIN xq[319]
    DIRECTION INPUT ;
    USE SIGNAL ;
    PORT
      LAYER M4 ;
        RECT  0 55.536 0.084 55.56 ;
    END
  END xq[319]
  PIN xq[31]
    DIRECTION INPUT ;
    USE SIGNAL ;
    PORT
      LAYER M4 ;
        RECT  0 41.712 0.084 41.736 ;
    END
  END xq[31]
  PIN xq[320]
    DIRECTION INPUT ;
    USE SIGNAL ;
    PORT
      LAYER M4 ;
        RECT  0 55.584 0.084 55.608 ;
    END
  END xq[320]
  PIN xq[321]
    DIRECTION INPUT ;
    USE SIGNAL ;
    PORT
      LAYER M4 ;
        RECT  0 55.632 0.084 55.656 ;
    END
  END xq[321]
  PIN xq[322]
    DIRECTION INPUT ;
    USE SIGNAL ;
    PORT
      LAYER M4 ;
        RECT  0 55.68 0.084 55.704 ;
    END
  END xq[322]
  PIN xq[323]
    DIRECTION INPUT ;
    USE SIGNAL ;
    PORT
      LAYER M4 ;
        RECT  0 55.728 0.084 55.752 ;
    END
  END xq[323]
  PIN xq[324]
    DIRECTION INPUT ;
    USE SIGNAL ;
    PORT
      LAYER M4 ;
        RECT  0 55.776 0.084 55.8 ;
    END
  END xq[324]
  PIN xq[325]
    DIRECTION INPUT ;
    USE SIGNAL ;
    PORT
      LAYER M4 ;
        RECT  0 55.824 0.084 55.848 ;
    END
  END xq[325]
  PIN xq[326]
    DIRECTION INPUT ;
    USE SIGNAL ;
    PORT
      LAYER M4 ;
        RECT  0 55.872 0.084 55.896 ;
    END
  END xq[326]
  PIN xq[327]
    DIRECTION INPUT ;
    USE SIGNAL ;
    PORT
      LAYER M4 ;
        RECT  0 55.92 0.084 55.944 ;
    END
  END xq[327]
  PIN xq[328]
    DIRECTION INPUT ;
    USE SIGNAL ;
    PORT
      LAYER M4 ;
        RECT  0 55.968 0.084 55.992 ;
    END
  END xq[328]
  PIN xq[329]
    DIRECTION INPUT ;
    USE SIGNAL ;
    PORT
      LAYER M4 ;
        RECT  0 56.016 0.084 56.04 ;
    END
  END xq[329]
  PIN xq[32]
    DIRECTION INPUT ;
    USE SIGNAL ;
    PORT
      LAYER M4 ;
        RECT  0 41.76 0.084 41.784 ;
    END
  END xq[32]
  PIN xq[330]
    DIRECTION INPUT ;
    USE SIGNAL ;
    PORT
      LAYER M4 ;
        RECT  0 56.064 0.084 56.088 ;
    END
  END xq[330]
  PIN xq[331]
    DIRECTION INPUT ;
    USE SIGNAL ;
    PORT
      LAYER M4 ;
        RECT  0 56.112 0.084 56.136 ;
    END
  END xq[331]
  PIN xq[332]
    DIRECTION INPUT ;
    USE SIGNAL ;
    PORT
      LAYER M4 ;
        RECT  0 56.16 0.084 56.184 ;
    END
  END xq[332]
  PIN xq[333]
    DIRECTION INPUT ;
    USE SIGNAL ;
    PORT
      LAYER M4 ;
        RECT  0 56.208 0.084 56.232 ;
    END
  END xq[333]
  PIN xq[334]
    DIRECTION INPUT ;
    USE SIGNAL ;
    PORT
      LAYER M4 ;
        RECT  0 56.256 0.084 56.28 ;
    END
  END xq[334]
  PIN xq[335]
    DIRECTION INPUT ;
    USE SIGNAL ;
    PORT
      LAYER M4 ;
        RECT  0 56.304 0.084 56.328 ;
    END
  END xq[335]
  PIN xq[336]
    DIRECTION INPUT ;
    USE SIGNAL ;
    PORT
      LAYER M4 ;
        RECT  0 56.352 0.084 56.376 ;
    END
  END xq[336]
  PIN xq[337]
    DIRECTION INPUT ;
    USE SIGNAL ;
    PORT
      LAYER M4 ;
        RECT  0 56.4 0.084 56.424 ;
    END
  END xq[337]
  PIN xq[338]
    DIRECTION INPUT ;
    USE SIGNAL ;
    PORT
      LAYER M4 ;
        RECT  0 56.448 0.084 56.472 ;
    END
  END xq[338]
  PIN xq[339]
    DIRECTION INPUT ;
    USE SIGNAL ;
    PORT
      LAYER M4 ;
        RECT  0 56.496 0.084 56.52 ;
    END
  END xq[339]
  PIN xq[33]
    DIRECTION INPUT ;
    USE SIGNAL ;
    PORT
      LAYER M4 ;
        RECT  0 41.808 0.084 41.832 ;
    END
  END xq[33]
  PIN xq[340]
    DIRECTION INPUT ;
    USE SIGNAL ;
    PORT
      LAYER M4 ;
        RECT  0 56.544 0.084 56.568 ;
    END
  END xq[340]
  PIN xq[341]
    DIRECTION INPUT ;
    USE SIGNAL ;
    PORT
      LAYER M4 ;
        RECT  0 56.592 0.084 56.616 ;
    END
  END xq[341]
  PIN xq[342]
    DIRECTION INPUT ;
    USE SIGNAL ;
    PORT
      LAYER M4 ;
        RECT  0 56.64 0.084 56.664 ;
    END
  END xq[342]
  PIN xq[343]
    DIRECTION INPUT ;
    USE SIGNAL ;
    PORT
      LAYER M4 ;
        RECT  0 56.688 0.084 56.712 ;
    END
  END xq[343]
  PIN xq[344]
    DIRECTION INPUT ;
    USE SIGNAL ;
    PORT
      LAYER M4 ;
        RECT  0 56.736 0.084 56.76 ;
    END
  END xq[344]
  PIN xq[345]
    DIRECTION INPUT ;
    USE SIGNAL ;
    PORT
      LAYER M4 ;
        RECT  0 56.784 0.084 56.808 ;
    END
  END xq[345]
  PIN xq[346]
    DIRECTION INPUT ;
    USE SIGNAL ;
    PORT
      LAYER M4 ;
        RECT  0 56.832 0.084 56.856 ;
    END
  END xq[346]
  PIN xq[347]
    DIRECTION INPUT ;
    USE SIGNAL ;
    PORT
      LAYER M4 ;
        RECT  0 56.88 0.084 56.904 ;
    END
  END xq[347]
  PIN xq[348]
    DIRECTION INPUT ;
    USE SIGNAL ;
    PORT
      LAYER M4 ;
        RECT  0 56.928 0.084 56.952 ;
    END
  END xq[348]
  PIN xq[349]
    DIRECTION INPUT ;
    USE SIGNAL ;
    PORT
      LAYER M4 ;
        RECT  0 56.976 0.084 57 ;
    END
  END xq[349]
  PIN xq[34]
    DIRECTION INPUT ;
    USE SIGNAL ;
    PORT
      LAYER M4 ;
        RECT  0 41.856 0.084 41.88 ;
    END
  END xq[34]
  PIN xq[350]
    DIRECTION INPUT ;
    USE SIGNAL ;
    PORT
      LAYER M4 ;
        RECT  0 57.024 0.084 57.048 ;
    END
  END xq[350]
  PIN xq[351]
    DIRECTION INPUT ;
    USE SIGNAL ;
    PORT
      LAYER M4 ;
        RECT  0 57.072 0.084 57.096 ;
    END
  END xq[351]
  PIN xq[352]
    DIRECTION INPUT ;
    USE SIGNAL ;
    PORT
      LAYER M4 ;
        RECT  0 57.12 0.084 57.144 ;
    END
  END xq[352]
  PIN xq[353]
    DIRECTION INPUT ;
    USE SIGNAL ;
    PORT
      LAYER M4 ;
        RECT  0 57.168 0.084 57.192 ;
    END
  END xq[353]
  PIN xq[354]
    DIRECTION INPUT ;
    USE SIGNAL ;
    PORT
      LAYER M4 ;
        RECT  0 57.216 0.084 57.24 ;
    END
  END xq[354]
  PIN xq[355]
    DIRECTION INPUT ;
    USE SIGNAL ;
    PORT
      LAYER M4 ;
        RECT  0 57.264 0.084 57.288 ;
    END
  END xq[355]
  PIN xq[356]
    DIRECTION INPUT ;
    USE SIGNAL ;
    PORT
      LAYER M4 ;
        RECT  0 57.312 0.084 57.336 ;
    END
  END xq[356]
  PIN xq[357]
    DIRECTION INPUT ;
    USE SIGNAL ;
    PORT
      LAYER M4 ;
        RECT  0 57.36 0.084 57.384 ;
    END
  END xq[357]
  PIN xq[358]
    DIRECTION INPUT ;
    USE SIGNAL ;
    PORT
      LAYER M4 ;
        RECT  0 57.408 0.084 57.432 ;
    END
  END xq[358]
  PIN xq[359]
    DIRECTION INPUT ;
    USE SIGNAL ;
    PORT
      LAYER M4 ;
        RECT  0 57.456 0.084 57.48 ;
    END
  END xq[359]
  PIN xq[35]
    DIRECTION INPUT ;
    USE SIGNAL ;
    PORT
      LAYER M4 ;
        RECT  0 41.904 0.084 41.928 ;
    END
  END xq[35]
  PIN xq[360]
    DIRECTION INPUT ;
    USE SIGNAL ;
    PORT
      LAYER M4 ;
        RECT  0 57.504 0.084 57.528 ;
    END
  END xq[360]
  PIN xq[361]
    DIRECTION INPUT ;
    USE SIGNAL ;
    PORT
      LAYER M4 ;
        RECT  0 57.552 0.084 57.576 ;
    END
  END xq[361]
  PIN xq[362]
    DIRECTION INPUT ;
    USE SIGNAL ;
    PORT
      LAYER M4 ;
        RECT  0 57.6 0.084 57.624 ;
    END
  END xq[362]
  PIN xq[363]
    DIRECTION INPUT ;
    USE SIGNAL ;
    PORT
      LAYER M4 ;
        RECT  0 57.648 0.084 57.672 ;
    END
  END xq[363]
  PIN xq[364]
    DIRECTION INPUT ;
    USE SIGNAL ;
    PORT
      LAYER M4 ;
        RECT  0 57.696 0.084 57.72 ;
    END
  END xq[364]
  PIN xq[365]
    DIRECTION INPUT ;
    USE SIGNAL ;
    PORT
      LAYER M4 ;
        RECT  0 57.744 0.084 57.768 ;
    END
  END xq[365]
  PIN xq[366]
    DIRECTION INPUT ;
    USE SIGNAL ;
    PORT
      LAYER M4 ;
        RECT  0 57.792 0.084 57.816 ;
    END
  END xq[366]
  PIN xq[367]
    DIRECTION INPUT ;
    USE SIGNAL ;
    PORT
      LAYER M4 ;
        RECT  0 57.84 0.084 57.864 ;
    END
  END xq[367]
  PIN xq[368]
    DIRECTION INPUT ;
    USE SIGNAL ;
    PORT
      LAYER M4 ;
        RECT  0 57.888 0.084 57.912 ;
    END
  END xq[368]
  PIN xq[369]
    DIRECTION INPUT ;
    USE SIGNAL ;
    PORT
      LAYER M4 ;
        RECT  0 57.936 0.084 57.96 ;
    END
  END xq[369]
  PIN xq[36]
    DIRECTION INPUT ;
    USE SIGNAL ;
    PORT
      LAYER M4 ;
        RECT  0 41.952 0.084 41.976 ;
    END
  END xq[36]
  PIN xq[370]
    DIRECTION INPUT ;
    USE SIGNAL ;
    PORT
      LAYER M4 ;
        RECT  0 57.984 0.084 58.008 ;
    END
  END xq[370]
  PIN xq[371]
    DIRECTION INPUT ;
    USE SIGNAL ;
    PORT
      LAYER M4 ;
        RECT  0 58.032 0.084 58.056 ;
    END
  END xq[371]
  PIN xq[372]
    DIRECTION INPUT ;
    USE SIGNAL ;
    PORT
      LAYER M4 ;
        RECT  0 58.08 0.084 58.104 ;
    END
  END xq[372]
  PIN xq[373]
    DIRECTION INPUT ;
    USE SIGNAL ;
    PORT
      LAYER M4 ;
        RECT  0 58.128 0.084 58.152 ;
    END
  END xq[373]
  PIN xq[374]
    DIRECTION INPUT ;
    USE SIGNAL ;
    PORT
      LAYER M4 ;
        RECT  0 58.176 0.084 58.2 ;
    END
  END xq[374]
  PIN xq[375]
    DIRECTION INPUT ;
    USE SIGNAL ;
    PORT
      LAYER M4 ;
        RECT  0 58.224 0.084 58.248 ;
    END
  END xq[375]
  PIN xq[376]
    DIRECTION INPUT ;
    USE SIGNAL ;
    PORT
      LAYER M4 ;
        RECT  0 58.272 0.084 58.296 ;
    END
  END xq[376]
  PIN xq[377]
    DIRECTION INPUT ;
    USE SIGNAL ;
    PORT
      LAYER M4 ;
        RECT  0 58.32 0.084 58.344 ;
    END
  END xq[377]
  PIN xq[378]
    DIRECTION INPUT ;
    USE SIGNAL ;
    PORT
      LAYER M4 ;
        RECT  0 58.368 0.084 58.392 ;
    END
  END xq[378]
  PIN xq[379]
    DIRECTION INPUT ;
    USE SIGNAL ;
    PORT
      LAYER M4 ;
        RECT  0 58.416 0.084 58.44 ;
    END
  END xq[379]
  PIN xq[37]
    DIRECTION INPUT ;
    USE SIGNAL ;
    PORT
      LAYER M4 ;
        RECT  0 42 0.084 42.024 ;
    END
  END xq[37]
  PIN xq[380]
    DIRECTION INPUT ;
    USE SIGNAL ;
    PORT
      LAYER M4 ;
        RECT  0 58.464 0.084 58.488 ;
    END
  END xq[380]
  PIN xq[381]
    DIRECTION INPUT ;
    USE SIGNAL ;
    PORT
      LAYER M4 ;
        RECT  0 58.512 0.084 58.536 ;
    END
  END xq[381]
  PIN xq[382]
    DIRECTION INPUT ;
    USE SIGNAL ;
    PORT
      LAYER M4 ;
        RECT  0 58.56 0.084 58.584 ;
    END
  END xq[382]
  PIN xq[383]
    DIRECTION INPUT ;
    USE SIGNAL ;
    PORT
      LAYER M4 ;
        RECT  0 58.608 0.084 58.632 ;
    END
  END xq[383]
  PIN xq[384]
    DIRECTION INPUT ;
    USE SIGNAL ;
    PORT
      LAYER M4 ;
        RECT  0 58.656 0.084 58.68 ;
    END
  END xq[384]
  PIN xq[385]
    DIRECTION INPUT ;
    USE SIGNAL ;
    PORT
      LAYER M4 ;
        RECT  0 58.704 0.084 58.728 ;
    END
  END xq[385]
  PIN xq[386]
    DIRECTION INPUT ;
    USE SIGNAL ;
    PORT
      LAYER M4 ;
        RECT  0 58.752 0.084 58.776 ;
    END
  END xq[386]
  PIN xq[387]
    DIRECTION INPUT ;
    USE SIGNAL ;
    PORT
      LAYER M4 ;
        RECT  0 58.8 0.084 58.824 ;
    END
  END xq[387]
  PIN xq[388]
    DIRECTION INPUT ;
    USE SIGNAL ;
    PORT
      LAYER M4 ;
        RECT  0 58.848 0.084 58.872 ;
    END
  END xq[388]
  PIN xq[389]
    DIRECTION INPUT ;
    USE SIGNAL ;
    PORT
      LAYER M4 ;
        RECT  0 58.896 0.084 58.92 ;
    END
  END xq[389]
  PIN xq[38]
    DIRECTION INPUT ;
    USE SIGNAL ;
    PORT
      LAYER M4 ;
        RECT  0 42.048 0.084 42.072 ;
    END
  END xq[38]
  PIN xq[390]
    DIRECTION INPUT ;
    USE SIGNAL ;
    PORT
      LAYER M4 ;
        RECT  0 58.944 0.084 58.968 ;
    END
  END xq[390]
  PIN xq[391]
    DIRECTION INPUT ;
    USE SIGNAL ;
    PORT
      LAYER M4 ;
        RECT  0 58.992 0.084 59.016 ;
    END
  END xq[391]
  PIN xq[392]
    DIRECTION INPUT ;
    USE SIGNAL ;
    PORT
      LAYER M4 ;
        RECT  0 59.04 0.084 59.064 ;
    END
  END xq[392]
  PIN xq[393]
    DIRECTION INPUT ;
    USE SIGNAL ;
    PORT
      LAYER M4 ;
        RECT  0 59.088 0.084 59.112 ;
    END
  END xq[393]
  PIN xq[394]
    DIRECTION INPUT ;
    USE SIGNAL ;
    PORT
      LAYER M4 ;
        RECT  0 59.136 0.084 59.16 ;
    END
  END xq[394]
  PIN xq[395]
    DIRECTION INPUT ;
    USE SIGNAL ;
    PORT
      LAYER M4 ;
        RECT  0 59.184 0.084 59.208 ;
    END
  END xq[395]
  PIN xq[396]
    DIRECTION INPUT ;
    USE SIGNAL ;
    PORT
      LAYER M4 ;
        RECT  0 59.232 0.084 59.256 ;
    END
  END xq[396]
  PIN xq[397]
    DIRECTION INPUT ;
    USE SIGNAL ;
    PORT
      LAYER M4 ;
        RECT  0 59.28 0.084 59.304 ;
    END
  END xq[397]
  PIN xq[398]
    DIRECTION INPUT ;
    USE SIGNAL ;
    PORT
      LAYER M4 ;
        RECT  0 59.328 0.084 59.352 ;
    END
  END xq[398]
  PIN xq[399]
    DIRECTION INPUT ;
    USE SIGNAL ;
    PORT
      LAYER M4 ;
        RECT  0 59.376 0.084 59.4 ;
    END
  END xq[399]
  PIN xq[39]
    DIRECTION INPUT ;
    USE SIGNAL ;
    PORT
      LAYER M4 ;
        RECT  0 42.096 0.084 42.12 ;
    END
  END xq[39]
  PIN xq[3]
    DIRECTION INPUT ;
    USE SIGNAL ;
    PORT
      LAYER M4 ;
        RECT  0 40.368 0.084 40.392 ;
    END
  END xq[3]
  PIN xq[400]
    DIRECTION INPUT ;
    USE SIGNAL ;
    PORT
      LAYER M4 ;
        RECT  0 59.424 0.084 59.448 ;
    END
  END xq[400]
  PIN xq[401]
    DIRECTION INPUT ;
    USE SIGNAL ;
    PORT
      LAYER M4 ;
        RECT  0 59.472 0.084 59.496 ;
    END
  END xq[401]
  PIN xq[402]
    DIRECTION INPUT ;
    USE SIGNAL ;
    PORT
      LAYER M4 ;
        RECT  0 59.52 0.084 59.544 ;
    END
  END xq[402]
  PIN xq[403]
    DIRECTION INPUT ;
    USE SIGNAL ;
    PORT
      LAYER M4 ;
        RECT  0 59.568 0.084 59.592 ;
    END
  END xq[403]
  PIN xq[404]
    DIRECTION INPUT ;
    USE SIGNAL ;
    PORT
      LAYER M4 ;
        RECT  0 59.616 0.084 59.64 ;
    END
  END xq[404]
  PIN xq[405]
    DIRECTION INPUT ;
    USE SIGNAL ;
    PORT
      LAYER M4 ;
        RECT  0 59.664 0.084 59.688 ;
    END
  END xq[405]
  PIN xq[406]
    DIRECTION INPUT ;
    USE SIGNAL ;
    PORT
      LAYER M4 ;
        RECT  0 59.712 0.084 59.736 ;
    END
  END xq[406]
  PIN xq[407]
    DIRECTION INPUT ;
    USE SIGNAL ;
    PORT
      LAYER M4 ;
        RECT  0 59.76 0.084 59.784 ;
    END
  END xq[407]
  PIN xq[408]
    DIRECTION INPUT ;
    USE SIGNAL ;
    PORT
      LAYER M4 ;
        RECT  0 59.808 0.084 59.832 ;
    END
  END xq[408]
  PIN xq[409]
    DIRECTION INPUT ;
    USE SIGNAL ;
    PORT
      LAYER M4 ;
        RECT  0 59.856 0.084 59.88 ;
    END
  END xq[409]
  PIN xq[40]
    DIRECTION INPUT ;
    USE SIGNAL ;
    PORT
      LAYER M4 ;
        RECT  0 42.144 0.084 42.168 ;
    END
  END xq[40]
  PIN xq[410]
    DIRECTION INPUT ;
    USE SIGNAL ;
    PORT
      LAYER M4 ;
        RECT  0 59.904 0.084 59.928 ;
    END
  END xq[410]
  PIN xq[411]
    DIRECTION INPUT ;
    USE SIGNAL ;
    PORT
      LAYER M4 ;
        RECT  0 59.952 0.084 59.976 ;
    END
  END xq[411]
  PIN xq[412]
    DIRECTION INPUT ;
    USE SIGNAL ;
    PORT
      LAYER M4 ;
        RECT  0 60 0.084 60.024 ;
    END
  END xq[412]
  PIN xq[413]
    DIRECTION INPUT ;
    USE SIGNAL ;
    PORT
      LAYER M4 ;
        RECT  0 60.048 0.084 60.072 ;
    END
  END xq[413]
  PIN xq[414]
    DIRECTION INPUT ;
    USE SIGNAL ;
    PORT
      LAYER M4 ;
        RECT  0 60.096 0.084 60.12 ;
    END
  END xq[414]
  PIN xq[415]
    DIRECTION INPUT ;
    USE SIGNAL ;
    PORT
      LAYER M4 ;
        RECT  0 60.144 0.084 60.168 ;
    END
  END xq[415]
  PIN xq[416]
    DIRECTION INPUT ;
    USE SIGNAL ;
    PORT
      LAYER M4 ;
        RECT  0 60.192 0.084 60.216 ;
    END
  END xq[416]
  PIN xq[417]
    DIRECTION INPUT ;
    USE SIGNAL ;
    PORT
      LAYER M4 ;
        RECT  0 60.24 0.084 60.264 ;
    END
  END xq[417]
  PIN xq[418]
    DIRECTION INPUT ;
    USE SIGNAL ;
    PORT
      LAYER M4 ;
        RECT  0 60.288 0.084 60.312 ;
    END
  END xq[418]
  PIN xq[419]
    DIRECTION INPUT ;
    USE SIGNAL ;
    PORT
      LAYER M4 ;
        RECT  0 60.336 0.084 60.36 ;
    END
  END xq[419]
  PIN xq[41]
    DIRECTION INPUT ;
    USE SIGNAL ;
    PORT
      LAYER M4 ;
        RECT  0 42.192 0.084 42.216 ;
    END
  END xq[41]
  PIN xq[420]
    DIRECTION INPUT ;
    USE SIGNAL ;
    PORT
      LAYER M4 ;
        RECT  0 60.384 0.084 60.408 ;
    END
  END xq[420]
  PIN xq[421]
    DIRECTION INPUT ;
    USE SIGNAL ;
    PORT
      LAYER M4 ;
        RECT  0 60.432 0.084 60.456 ;
    END
  END xq[421]
  PIN xq[422]
    DIRECTION INPUT ;
    USE SIGNAL ;
    PORT
      LAYER M4 ;
        RECT  0 60.48 0.084 60.504 ;
    END
  END xq[422]
  PIN xq[423]
    DIRECTION INPUT ;
    USE SIGNAL ;
    PORT
      LAYER M4 ;
        RECT  0 60.528 0.084 60.552 ;
    END
  END xq[423]
  PIN xq[424]
    DIRECTION INPUT ;
    USE SIGNAL ;
    PORT
      LAYER M4 ;
        RECT  0 60.576 0.084 60.6 ;
    END
  END xq[424]
  PIN xq[425]
    DIRECTION INPUT ;
    USE SIGNAL ;
    PORT
      LAYER M4 ;
        RECT  0 60.624 0.084 60.648 ;
    END
  END xq[425]
  PIN xq[426]
    DIRECTION INPUT ;
    USE SIGNAL ;
    PORT
      LAYER M4 ;
        RECT  0 60.672 0.084 60.696 ;
    END
  END xq[426]
  PIN xq[427]
    DIRECTION INPUT ;
    USE SIGNAL ;
    PORT
      LAYER M4 ;
        RECT  0 60.72 0.084 60.744 ;
    END
  END xq[427]
  PIN xq[428]
    DIRECTION INPUT ;
    USE SIGNAL ;
    PORT
      LAYER M4 ;
        RECT  0 60.768 0.084 60.792 ;
    END
  END xq[428]
  PIN xq[429]
    DIRECTION INPUT ;
    USE SIGNAL ;
    PORT
      LAYER M4 ;
        RECT  0 60.816 0.084 60.84 ;
    END
  END xq[429]
  PIN xq[42]
    DIRECTION INPUT ;
    USE SIGNAL ;
    PORT
      LAYER M4 ;
        RECT  0 42.24 0.084 42.264 ;
    END
  END xq[42]
  PIN xq[430]
    DIRECTION INPUT ;
    USE SIGNAL ;
    PORT
      LAYER M4 ;
        RECT  0 60.864 0.084 60.888 ;
    END
  END xq[430]
  PIN xq[431]
    DIRECTION INPUT ;
    USE SIGNAL ;
    PORT
      LAYER M4 ;
        RECT  0 60.912 0.084 60.936 ;
    END
  END xq[431]
  PIN xq[432]
    DIRECTION INPUT ;
    USE SIGNAL ;
    PORT
      LAYER M4 ;
        RECT  0 60.96 0.084 60.984 ;
    END
  END xq[432]
  PIN xq[433]
    DIRECTION INPUT ;
    USE SIGNAL ;
    PORT
      LAYER M4 ;
        RECT  0 61.008 0.084 61.032 ;
    END
  END xq[433]
  PIN xq[434]
    DIRECTION INPUT ;
    USE SIGNAL ;
    PORT
      LAYER M4 ;
        RECT  0 61.056 0.084 61.08 ;
    END
  END xq[434]
  PIN xq[435]
    DIRECTION INPUT ;
    USE SIGNAL ;
    PORT
      LAYER M4 ;
        RECT  0 61.104 0.084 61.128 ;
    END
  END xq[435]
  PIN xq[436]
    DIRECTION INPUT ;
    USE SIGNAL ;
    PORT
      LAYER M4 ;
        RECT  0 61.152 0.084 61.176 ;
    END
  END xq[436]
  PIN xq[437]
    DIRECTION INPUT ;
    USE SIGNAL ;
    PORT
      LAYER M4 ;
        RECT  0 61.2 0.084 61.224 ;
    END
  END xq[437]
  PIN xq[438]
    DIRECTION INPUT ;
    USE SIGNAL ;
    PORT
      LAYER M4 ;
        RECT  0 61.248 0.084 61.272 ;
    END
  END xq[438]
  PIN xq[439]
    DIRECTION INPUT ;
    USE SIGNAL ;
    PORT
      LAYER M4 ;
        RECT  0 61.296 0.084 61.32 ;
    END
  END xq[439]
  PIN xq[43]
    DIRECTION INPUT ;
    USE SIGNAL ;
    PORT
      LAYER M4 ;
        RECT  0 42.288 0.084 42.312 ;
    END
  END xq[43]
  PIN xq[440]
    DIRECTION INPUT ;
    USE SIGNAL ;
    PORT
      LAYER M4 ;
        RECT  0 61.344 0.084 61.368 ;
    END
  END xq[440]
  PIN xq[441]
    DIRECTION INPUT ;
    USE SIGNAL ;
    PORT
      LAYER M4 ;
        RECT  0 61.392 0.084 61.416 ;
    END
  END xq[441]
  PIN xq[442]
    DIRECTION INPUT ;
    USE SIGNAL ;
    PORT
      LAYER M4 ;
        RECT  0 61.44 0.084 61.464 ;
    END
  END xq[442]
  PIN xq[443]
    DIRECTION INPUT ;
    USE SIGNAL ;
    PORT
      LAYER M4 ;
        RECT  0 61.488 0.084 61.512 ;
    END
  END xq[443]
  PIN xq[444]
    DIRECTION INPUT ;
    USE SIGNAL ;
    PORT
      LAYER M4 ;
        RECT  0 61.536 0.084 61.56 ;
    END
  END xq[444]
  PIN xq[445]
    DIRECTION INPUT ;
    USE SIGNAL ;
    PORT
      LAYER M4 ;
        RECT  0 61.584 0.084 61.608 ;
    END
  END xq[445]
  PIN xq[446]
    DIRECTION INPUT ;
    USE SIGNAL ;
    PORT
      LAYER M4 ;
        RECT  0 61.632 0.084 61.656 ;
    END
  END xq[446]
  PIN xq[447]
    DIRECTION INPUT ;
    USE SIGNAL ;
    PORT
      LAYER M4 ;
        RECT  0 61.68 0.084 61.704 ;
    END
  END xq[447]
  PIN xq[448]
    DIRECTION INPUT ;
    USE SIGNAL ;
    PORT
      LAYER M4 ;
        RECT  0 61.728 0.084 61.752 ;
    END
  END xq[448]
  PIN xq[449]
    DIRECTION INPUT ;
    USE SIGNAL ;
    PORT
      LAYER M4 ;
        RECT  0 61.776 0.084 61.8 ;
    END
  END xq[449]
  PIN xq[44]
    DIRECTION INPUT ;
    USE SIGNAL ;
    PORT
      LAYER M4 ;
        RECT  0 42.336 0.084 42.36 ;
    END
  END xq[44]
  PIN xq[450]
    DIRECTION INPUT ;
    USE SIGNAL ;
    PORT
      LAYER M4 ;
        RECT  0 61.824 0.084 61.848 ;
    END
  END xq[450]
  PIN xq[451]
    DIRECTION INPUT ;
    USE SIGNAL ;
    PORT
      LAYER M4 ;
        RECT  0 61.872 0.084 61.896 ;
    END
  END xq[451]
  PIN xq[452]
    DIRECTION INPUT ;
    USE SIGNAL ;
    PORT
      LAYER M4 ;
        RECT  0 61.92 0.084 61.944 ;
    END
  END xq[452]
  PIN xq[453]
    DIRECTION INPUT ;
    USE SIGNAL ;
    PORT
      LAYER M4 ;
        RECT  0 61.968 0.084 61.992 ;
    END
  END xq[453]
  PIN xq[454]
    DIRECTION INPUT ;
    USE SIGNAL ;
    PORT
      LAYER M4 ;
        RECT  0 62.016 0.084 62.04 ;
    END
  END xq[454]
  PIN xq[455]
    DIRECTION INPUT ;
    USE SIGNAL ;
    PORT
      LAYER M4 ;
        RECT  0 62.064 0.084 62.088 ;
    END
  END xq[455]
  PIN xq[456]
    DIRECTION INPUT ;
    USE SIGNAL ;
    PORT
      LAYER M4 ;
        RECT  0 62.112 0.084 62.136 ;
    END
  END xq[456]
  PIN xq[457]
    DIRECTION INPUT ;
    USE SIGNAL ;
    PORT
      LAYER M4 ;
        RECT  0 62.16 0.084 62.184 ;
    END
  END xq[457]
  PIN xq[458]
    DIRECTION INPUT ;
    USE SIGNAL ;
    PORT
      LAYER M4 ;
        RECT  0 62.208 0.084 62.232 ;
    END
  END xq[458]
  PIN xq[459]
    DIRECTION INPUT ;
    USE SIGNAL ;
    PORT
      LAYER M4 ;
        RECT  0 62.256 0.084 62.28 ;
    END
  END xq[459]
  PIN xq[45]
    DIRECTION INPUT ;
    USE SIGNAL ;
    PORT
      LAYER M4 ;
        RECT  0 42.384 0.084 42.408 ;
    END
  END xq[45]
  PIN xq[460]
    DIRECTION INPUT ;
    USE SIGNAL ;
    PORT
      LAYER M4 ;
        RECT  0 62.304 0.084 62.328 ;
    END
  END xq[460]
  PIN xq[461]
    DIRECTION INPUT ;
    USE SIGNAL ;
    PORT
      LAYER M4 ;
        RECT  0 62.352 0.084 62.376 ;
    END
  END xq[461]
  PIN xq[462]
    DIRECTION INPUT ;
    USE SIGNAL ;
    PORT
      LAYER M4 ;
        RECT  0 62.4 0.084 62.424 ;
    END
  END xq[462]
  PIN xq[463]
    DIRECTION INPUT ;
    USE SIGNAL ;
    PORT
      LAYER M4 ;
        RECT  0 62.448 0.084 62.472 ;
    END
  END xq[463]
  PIN xq[464]
    DIRECTION INPUT ;
    USE SIGNAL ;
    PORT
      LAYER M4 ;
        RECT  0 62.496 0.084 62.52 ;
    END
  END xq[464]
  PIN xq[465]
    DIRECTION INPUT ;
    USE SIGNAL ;
    PORT
      LAYER M4 ;
        RECT  0 62.544 0.084 62.568 ;
    END
  END xq[465]
  PIN xq[466]
    DIRECTION INPUT ;
    USE SIGNAL ;
    PORT
      LAYER M4 ;
        RECT  0 62.592 0.084 62.616 ;
    END
  END xq[466]
  PIN xq[467]
    DIRECTION INPUT ;
    USE SIGNAL ;
    PORT
      LAYER M4 ;
        RECT  0 62.64 0.084 62.664 ;
    END
  END xq[467]
  PIN xq[468]
    DIRECTION INPUT ;
    USE SIGNAL ;
    PORT
      LAYER M4 ;
        RECT  0 62.688 0.084 62.712 ;
    END
  END xq[468]
  PIN xq[469]
    DIRECTION INPUT ;
    USE SIGNAL ;
    PORT
      LAYER M4 ;
        RECT  0 62.736 0.084 62.76 ;
    END
  END xq[469]
  PIN xq[46]
    DIRECTION INPUT ;
    USE SIGNAL ;
    PORT
      LAYER M4 ;
        RECT  0 42.432 0.084 42.456 ;
    END
  END xq[46]
  PIN xq[470]
    DIRECTION INPUT ;
    USE SIGNAL ;
    PORT
      LAYER M4 ;
        RECT  0 62.784 0.084 62.808 ;
    END
  END xq[470]
  PIN xq[471]
    DIRECTION INPUT ;
    USE SIGNAL ;
    PORT
      LAYER M4 ;
        RECT  0 62.832 0.084 62.856 ;
    END
  END xq[471]
  PIN xq[472]
    DIRECTION INPUT ;
    USE SIGNAL ;
    PORT
      LAYER M4 ;
        RECT  0 62.88 0.084 62.904 ;
    END
  END xq[472]
  PIN xq[473]
    DIRECTION INPUT ;
    USE SIGNAL ;
    PORT
      LAYER M4 ;
        RECT  0 62.928 0.084 62.952 ;
    END
  END xq[473]
  PIN xq[474]
    DIRECTION INPUT ;
    USE SIGNAL ;
    PORT
      LAYER M4 ;
        RECT  0 62.976 0.084 63 ;
    END
  END xq[474]
  PIN xq[475]
    DIRECTION INPUT ;
    USE SIGNAL ;
    PORT
      LAYER M4 ;
        RECT  0 63.024 0.084 63.048 ;
    END
  END xq[475]
  PIN xq[476]
    DIRECTION INPUT ;
    USE SIGNAL ;
    PORT
      LAYER M4 ;
        RECT  0 63.072 0.084 63.096 ;
    END
  END xq[476]
  PIN xq[477]
    DIRECTION INPUT ;
    USE SIGNAL ;
    PORT
      LAYER M4 ;
        RECT  0 63.12 0.084 63.144 ;
    END
  END xq[477]
  PIN xq[478]
    DIRECTION INPUT ;
    USE SIGNAL ;
    PORT
      LAYER M4 ;
        RECT  0 63.168 0.084 63.192 ;
    END
  END xq[478]
  PIN xq[479]
    DIRECTION INPUT ;
    USE SIGNAL ;
    PORT
      LAYER M4 ;
        RECT  0 63.216 0.084 63.24 ;
    END
  END xq[479]
  PIN xq[47]
    DIRECTION INPUT ;
    USE SIGNAL ;
    PORT
      LAYER M4 ;
        RECT  0 42.48 0.084 42.504 ;
    END
  END xq[47]
  PIN xq[480]
    DIRECTION INPUT ;
    USE SIGNAL ;
    PORT
      LAYER M4 ;
        RECT  0 63.264 0.084 63.288 ;
    END
  END xq[480]
  PIN xq[481]
    DIRECTION INPUT ;
    USE SIGNAL ;
    PORT
      LAYER M4 ;
        RECT  0 63.312 0.084 63.336 ;
    END
  END xq[481]
  PIN xq[482]
    DIRECTION INPUT ;
    USE SIGNAL ;
    PORT
      LAYER M4 ;
        RECT  0 63.36 0.084 63.384 ;
    END
  END xq[482]
  PIN xq[483]
    DIRECTION INPUT ;
    USE SIGNAL ;
    PORT
      LAYER M4 ;
        RECT  0 63.408 0.084 63.432 ;
    END
  END xq[483]
  PIN xq[484]
    DIRECTION INPUT ;
    USE SIGNAL ;
    PORT
      LAYER M4 ;
        RECT  0 63.456 0.084 63.48 ;
    END
  END xq[484]
  PIN xq[485]
    DIRECTION INPUT ;
    USE SIGNAL ;
    PORT
      LAYER M4 ;
        RECT  0 63.504 0.084 63.528 ;
    END
  END xq[485]
  PIN xq[486]
    DIRECTION INPUT ;
    USE SIGNAL ;
    PORT
      LAYER M4 ;
        RECT  0 63.552 0.084 63.576 ;
    END
  END xq[486]
  PIN xq[487]
    DIRECTION INPUT ;
    USE SIGNAL ;
    PORT
      LAYER M4 ;
        RECT  0 63.6 0.084 63.624 ;
    END
  END xq[487]
  PIN xq[488]
    DIRECTION INPUT ;
    USE SIGNAL ;
    PORT
      LAYER M4 ;
        RECT  0 63.648 0.084 63.672 ;
    END
  END xq[488]
  PIN xq[489]
    DIRECTION INPUT ;
    USE SIGNAL ;
    PORT
      LAYER M4 ;
        RECT  0 63.696 0.084 63.72 ;
    END
  END xq[489]
  PIN xq[48]
    DIRECTION INPUT ;
    USE SIGNAL ;
    PORT
      LAYER M4 ;
        RECT  0 42.528 0.084 42.552 ;
    END
  END xq[48]
  PIN xq[490]
    DIRECTION INPUT ;
    USE SIGNAL ;
    PORT
      LAYER M4 ;
        RECT  0 63.744 0.084 63.768 ;
    END
  END xq[490]
  PIN xq[491]
    DIRECTION INPUT ;
    USE SIGNAL ;
    PORT
      LAYER M4 ;
        RECT  0 63.792 0.084 63.816 ;
    END
  END xq[491]
  PIN xq[492]
    DIRECTION INPUT ;
    USE SIGNAL ;
    PORT
      LAYER M4 ;
        RECT  0 63.84 0.084 63.864 ;
    END
  END xq[492]
  PIN xq[493]
    DIRECTION INPUT ;
    USE SIGNAL ;
    PORT
      LAYER M4 ;
        RECT  0 63.888 0.084 63.912 ;
    END
  END xq[493]
  PIN xq[494]
    DIRECTION INPUT ;
    USE SIGNAL ;
    PORT
      LAYER M4 ;
        RECT  0 63.936 0.084 63.96 ;
    END
  END xq[494]
  PIN xq[495]
    DIRECTION INPUT ;
    USE SIGNAL ;
    PORT
      LAYER M4 ;
        RECT  0 63.984 0.084 64.008 ;
    END
  END xq[495]
  PIN xq[496]
    DIRECTION INPUT ;
    USE SIGNAL ;
    PORT
      LAYER M4 ;
        RECT  0 64.032 0.084 64.056 ;
    END
  END xq[496]
  PIN xq[497]
    DIRECTION INPUT ;
    USE SIGNAL ;
    PORT
      LAYER M4 ;
        RECT  0 64.08 0.084 64.104 ;
    END
  END xq[497]
  PIN xq[498]
    DIRECTION INPUT ;
    USE SIGNAL ;
    PORT
      LAYER M4 ;
        RECT  0 64.128 0.084 64.152 ;
    END
  END xq[498]
  PIN xq[499]
    DIRECTION INPUT ;
    USE SIGNAL ;
    PORT
      LAYER M4 ;
        RECT  0 64.176 0.084 64.2 ;
    END
  END xq[499]
  PIN xq[49]
    DIRECTION INPUT ;
    USE SIGNAL ;
    PORT
      LAYER M4 ;
        RECT  0 42.576 0.084 42.6 ;
    END
  END xq[49]
  PIN xq[4]
    DIRECTION INPUT ;
    USE SIGNAL ;
    PORT
      LAYER M4 ;
        RECT  0 40.416 0.084 40.44 ;
    END
  END xq[4]
  PIN xq[500]
    DIRECTION INPUT ;
    USE SIGNAL ;
    PORT
      LAYER M4 ;
        RECT  0 64.224 0.084 64.248 ;
    END
  END xq[500]
  PIN xq[501]
    DIRECTION INPUT ;
    USE SIGNAL ;
    PORT
      LAYER M4 ;
        RECT  0 64.272 0.084 64.296 ;
    END
  END xq[501]
  PIN xq[502]
    DIRECTION INPUT ;
    USE SIGNAL ;
    PORT
      LAYER M4 ;
        RECT  0 64.32 0.084 64.344 ;
    END
  END xq[502]
  PIN xq[503]
    DIRECTION INPUT ;
    USE SIGNAL ;
    PORT
      LAYER M4 ;
        RECT  0 64.368 0.084 64.392 ;
    END
  END xq[503]
  PIN xq[504]
    DIRECTION INPUT ;
    USE SIGNAL ;
    PORT
      LAYER M4 ;
        RECT  0 64.416 0.084 64.44 ;
    END
  END xq[504]
  PIN xq[505]
    DIRECTION INPUT ;
    USE SIGNAL ;
    PORT
      LAYER M4 ;
        RECT  0 64.464 0.084 64.488 ;
    END
  END xq[505]
  PIN xq[506]
    DIRECTION INPUT ;
    USE SIGNAL ;
    PORT
      LAYER M4 ;
        RECT  0 64.512 0.084 64.536 ;
    END
  END xq[506]
  PIN xq[507]
    DIRECTION INPUT ;
    USE SIGNAL ;
    PORT
      LAYER M4 ;
        RECT  0 64.56 0.084 64.584 ;
    END
  END xq[507]
  PIN xq[508]
    DIRECTION INPUT ;
    USE SIGNAL ;
    PORT
      LAYER M4 ;
        RECT  0 64.608 0.084 64.632 ;
    END
  END xq[508]
  PIN xq[509]
    DIRECTION INPUT ;
    USE SIGNAL ;
    PORT
      LAYER M4 ;
        RECT  0 64.656 0.084 64.68 ;
    END
  END xq[509]
  PIN xq[50]
    DIRECTION INPUT ;
    USE SIGNAL ;
    PORT
      LAYER M4 ;
        RECT  0 42.624 0.084 42.648 ;
    END
  END xq[50]
  PIN xq[510]
    DIRECTION INPUT ;
    USE SIGNAL ;
    PORT
      LAYER M4 ;
        RECT  0 64.704 0.084 64.728 ;
    END
  END xq[510]
  PIN xq[511]
    DIRECTION INPUT ;
    USE SIGNAL ;
    PORT
      LAYER M4 ;
        RECT  0 64.752 0.084 64.776 ;
    END
  END xq[511]
  PIN xq[51]
    DIRECTION INPUT ;
    USE SIGNAL ;
    PORT
      LAYER M4 ;
        RECT  0 42.672 0.084 42.696 ;
    END
  END xq[51]
  PIN xq[52]
    DIRECTION INPUT ;
    USE SIGNAL ;
    PORT
      LAYER M4 ;
        RECT  0 42.72 0.084 42.744 ;
    END
  END xq[52]
  PIN xq[53]
    DIRECTION INPUT ;
    USE SIGNAL ;
    PORT
      LAYER M4 ;
        RECT  0 42.768 0.084 42.792 ;
    END
  END xq[53]
  PIN xq[54]
    DIRECTION INPUT ;
    USE SIGNAL ;
    PORT
      LAYER M4 ;
        RECT  0 42.816 0.084 42.84 ;
    END
  END xq[54]
  PIN xq[55]
    DIRECTION INPUT ;
    USE SIGNAL ;
    PORT
      LAYER M4 ;
        RECT  0 42.864 0.084 42.888 ;
    END
  END xq[55]
  PIN xq[56]
    DIRECTION INPUT ;
    USE SIGNAL ;
    PORT
      LAYER M4 ;
        RECT  0 42.912 0.084 42.936 ;
    END
  END xq[56]
  PIN xq[57]
    DIRECTION INPUT ;
    USE SIGNAL ;
    PORT
      LAYER M4 ;
        RECT  0 42.96 0.084 42.984 ;
    END
  END xq[57]
  PIN xq[58]
    DIRECTION INPUT ;
    USE SIGNAL ;
    PORT
      LAYER M4 ;
        RECT  0 43.008 0.084 43.032 ;
    END
  END xq[58]
  PIN xq[59]
    DIRECTION INPUT ;
    USE SIGNAL ;
    PORT
      LAYER M4 ;
        RECT  0 43.056 0.084 43.08 ;
    END
  END xq[59]
  PIN xq[5]
    DIRECTION INPUT ;
    USE SIGNAL ;
    PORT
      LAYER M4 ;
        RECT  0 40.464 0.084 40.488 ;
    END
  END xq[5]
  PIN xq[60]
    DIRECTION INPUT ;
    USE SIGNAL ;
    PORT
      LAYER M4 ;
        RECT  0 43.104 0.084 43.128 ;
    END
  END xq[60]
  PIN xq[61]
    DIRECTION INPUT ;
    USE SIGNAL ;
    PORT
      LAYER M4 ;
        RECT  0 43.152 0.084 43.176 ;
    END
  END xq[61]
  PIN xq[62]
    DIRECTION INPUT ;
    USE SIGNAL ;
    PORT
      LAYER M4 ;
        RECT  0 43.2 0.084 43.224 ;
    END
  END xq[62]
  PIN xq[63]
    DIRECTION INPUT ;
    USE SIGNAL ;
    PORT
      LAYER M4 ;
        RECT  0 43.248 0.084 43.272 ;
    END
  END xq[63]
  PIN xq[64]
    DIRECTION INPUT ;
    USE SIGNAL ;
    PORT
      LAYER M4 ;
        RECT  0 43.296 0.084 43.32 ;
    END
  END xq[64]
  PIN xq[65]
    DIRECTION INPUT ;
    USE SIGNAL ;
    PORT
      LAYER M4 ;
        RECT  0 43.344 0.084 43.368 ;
    END
  END xq[65]
  PIN xq[66]
    DIRECTION INPUT ;
    USE SIGNAL ;
    PORT
      LAYER M4 ;
        RECT  0 43.392 0.084 43.416 ;
    END
  END xq[66]
  PIN xq[67]
    DIRECTION INPUT ;
    USE SIGNAL ;
    PORT
      LAYER M4 ;
        RECT  0 43.44 0.084 43.464 ;
    END
  END xq[67]
  PIN xq[68]
    DIRECTION INPUT ;
    USE SIGNAL ;
    PORT
      LAYER M4 ;
        RECT  0 43.488 0.084 43.512 ;
    END
  END xq[68]
  PIN xq[69]
    DIRECTION INPUT ;
    USE SIGNAL ;
    PORT
      LAYER M4 ;
        RECT  0 43.536 0.084 43.56 ;
    END
  END xq[69]
  PIN xq[6]
    DIRECTION INPUT ;
    USE SIGNAL ;
    PORT
      LAYER M4 ;
        RECT  0 40.512 0.084 40.536 ;
    END
  END xq[6]
  PIN xq[70]
    DIRECTION INPUT ;
    USE SIGNAL ;
    PORT
      LAYER M4 ;
        RECT  0 43.584 0.084 43.608 ;
    END
  END xq[70]
  PIN xq[71]
    DIRECTION INPUT ;
    USE SIGNAL ;
    PORT
      LAYER M4 ;
        RECT  0 43.632 0.084 43.656 ;
    END
  END xq[71]
  PIN xq[72]
    DIRECTION INPUT ;
    USE SIGNAL ;
    PORT
      LAYER M4 ;
        RECT  0 43.68 0.084 43.704 ;
    END
  END xq[72]
  PIN xq[73]
    DIRECTION INPUT ;
    USE SIGNAL ;
    PORT
      LAYER M4 ;
        RECT  0 43.728 0.084 43.752 ;
    END
  END xq[73]
  PIN xq[74]
    DIRECTION INPUT ;
    USE SIGNAL ;
    PORT
      LAYER M4 ;
        RECT  0 43.776 0.084 43.8 ;
    END
  END xq[74]
  PIN xq[75]
    DIRECTION INPUT ;
    USE SIGNAL ;
    PORT
      LAYER M4 ;
        RECT  0 43.824 0.084 43.848 ;
    END
  END xq[75]
  PIN xq[76]
    DIRECTION INPUT ;
    USE SIGNAL ;
    PORT
      LAYER M4 ;
        RECT  0 43.872 0.084 43.896 ;
    END
  END xq[76]
  PIN xq[77]
    DIRECTION INPUT ;
    USE SIGNAL ;
    PORT
      LAYER M4 ;
        RECT  0 43.92 0.084 43.944 ;
    END
  END xq[77]
  PIN xq[78]
    DIRECTION INPUT ;
    USE SIGNAL ;
    PORT
      LAYER M4 ;
        RECT  0 43.968 0.084 43.992 ;
    END
  END xq[78]
  PIN xq[79]
    DIRECTION INPUT ;
    USE SIGNAL ;
    PORT
      LAYER M4 ;
        RECT  0 44.016 0.084 44.04 ;
    END
  END xq[79]
  PIN xq[7]
    DIRECTION INPUT ;
    USE SIGNAL ;
    PORT
      LAYER M4 ;
        RECT  0 40.56 0.084 40.584 ;
    END
  END xq[7]
  PIN xq[80]
    DIRECTION INPUT ;
    USE SIGNAL ;
    PORT
      LAYER M4 ;
        RECT  0 44.064 0.084 44.088 ;
    END
  END xq[80]
  PIN xq[81]
    DIRECTION INPUT ;
    USE SIGNAL ;
    PORT
      LAYER M4 ;
        RECT  0 44.112 0.084 44.136 ;
    END
  END xq[81]
  PIN xq[82]
    DIRECTION INPUT ;
    USE SIGNAL ;
    PORT
      LAYER M4 ;
        RECT  0 44.16 0.084 44.184 ;
    END
  END xq[82]
  PIN xq[83]
    DIRECTION INPUT ;
    USE SIGNAL ;
    PORT
      LAYER M4 ;
        RECT  0 44.208 0.084 44.232 ;
    END
  END xq[83]
  PIN xq[84]
    DIRECTION INPUT ;
    USE SIGNAL ;
    PORT
      LAYER M4 ;
        RECT  0 44.256 0.084 44.28 ;
    END
  END xq[84]
  PIN xq[85]
    DIRECTION INPUT ;
    USE SIGNAL ;
    PORT
      LAYER M4 ;
        RECT  0 44.304 0.084 44.328 ;
    END
  END xq[85]
  PIN xq[86]
    DIRECTION INPUT ;
    USE SIGNAL ;
    PORT
      LAYER M4 ;
        RECT  0 44.352 0.084 44.376 ;
    END
  END xq[86]
  PIN xq[87]
    DIRECTION INPUT ;
    USE SIGNAL ;
    PORT
      LAYER M4 ;
        RECT  0 44.4 0.084 44.424 ;
    END
  END xq[87]
  PIN xq[88]
    DIRECTION INPUT ;
    USE SIGNAL ;
    PORT
      LAYER M4 ;
        RECT  0 44.448 0.084 44.472 ;
    END
  END xq[88]
  PIN xq[89]
    DIRECTION INPUT ;
    USE SIGNAL ;
    PORT
      LAYER M4 ;
        RECT  0 44.496 0.084 44.52 ;
    END
  END xq[89]
  PIN xq[8]
    DIRECTION INPUT ;
    USE SIGNAL ;
    PORT
      LAYER M4 ;
        RECT  0 40.608 0.084 40.632 ;
    END
  END xq[8]
  PIN xq[90]
    DIRECTION INPUT ;
    USE SIGNAL ;
    PORT
      LAYER M4 ;
        RECT  0 44.544 0.084 44.568 ;
    END
  END xq[90]
  PIN xq[91]
    DIRECTION INPUT ;
    USE SIGNAL ;
    PORT
      LAYER M4 ;
        RECT  0 44.592 0.084 44.616 ;
    END
  END xq[91]
  PIN xq[92]
    DIRECTION INPUT ;
    USE SIGNAL ;
    PORT
      LAYER M4 ;
        RECT  0 44.64 0.084 44.664 ;
    END
  END xq[92]
  PIN xq[93]
    DIRECTION INPUT ;
    USE SIGNAL ;
    PORT
      LAYER M4 ;
        RECT  0 44.688 0.084 44.712 ;
    END
  END xq[93]
  PIN xq[94]
    DIRECTION INPUT ;
    USE SIGNAL ;
    PORT
      LAYER M4 ;
        RECT  0 44.736 0.084 44.76 ;
    END
  END xq[94]
  PIN xq[95]
    DIRECTION INPUT ;
    USE SIGNAL ;
    PORT
      LAYER M4 ;
        RECT  0 44.784 0.084 44.808 ;
    END
  END xq[95]
  PIN xq[96]
    DIRECTION INPUT ;
    USE SIGNAL ;
    PORT
      LAYER M4 ;
        RECT  0 44.832 0.084 44.856 ;
    END
  END xq[96]
  PIN xq[97]
    DIRECTION INPUT ;
    USE SIGNAL ;
    PORT
      LAYER M4 ;
        RECT  0 44.88 0.084 44.904 ;
    END
  END xq[97]
  PIN xq[98]
    DIRECTION INPUT ;
    USE SIGNAL ;
    PORT
      LAYER M4 ;
        RECT  0 44.928 0.084 44.952 ;
    END
  END xq[98]
  PIN xq[99]
    DIRECTION INPUT ;
    USE SIGNAL ;
    PORT
      LAYER M4 ;
        RECT  0 44.976 0.084 45 ;
    END
  END xq[99]
  PIN xq[9]
    DIRECTION INPUT ;
    USE SIGNAL ;
    PORT
      LAYER M4 ;
        RECT  0 40.656 0.084 40.68 ;
    END
  END xq[9]
  PIN y[0]
    DIRECTION OUTPUT ;
    USE SIGNAL ;
    PORT
      LAYER M4 ;
        RECT  103.916 54.384 104 54.408 ;
    END
  END y[0]
  PIN y[10]
    DIRECTION OUTPUT ;
    USE SIGNAL ;
    PORT
      LAYER M4 ;
        RECT  103.916 54.864 104 54.888 ;
    END
  END y[10]
  PIN y[11]
    DIRECTION OUTPUT ;
    USE SIGNAL ;
    PORT
      LAYER M4 ;
        RECT  103.916 54.912 104 54.936 ;
    END
  END y[11]
  PIN y[12]
    DIRECTION OUTPUT ;
    USE SIGNAL ;
    PORT
      LAYER M4 ;
        RECT  103.916 54.96 104 54.984 ;
    END
  END y[12]
  PIN y[13]
    DIRECTION OUTPUT ;
    USE SIGNAL ;
    PORT
      LAYER M4 ;
        RECT  103.916 55.008 104 55.032 ;
    END
  END y[13]
  PIN y[14]
    DIRECTION OUTPUT ;
    USE SIGNAL ;
    PORT
      LAYER M4 ;
        RECT  103.916 55.056 104 55.08 ;
    END
  END y[14]
  PIN y[15]
    DIRECTION OUTPUT ;
    USE SIGNAL ;
    PORT
      LAYER M4 ;
        RECT  103.916 55.104 104 55.128 ;
    END
  END y[15]
  PIN y[16]
    DIRECTION OUTPUT ;
    USE SIGNAL ;
    PORT
      LAYER M4 ;
        RECT  103.916 55.152 104 55.176 ;
    END
  END y[16]
  PIN y[17]
    DIRECTION OUTPUT ;
    USE SIGNAL ;
    PORT
      LAYER M4 ;
        RECT  103.916 55.2 104 55.224 ;
    END
  END y[17]
  PIN y[18]
    DIRECTION OUTPUT ;
    USE SIGNAL ;
    PORT
      LAYER M4 ;
        RECT  103.916 55.248 104 55.272 ;
    END
  END y[18]
  PIN y[19]
    DIRECTION OUTPUT ;
    USE SIGNAL ;
    PORT
      LAYER M4 ;
        RECT  103.916 55.296 104 55.32 ;
    END
  END y[19]
  PIN y[1]
    DIRECTION OUTPUT ;
    USE SIGNAL ;
    PORT
      LAYER M4 ;
        RECT  103.916 54.432 104 54.456 ;
    END
  END y[1]
  PIN y[20]
    DIRECTION OUTPUT ;
    USE SIGNAL ;
    PORT
      LAYER M4 ;
        RECT  103.916 55.344 104 55.368 ;
    END
  END y[20]
  PIN y[21]
    DIRECTION OUTPUT ;
    USE SIGNAL ;
    PORT
      LAYER M4 ;
        RECT  103.916 55.392 104 55.416 ;
    END
  END y[21]
  PIN y[22]
    DIRECTION OUTPUT ;
    USE SIGNAL ;
    PORT
      LAYER M4 ;
        RECT  103.916 55.44 104 55.464 ;
    END
  END y[22]
  PIN y[23]
    DIRECTION OUTPUT ;
    USE SIGNAL ;
    PORT
      LAYER M4 ;
        RECT  103.916 55.488 104 55.512 ;
    END
  END y[23]
  PIN y[24]
    DIRECTION OUTPUT ;
    USE SIGNAL ;
    PORT
      LAYER M4 ;
        RECT  103.916 55.536 104 55.56 ;
    END
  END y[24]
  PIN y[25]
    DIRECTION OUTPUT ;
    USE SIGNAL ;
    PORT
      LAYER M4 ;
        RECT  103.916 55.584 104 55.608 ;
    END
  END y[25]
  PIN y[26]
    DIRECTION OUTPUT ;
    USE SIGNAL ;
    PORT
      LAYER M4 ;
        RECT  103.916 55.632 104 55.656 ;
    END
  END y[26]
  PIN y[27]
    DIRECTION OUTPUT ;
    USE SIGNAL ;
    PORT
      LAYER M4 ;
        RECT  103.916 55.68 104 55.704 ;
    END
  END y[27]
  PIN y[28]
    DIRECTION OUTPUT ;
    USE SIGNAL ;
    PORT
      LAYER M4 ;
        RECT  103.916 55.728 104 55.752 ;
    END
  END y[28]
  PIN y[29]
    DIRECTION OUTPUT ;
    USE SIGNAL ;
    PORT
      LAYER M4 ;
        RECT  103.916 55.776 104 55.8 ;
    END
  END y[29]
  PIN y[2]
    DIRECTION OUTPUT ;
    USE SIGNAL ;
    PORT
      LAYER M4 ;
        RECT  103.916 54.48 104 54.504 ;
    END
  END y[2]
  PIN y[30]
    DIRECTION OUTPUT ;
    USE SIGNAL ;
    PORT
      LAYER M4 ;
        RECT  103.916 55.824 104 55.848 ;
    END
  END y[30]
  PIN y[31]
    DIRECTION OUTPUT ;
    USE SIGNAL ;
    PORT
      LAYER M4 ;
        RECT  103.916 55.872 104 55.896 ;
    END
  END y[31]
  PIN y[3]
    DIRECTION OUTPUT ;
    USE SIGNAL ;
    PORT
      LAYER M4 ;
        RECT  103.916 54.528 104 54.552 ;
    END
  END y[3]
  PIN y[4]
    DIRECTION OUTPUT ;
    USE SIGNAL ;
    PORT
      LAYER M4 ;
        RECT  103.916 54.576 104 54.6 ;
    END
  END y[4]
  PIN y[5]
    DIRECTION OUTPUT ;
    USE SIGNAL ;
    PORT
      LAYER M4 ;
        RECT  103.916 54.624 104 54.648 ;
    END
  END y[5]
  PIN y[6]
    DIRECTION OUTPUT ;
    USE SIGNAL ;
    PORT
      LAYER M4 ;
        RECT  103.916 54.672 104 54.696 ;
    END
  END y[6]
  PIN y[7]
    DIRECTION OUTPUT ;
    USE SIGNAL ;
    PORT
      LAYER M4 ;
        RECT  103.916 54.72 104 54.744 ;
    END
  END y[7]
  PIN y[8]
    DIRECTION OUTPUT ;
    USE SIGNAL ;
    PORT
      LAYER M4 ;
        RECT  103.916 54.768 104 54.792 ;
    END
  END y[8]
  PIN y[9]
    DIRECTION OUTPUT ;
    USE SIGNAL ;
    PORT
      LAYER M4 ;
        RECT  103.916 54.816 104 54.84 ;
    END
  END y[9]
  PIN VDD
    DIRECTION INOUT ;
    USE POWER ;
    PORT
      LAYER M6 ;
        RECT  1.44 101.6 102.564 101.888 ;
        RECT  1.44 90.8 102.564 91.088 ;
        RECT  1.44 80 102.564 80.288 ;
        RECT  1.44 69.2 102.564 69.488 ;
        RECT  1.44 58.4 102.564 58.688 ;
        RECT  1.44 47.6 102.564 47.888 ;
        RECT  1.44 36.8 102.564 37.088 ;
        RECT  1.44 26 102.564 26.288 ;
        RECT  1.44 15.2 102.564 15.488 ;
        RECT  1.44 4.4 102.564 4.688 ;
        RECT  1.44 102.474 102.564 102.762 ;
        RECT  1.44 1.188 102.564 1.476 ;
    END
  END VDD
  PIN VSS
    DIRECTION INOUT ;
    USE GROUND ;
    PORT
      LAYER M6 ;
        RECT  1.44 101.216 102.564 101.504 ;
        RECT  1.44 90.416 102.564 90.704 ;
        RECT  1.44 79.616 102.564 79.904 ;
        RECT  1.44 68.816 102.564 69.104 ;
        RECT  1.44 58.016 102.564 58.304 ;
        RECT  1.44 47.216 102.564 47.504 ;
        RECT  1.44 36.416 102.564 36.704 ;
        RECT  1.44 25.616 102.564 25.904 ;
        RECT  1.44 14.816 102.564 15.104 ;
        RECT  1.44 4.016 102.564 4.304 ;
        RECT  1.632 102.09 102.372 102.378 ;
        RECT  1.632 1.572 102.372 1.86 ;
    END
  END VSS
  OBS
    LAYER RVTN ;
     RECT  0 0 104 104 ;
    LAYER RVTP ;
     RECT  0 0 104 104 ;
    LAYER M1 ;
     RECT  0 0 104 104 ;
    LAYER M2 ;
     RECT  0 0 104 104 ;
    LAYER M3 ;
     RECT  0 0 104 104 ;
    LAYER M4 ;
     RECT  0 0 104 104 ;
    LAYER M5 ;
     RECT  0 0 104 104 ;
    LAYER M6 ;
     RECT  0 0 104 104 ;
  END
END ot_gpu_bd_col
END LIBRARY
